VERSION 5.8 ;
BUSBITCHARS "[]" ;
DIVIDERCHAR "/" ;
UNITS
    DATABASE MICRONS 1000 ;
END UNITS

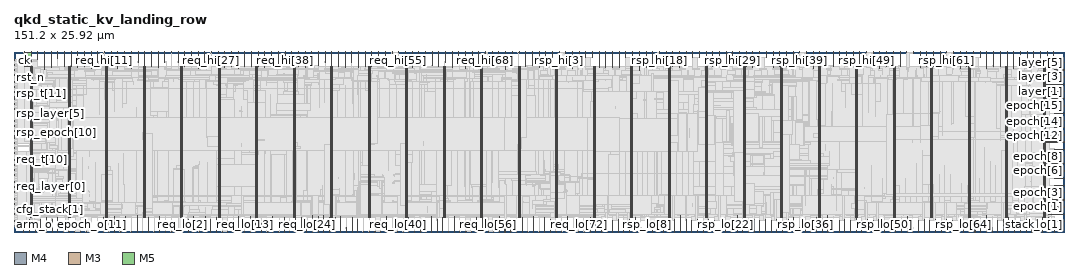
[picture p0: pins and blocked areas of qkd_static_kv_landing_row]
MACRO qkd_static_kv_landing_row
  FOREIGN qkd_static_kv_landing_row 0 0 ;
  CLASS BLOCK ;
  SIZE 151.2 BY 25.92 ;
  PIN arm
    DIRECTION INPUT ;
    USE SIGNAL ;
    PORT
      LAYER M4 ;
        RECT  151.116 1.488 151.2 1.512 ;
    END
    PORT
      LAYER M4 ;
        RECT  149.425 1.488 151.164 1.512 ;
    END
  END arm
  PIN arm_o
    DIRECTION OUTPUT ;
    USE SIGNAL ;
    PORT
      LAYER M3 ;
        RECT  1.404 0 1.422 0.038 ;
    END
    PORT
      LAYER M3 ;
        RECT  1.404 0.012 1.422 1.099 ;
    END
  END arm_o
  PIN cfg_group[0]
    DIRECTION INPUT ;
    USE SIGNAL ;
    PORT
      LAYER M4 ;
        RECT  0 1.104 0.084 1.128 ;
    END
  END cfg_group[0]
  PIN cfg_group[1]
    DIRECTION INPUT ;
    USE SIGNAL ;
    PORT
      LAYER M4 ;
        RECT  0 1.344 0.084 1.368 ;
    END
  END cfg_group[1]
  PIN cfg_group[2]
    DIRECTION INPUT ;
    USE SIGNAL ;
    PORT
      LAYER M4 ;
        RECT  0 1.584 0.084 1.608 ;
    END
  END cfg_group[2]
  PIN cfg_stack[0]
    DIRECTION INPUT ;
    USE SIGNAL ;
    PORT
      LAYER M4 ;
        RECT  0 1.824 0.084 1.848 ;
    END
  END cfg_stack[0]
  PIN cfg_stack[1]
    DIRECTION INPUT ;
    USE SIGNAL ;
    PORT
      LAYER M4 ;
        RECT  0 2.064 0.084 2.088 ;
    END
  END cfg_stack[1]
  PIN ck
    DIRECTION INPUT ;
    USE SIGNAL ;
    PORT
      LAYER M3 ;
        RECT  1.476 25.882 1.494 25.92 ;
    END
    PORT
      LAYER M3 ;
        RECT  1.476 25.819 1.494 25.901 ;
    END
  END ck
  PIN epoch[0]
    DIRECTION INPUT ;
    USE SIGNAL ;
    PORT
      LAYER M4 ;
        RECT  151.116 2.544 151.2 2.568 ;
    END
    PORT
      LAYER M4 ;
        RECT  148.979 2.544 151.164 2.568 ;
    END
  END epoch[0]
  PIN epoch[10]
    DIRECTION INPUT ;
    USE SIGNAL ;
    PORT
      LAYER M4 ;
        RECT  151.116 12.96 151.2 12.984 ;
    END
    PORT
      LAYER M4 ;
        RECT  148.504 12.96 151.164 12.984 ;
    END
  END epoch[10]
  PIN epoch[11]
    DIRECTION INPUT ;
    USE SIGNAL ;
    PORT
      LAYER M4 ;
        RECT  151.116 13.968 151.2 13.992 ;
    END
    PORT
      LAYER M4 ;
        RECT  149.857 13.968 151.164 13.992 ;
    END
  END epoch[11]
  PIN epoch[12]
    DIRECTION INPUT ;
    USE SIGNAL ;
    PORT
      LAYER M4 ;
        RECT  151.116 15.024 151.2 15.048 ;
    END
    PORT
      LAYER M4 ;
        RECT  149.857 15.024 151.164 15.048 ;
    END
  END epoch[12]
  PIN epoch[13]
    DIRECTION INPUT ;
    USE SIGNAL ;
    PORT
      LAYER M4 ;
        RECT  151.116 16.08 151.2 16.104 ;
    END
    PORT
      LAYER M4 ;
        RECT  148.504 16.08 151.164 16.104 ;
    END
  END epoch[13]
  PIN epoch[14]
    DIRECTION INPUT ;
    USE SIGNAL ;
    PORT
      LAYER M4 ;
        RECT  151.116 17.088 151.2 17.112 ;
    END
    PORT
      LAYER M4 ;
        RECT  149.857 17.088 151.164 17.112 ;
    END
  END epoch[14]
  PIN epoch[15]
    DIRECTION INPUT ;
    USE SIGNAL ;
    PORT
      LAYER M4 ;
        RECT  151.116 18.144 151.2 18.168 ;
    END
    PORT
      LAYER M4 ;
        RECT  151.081 18.144 151.164 18.168 ;
    END
  END epoch[15]
  PIN epoch[1]
    DIRECTION INPUT ;
    USE SIGNAL ;
    PORT
      LAYER M4 ;
        RECT  151.116 3.6 151.2 3.624 ;
    END
    PORT
      LAYER M4 ;
        RECT  149.857 3.6 151.164 3.624 ;
    END
  END epoch[1]
  PIN epoch[2]
    DIRECTION INPUT ;
    USE SIGNAL ;
    PORT
      LAYER M4 ;
        RECT  151.116 4.608 151.2 4.632 ;
    END
    PORT
      LAYER M4 ;
        RECT  149.497 4.608 151.164 4.632 ;
    END
  END epoch[2]
  PIN epoch[3]
    DIRECTION INPUT ;
    USE SIGNAL ;
    PORT
      LAYER M4 ;
        RECT  151.116 5.664 151.2 5.688 ;
    END
    PORT
      LAYER M4 ;
        RECT  149.857 5.664 151.164 5.688 ;
    END
  END epoch[3]
  PIN epoch[4]
    DIRECTION INPUT ;
    USE SIGNAL ;
    PORT
      LAYER M4 ;
        RECT  151.116 6.72 151.2 6.744 ;
    END
    PORT
      LAYER M4 ;
        RECT  149.857 6.72 151.164 6.744 ;
    END
  END epoch[4]
  PIN epoch[5]
    DIRECTION INPUT ;
    USE SIGNAL ;
    PORT
      LAYER M4 ;
        RECT  151.116 7.728 151.2 7.752 ;
    END
    PORT
      LAYER M4 ;
        RECT  149.857 7.728 151.164 7.752 ;
    END
  END epoch[5]
  PIN epoch[6]
    DIRECTION INPUT ;
    USE SIGNAL ;
    PORT
      LAYER M4 ;
        RECT  151.116 8.784 151.2 8.808 ;
    END
    PORT
      LAYER M4 ;
        RECT  149.857 8.784 151.164 8.808 ;
    END
  END epoch[6]
  PIN epoch[7]
    DIRECTION INPUT ;
    USE SIGNAL ;
    PORT
      LAYER M4 ;
        RECT  151.116 9.84 151.2 9.864 ;
    END
    PORT
      LAYER M4 ;
        RECT  148.504 9.84 151.164 9.864 ;
    END
  END epoch[7]
  PIN epoch[8]
    DIRECTION INPUT ;
    USE SIGNAL ;
    PORT
      LAYER M4 ;
        RECT  151.116 10.848 151.2 10.872 ;
    END
    PORT
      LAYER M4 ;
        RECT  151.081 10.848 151.164 10.872 ;
    END
  END epoch[8]
  PIN epoch[9]
    DIRECTION INPUT ;
    USE SIGNAL ;
    PORT
      LAYER M4 ;
        RECT  151.116 11.904 151.2 11.928 ;
    END
    PORT
      LAYER M4 ;
        RECT  149.857 11.904 151.164 11.928 ;
    END
  END epoch[9]
  PIN epoch_o[0]
    DIRECTION OUTPUT ;
    USE SIGNAL ;
    PORT
      LAYER M5 ;
        RECT  2.208 0 2.232 0.084 ;
    END
    PORT
      LAYER M5 ;
        RECT  2.208 0.016 2.232 1.763 ;
    END
  END epoch_o[0]
  PIN epoch_o[10]
    DIRECTION OUTPUT ;
    USE SIGNAL ;
    PORT
      LAYER M5 ;
        RECT  10.368 0 10.392 0.084 ;
    END
    PORT
      LAYER M5 ;
        RECT  10.368 0.016 10.392 0.131 ;
    END
  END epoch_o[10]
  PIN epoch_o[11]
    DIRECTION OUTPUT ;
    USE SIGNAL ;
    PORT
      LAYER M3 ;
        RECT  11.196 0 11.214 0.038 ;
    END
    PORT
      LAYER M3 ;
        RECT  11.196 0.012 11.214 0.091 ;
    END
  END epoch_o[11]
  PIN epoch_o[12]
    DIRECTION OUTPUT ;
    USE SIGNAL ;
    PORT
      LAYER M5 ;
        RECT  12 0 12.024 0.084 ;
    END
    PORT
      LAYER M5 ;
        RECT  12 0.016 12.024 0.131 ;
    END
  END epoch_o[12]
  PIN epoch_o[13]
    DIRECTION OUTPUT ;
    USE SIGNAL ;
    PORT
      LAYER M3 ;
        RECT  12.816 0 12.834 0.038 ;
    END
    PORT
      LAYER M3 ;
        RECT  12.816 0.012 12.834 2.143 ;
    END
  END epoch_o[13]
  PIN epoch_o[14]
    DIRECTION OUTPUT ;
    USE SIGNAL ;
    PORT
      LAYER M5 ;
        RECT  13.632 0 13.656 0.084 ;
    END
    PORT
      LAYER M5 ;
        RECT  13.632 0.016 13.656 0.131 ;
    END
  END epoch_o[14]
  PIN epoch_o[15]
    DIRECTION OUTPUT ;
    USE SIGNAL ;
    PORT
      LAYER M3 ;
        RECT  14.436 0 14.454 0.038 ;
    END
    PORT
      LAYER M3 ;
        RECT  14.436 0.012 14.454 2.191 ;
    END
  END epoch_o[15]
  PIN epoch_o[1]
    DIRECTION OUTPUT ;
    USE SIGNAL ;
    PORT
      LAYER M3 ;
        RECT  3.024 0 3.042 0.038 ;
    END
    PORT
      LAYER M3 ;
        RECT  3.024 0.012 3.042 1.339 ;
    END
  END epoch_o[1]
  PIN epoch_o[2]
    DIRECTION OUTPUT ;
    USE SIGNAL ;
    PORT
      LAYER M5 ;
        RECT  3.84 0 3.864 0.084 ;
    END
    PORT
      LAYER M5 ;
        RECT  3.84 0.016 3.864 1.763 ;
    END
  END epoch_o[2]
  PIN epoch_o[3]
    DIRECTION OUTPUT ;
    USE SIGNAL ;
    PORT
      LAYER M3 ;
        RECT  4.644 0 4.662 0.038 ;
    END
    PORT
      LAYER M3 ;
        RECT  4.644 0.012 4.662 2.029 ;
    END
  END epoch_o[3]
  PIN epoch_o[4]
    DIRECTION OUTPUT ;
    USE SIGNAL ;
    PORT
      LAYER M5 ;
        RECT  5.472 0 5.496 0.084 ;
    END
    PORT
      LAYER M5 ;
        RECT  5.472 0.016 5.496 1.763 ;
    END
  END epoch_o[4]
  PIN epoch_o[5]
    DIRECTION OUTPUT ;
    USE SIGNAL ;
    PORT
      LAYER M3 ;
        RECT  6.3 0 6.318 0.038 ;
    END
    PORT
      LAYER M3 ;
        RECT  6.3 0.012 6.318 2.101 ;
    END
  END epoch_o[5]
  PIN epoch_o[6]
    DIRECTION OUTPUT ;
    USE SIGNAL ;
    PORT
      LAYER M5 ;
        RECT  7.104 0 7.128 0.084 ;
    END
    PORT
      LAYER M5 ;
        RECT  7.104 0.016 7.128 0.611 ;
    END
  END epoch_o[6]
  PIN epoch_o[7]
    DIRECTION OUTPUT ;
    USE SIGNAL ;
    PORT
      LAYER M3 ;
        RECT  7.92 0 7.938 0.038 ;
    END
    PORT
      LAYER M3 ;
        RECT  7.92 0.012 7.938 0.031 ;
    END
    PORT
      LAYER M3 ;
        RECT  7.776 0.031 7.938 0.059 ;
    END
  END epoch_o[7]
  PIN epoch_o[8]
    DIRECTION OUTPUT ;
    USE SIGNAL ;
    PORT
      LAYER M5 ;
        RECT  8.736 0 8.76 0.084 ;
    END
    PORT
      LAYER M5 ;
        RECT  8.736 0.016 8.76 0.131 ;
    END
  END epoch_o[8]
  PIN epoch_o[9]
    DIRECTION OUTPUT ;
    USE SIGNAL ;
    PORT
      LAYER M3 ;
        RECT  9.54 0 9.558 0.038 ;
    END
    PORT
      LAYER M3 ;
        RECT  9.54 0.012 9.558 0.091 ;
    END
  END epoch_o[9]
  PIN fault
    DIRECTION OUTPUT ;
    USE SIGNAL ;
    PORT
      LAYER M4 ;
        RECT  0 2.352 0.084 2.376 ;
    END
  END fault
  PIN group_o[0]
    DIRECTION OUTPUT ;
    USE SIGNAL ;
    PORT
      LAYER M5 ;
        RECT  15.264 0 15.288 0.084 ;
    END
    PORT
      LAYER M5 ;
        RECT  15.264 0.016 15.288 0.131 ;
    END
  END group_o[0]
  PIN group_o[1]
    DIRECTION OUTPUT ;
    USE SIGNAL ;
    PORT
      LAYER M3 ;
        RECT  16.092 0 16.11 0.038 ;
    END
    PORT
      LAYER M3 ;
        RECT  16.092 0.012 16.11 2.191 ;
    END
  END group_o[1]
  PIN group_o[2]
    DIRECTION OUTPUT ;
    USE SIGNAL ;
    PORT
      LAYER M5 ;
        RECT  16.896 0 16.92 0.084 ;
    END
    PORT
      LAYER M5 ;
        RECT  16.896 0.016 16.92 0.131 ;
    END
  END group_o[2]
  PIN layer[0]
    DIRECTION INPUT ;
    USE SIGNAL ;
    PORT
      LAYER M4 ;
        RECT  151.116 19.2 151.2 19.224 ;
    END
    PORT
      LAYER M4 ;
        RECT  148.504 19.2 151.164 19.224 ;
    END
  END layer[0]
  PIN layer[1]
    DIRECTION INPUT ;
    USE SIGNAL ;
    PORT
      LAYER M4 ;
        RECT  151.116 20.208 151.2 20.232 ;
    END
    PORT
      LAYER M4 ;
        RECT  148.504 20.208 151.164 20.232 ;
    END
  END layer[1]
  PIN layer[2]
    DIRECTION INPUT ;
    USE SIGNAL ;
    PORT
      LAYER M4 ;
        RECT  151.116 21.264 151.2 21.288 ;
    END
    PORT
      LAYER M4 ;
        RECT  148.504 21.264 151.164 21.288 ;
    END
  END layer[2]
  PIN layer[3]
    DIRECTION INPUT ;
    USE SIGNAL ;
    PORT
      LAYER M4 ;
        RECT  151.116 22.32 151.2 22.344 ;
    END
    PORT
      LAYER M4 ;
        RECT  149.893 22.32 151.164 22.344 ;
    END
  END layer[3]
  PIN layer[4]
    DIRECTION INPUT ;
    USE SIGNAL ;
    PORT
      LAYER M4 ;
        RECT  151.116 23.328 151.2 23.352 ;
    END
    PORT
      LAYER M4 ;
        RECT  149.857 23.328 151.164 23.352 ;
    END
  END layer[4]
  PIN layer[5]
    DIRECTION INPUT ;
    USE SIGNAL ;
    PORT
      LAYER M4 ;
        RECT  151.116 24.384 151.2 24.408 ;
    END
    PORT
      LAYER M4 ;
        RECT  150.433 24.384 151.164 24.408 ;
    END
  END layer[5]
  PIN layer_o[0]
    DIRECTION OUTPUT ;
    USE SIGNAL ;
    PORT
      LAYER M3 ;
        RECT  17.712 0 17.73 0.038 ;
    END
    PORT
      LAYER M3 ;
        RECT  17.712 0.012 17.73 2.335 ;
    END
  END layer_o[0]
  PIN layer_o[1]
    DIRECTION OUTPUT ;
    USE SIGNAL ;
    PORT
      LAYER M5 ;
        RECT  18.528 0 18.552 0.084 ;
    END
    PORT
      LAYER M5 ;
        RECT  18.528 0.016 18.552 0.131 ;
    END
  END layer_o[1]
  PIN layer_o[2]
    DIRECTION OUTPUT ;
    USE SIGNAL ;
    PORT
      LAYER M3 ;
        RECT  19.332 0 19.35 0.038 ;
    END
    PORT
      LAYER M3 ;
        RECT  19.332 0.012 19.35 2.143 ;
    END
  END layer_o[2]
  PIN layer_o[3]
    DIRECTION OUTPUT ;
    USE SIGNAL ;
    PORT
      LAYER M5 ;
        RECT  20.16 0 20.184 0.084 ;
    END
    PORT
      LAYER M5 ;
        RECT  20.16 0.016 20.184 0.131 ;
    END
  END layer_o[3]
  PIN layer_o[4]
    DIRECTION OUTPUT ;
    USE SIGNAL ;
    PORT
      LAYER M3 ;
        RECT  20.952 0 20.97 0.038 ;
    END
    PORT
      LAYER M3 ;
        RECT  20.952 0.012 20.97 2.263 ;
    END
  END layer_o[4]
  PIN layer_o[5]
    DIRECTION OUTPUT ;
    USE SIGNAL ;
    PORT
      LAYER M5 ;
        RECT  21.792 0 21.816 0.084 ;
    END
    PORT
      LAYER M5 ;
        RECT  21.792 0.016 21.816 0.131 ;
    END
  END layer_o[5]
  PIN req_epoch[0]
    DIRECTION INPUT ;
    USE SIGNAL ;
    PORT
      LAYER M4 ;
        RECT  0 2.592 0.084 2.616 ;
    END
  END req_epoch[0]
  PIN req_epoch[10]
    DIRECTION INPUT ;
    USE SIGNAL ;
    PORT
      LAYER M4 ;
        RECT  0 4.992 0.084 5.016 ;
    END
  END req_epoch[10]
  PIN req_epoch[11]
    DIRECTION INPUT ;
    USE SIGNAL ;
    PORT
      LAYER M4 ;
        RECT  0 5.28 0.084 5.304 ;
    END
  END req_epoch[11]
  PIN req_epoch[12]
    DIRECTION INPUT ;
    USE SIGNAL ;
    PORT
      LAYER M4 ;
        RECT  0 5.52 0.084 5.544 ;
    END
  END req_epoch[12]
  PIN req_epoch[13]
    DIRECTION INPUT ;
    USE SIGNAL ;
    PORT
      LAYER M4 ;
        RECT  0 5.76 0.084 5.784 ;
    END
  END req_epoch[13]
  PIN req_epoch[14]
    DIRECTION INPUT ;
    USE SIGNAL ;
    PORT
      LAYER M4 ;
        RECT  0 6 0.084 6.024 ;
    END
  END req_epoch[14]
  PIN req_epoch[15]
    DIRECTION INPUT ;
    USE SIGNAL ;
    PORT
      LAYER M4 ;
        RECT  0 6.24 0.084 6.264 ;
    END
  END req_epoch[15]
  PIN req_epoch[1]
    DIRECTION INPUT ;
    USE SIGNAL ;
    PORT
      LAYER M4 ;
        RECT  0 2.832 0.084 2.856 ;
    END
  END req_epoch[1]
  PIN req_epoch[2]
    DIRECTION INPUT ;
    USE SIGNAL ;
    PORT
      LAYER M4 ;
        RECT  0 3.072 0.084 3.096 ;
    END
  END req_epoch[2]
  PIN req_epoch[3]
    DIRECTION INPUT ;
    USE SIGNAL ;
    PORT
      LAYER M4 ;
        RECT  0 3.312 0.084 3.336 ;
    END
  END req_epoch[3]
  PIN req_epoch[4]
    DIRECTION INPUT ;
    USE SIGNAL ;
    PORT
      LAYER M4 ;
        RECT  0 3.552 0.084 3.576 ;
    END
  END req_epoch[4]
  PIN req_epoch[5]
    DIRECTION INPUT ;
    USE SIGNAL ;
    PORT
      LAYER M4 ;
        RECT  0 3.792 0.084 3.816 ;
    END
  END req_epoch[5]
  PIN req_epoch[6]
    DIRECTION INPUT ;
    USE SIGNAL ;
    PORT
      LAYER M4 ;
        RECT  0 4.032 0.084 4.056 ;
    END
  END req_epoch[6]
  PIN req_epoch[7]
    DIRECTION INPUT ;
    USE SIGNAL ;
    PORT
      LAYER M4 ;
        RECT  0 4.272 0.084 4.296 ;
    END
  END req_epoch[7]
  PIN req_epoch[8]
    DIRECTION INPUT ;
    USE SIGNAL ;
    PORT
      LAYER M4 ;
        RECT  0 4.512 0.084 4.536 ;
    END
  END req_epoch[8]
  PIN req_epoch[9]
    DIRECTION INPUT ;
    USE SIGNAL ;
    PORT
      LAYER M4 ;
        RECT  0 4.752 0.084 4.776 ;
    END
  END req_epoch[9]
  PIN req_hi[0]
    DIRECTION OUTPUT ;
    USE SIGNAL ;
    PORT
      LAYER M5 ;
        RECT  2.448 25.836 2.472 25.92 ;
    END
    PORT
      LAYER M5 ;
        RECT  1.488 23.783 2.472 25.859 ;
    END
    PORT
      LAYER M5 ;
        RECT  2.448 25.859 2.472 25.872 ;
    END
  END req_hi[0]
  PIN req_hi[10]
    DIRECTION OUTPUT ;
    USE SIGNAL ;
    PORT
      LAYER M5 ;
        RECT  12.048 25.836 12.072 25.92 ;
    END
    PORT
      LAYER M5 ;
        RECT  12.048 24.469 12.072 25.872 ;
    END
  END req_hi[10]
  PIN req_hi[11]
    DIRECTION OUTPUT ;
    USE SIGNAL ;
    PORT
      LAYER M3 ;
        RECT  13.032 25.882 13.05 25.92 ;
    END
    PORT
      LAYER M3 ;
        RECT  12.96 25.861 13.05 25.889 ;
    END
    PORT
      LAYER M3 ;
        RECT  13.032 25.889 13.05 25.901 ;
    END
  END req_hi[11]
  PIN req_hi[12]
    DIRECTION OUTPUT ;
    USE SIGNAL ;
    PORT
      LAYER M5 ;
        RECT  13.968 25.836 13.992 25.92 ;
    END
    PORT
      LAYER M5 ;
        RECT  13.968 23.941 13.992 25.872 ;
    END
  END req_hi[12]
  PIN req_hi[13]
    DIRECTION OUTPUT ;
    USE SIGNAL ;
    PORT
      LAYER M3 ;
        RECT  14.94 25.882 14.958 25.92 ;
    END
    PORT
      LAYER M3 ;
        RECT  14.94 23.585 14.958 25.901 ;
    END
  END req_hi[13]
  PIN req_hi[14]
    DIRECTION OUTPUT ;
    USE SIGNAL ;
    PORT
      LAYER M5 ;
        RECT  15.888 25.836 15.912 25.92 ;
    END
    PORT
      LAYER M5 ;
        RECT  15.888 24.469 15.912 25.872 ;
    END
  END req_hi[14]
  PIN req_hi[15]
    DIRECTION OUTPUT ;
    USE SIGNAL ;
    PORT
      LAYER M3 ;
        RECT  16.884 25.882 16.902 25.92 ;
    END
    PORT
      LAYER M3 ;
        RECT  16.884 23.549 16.902 25.901 ;
    END
  END req_hi[15]
  PIN req_hi[16]
    DIRECTION OUTPUT ;
    USE SIGNAL ;
    PORT
      LAYER M5 ;
        RECT  17.856 25.836 17.88 25.92 ;
    END
    PORT
      LAYER M5 ;
        RECT  17.856 24.469 17.88 25.872 ;
    END
  END req_hi[16]
  PIN req_hi[17]
    DIRECTION OUTPUT ;
    USE SIGNAL ;
    PORT
      LAYER M3 ;
        RECT  18.792 25.882 18.81 25.92 ;
    END
    PORT
      LAYER M3 ;
        RECT  18.792 23.777 18.81 25.901 ;
    END
  END req_hi[17]
  PIN req_hi[18]
    DIRECTION OUTPUT ;
    USE SIGNAL ;
    PORT
      LAYER M5 ;
        RECT  19.776 25.836 19.8 25.92 ;
    END
    PORT
      LAYER M5 ;
        RECT  19.776 23.893 19.8 25.872 ;
    END
  END req_hi[18]
  PIN req_hi[19]
    DIRECTION OUTPUT ;
    USE SIGNAL ;
    PORT
      LAYER M3 ;
        RECT  20.736 25.882 20.754 25.92 ;
    END
    PORT
      LAYER M3 ;
        RECT  20.736 23.693 20.754 25.901 ;
    END
  END req_hi[19]
  PIN req_hi[1]
    DIRECTION OUTPUT ;
    USE SIGNAL ;
    PORT
      LAYER M3 ;
        RECT  3.384 25.882 3.402 25.92 ;
    END
    PORT
      LAYER M3 ;
        RECT  3.384 24.797 3.402 25.901 ;
    END
  END req_hi[1]
  PIN req_hi[20]
    DIRECTION OUTPUT ;
    USE SIGNAL ;
    PORT
      LAYER M5 ;
        RECT  21.696 25.836 21.72 25.92 ;
    END
    PORT
      LAYER M5 ;
        RECT  21.696 24.469 21.72 25.872 ;
    END
  END req_hi[20]
  PIN req_hi[21]
    DIRECTION OUTPUT ;
    USE SIGNAL ;
    PORT
      LAYER M3 ;
        RECT  22.644 25.882 22.662 25.92 ;
    END
    PORT
      LAYER M3 ;
        RECT  22.644 25.861 22.734 25.889 ;
    END
    PORT
      LAYER M3 ;
        RECT  22.644 25.889 22.662 25.901 ;
    END
  END req_hi[21]
  PIN req_hi[22]
    DIRECTION OUTPUT ;
    USE SIGNAL ;
    PORT
      LAYER M5 ;
        RECT  23.616 25.836 23.64 25.92 ;
    END
    PORT
      LAYER M5 ;
        RECT  23.616 24.469 23.64 25.872 ;
    END
  END req_hi[22]
  PIN req_hi[23]
    DIRECTION OUTPUT ;
    USE SIGNAL ;
    PORT
      LAYER M3 ;
        RECT  24.588 25.882 24.606 25.92 ;
    END
    PORT
      LAYER M3 ;
        RECT  24.588 23.777 24.606 25.901 ;
    END
  END req_hi[23]
  PIN req_hi[24]
    DIRECTION OUTPUT ;
    USE SIGNAL ;
    PORT
      LAYER M5 ;
        RECT  25.536 25.836 25.56 25.92 ;
    END
    PORT
      LAYER M5 ;
        RECT  25.536 23.941 25.56 25.872 ;
    END
  END req_hi[24]
  PIN req_hi[25]
    DIRECTION OUTPUT ;
    USE SIGNAL ;
    PORT
      LAYER M3 ;
        RECT  26.496 25.882 26.514 25.92 ;
    END
    PORT
      LAYER M3 ;
        RECT  26.496 23.549 26.514 25.901 ;
    END
  END req_hi[25]
  PIN req_hi[26]
    DIRECTION OUTPUT ;
    USE SIGNAL ;
    PORT
      LAYER M5 ;
        RECT  27.456 25.836 27.48 25.92 ;
    END
    PORT
      LAYER M5 ;
        RECT  27.456 24.469 27.48 25.872 ;
    END
  END req_hi[26]
  PIN req_hi[27]
    DIRECTION OUTPUT ;
    USE SIGNAL ;
    PORT
      LAYER M3 ;
        RECT  28.44 25.882 28.458 25.92 ;
    END
    PORT
      LAYER M3 ;
        RECT  28.368 25.861 28.458 25.889 ;
    END
    PORT
      LAYER M3 ;
        RECT  28.44 25.889 28.458 25.901 ;
    END
  END req_hi[27]
  PIN req_hi[28]
    DIRECTION OUTPUT ;
    USE SIGNAL ;
    PORT
      LAYER M5 ;
        RECT  29.376 25.836 29.4 25.92 ;
    END
    PORT
      LAYER M5 ;
        RECT  29.376 24.469 29.4 25.872 ;
    END
  END req_hi[28]
  PIN req_hi[29]
    DIRECTION OUTPUT ;
    USE SIGNAL ;
    PORT
      LAYER M3 ;
        RECT  30.348 25.882 30.366 25.92 ;
    END
    PORT
      LAYER M3 ;
        RECT  30.348 23.729 30.366 25.901 ;
    END
  END req_hi[29]
  PIN req_hi[2]
    DIRECTION OUTPUT ;
    USE SIGNAL ;
    PORT
      LAYER M5 ;
        RECT  4.368 25.836 4.392 25.92 ;
    END
    PORT
      LAYER M5 ;
        RECT  4.368 23.365 4.392 25.872 ;
    END
  END req_hi[2]
  PIN req_hi[30]
    DIRECTION OUTPUT ;
    USE SIGNAL ;
    PORT
      LAYER M5 ;
        RECT  31.296 25.836 31.32 25.92 ;
    END
    PORT
      LAYER M5 ;
        RECT  31.296 23.893 31.32 25.872 ;
    END
  END req_hi[30]
  PIN req_hi[31]
    DIRECTION OUTPUT ;
    USE SIGNAL ;
    PORT
      LAYER M3 ;
        RECT  32.292 25.882 32.31 25.92 ;
    END
    PORT
      LAYER M3 ;
        RECT  32.292 23.549 32.31 25.901 ;
    END
  END req_hi[31]
  PIN req_hi[32]
    DIRECTION OUTPUT ;
    USE SIGNAL ;
    PORT
      LAYER M5 ;
        RECT  33.216 25.836 33.24 25.92 ;
    END
    PORT
      LAYER M5 ;
        RECT  33.216 23.893 33.24 25.872 ;
    END
  END req_hi[32]
  PIN req_hi[33]
    DIRECTION OUTPUT ;
    USE SIGNAL ;
    PORT
      LAYER M3 ;
        RECT  34.2 25.882 34.218 25.92 ;
    END
    PORT
      LAYER M3 ;
        RECT  34.2 23.777 34.218 25.901 ;
    END
  END req_hi[33]
  PIN req_hi[34]
    DIRECTION OUTPUT ;
    USE SIGNAL ;
    PORT
      LAYER M5 ;
        RECT  35.184 25.836 35.208 25.92 ;
    END
    PORT
      LAYER M5 ;
        RECT  35.184 23.893 35.208 25.872 ;
    END
  END req_hi[34]
  PIN req_hi[35]
    DIRECTION OUTPUT ;
    USE SIGNAL ;
    PORT
      LAYER M3 ;
        RECT  36.108 25.882 36.126 25.92 ;
    END
    PORT
      LAYER M3 ;
        RECT  36.108 23.729 36.126 25.901 ;
    END
  END req_hi[35]
  PIN req_hi[36]
    DIRECTION OUTPUT ;
    USE SIGNAL ;
    PORT
      LAYER M5 ;
        RECT  37.104 25.836 37.128 25.92 ;
    END
    PORT
      LAYER M5 ;
        RECT  37.104 24.469 37.128 25.872 ;
    END
  END req_hi[36]
  PIN req_hi[37]
    DIRECTION OUTPUT ;
    USE SIGNAL ;
    PORT
      LAYER M3 ;
        RECT  38.052 25.882 38.07 25.92 ;
    END
    PORT
      LAYER M3 ;
        RECT  38.052 23.729 38.07 25.901 ;
    END
  END req_hi[37]
  PIN req_hi[38]
    DIRECTION OUTPUT ;
    USE SIGNAL ;
    PORT
      LAYER M5 ;
        RECT  39.024 25.836 39.048 25.92 ;
    END
    PORT
      LAYER M5 ;
        RECT  39.024 24.469 39.048 25.872 ;
    END
  END req_hi[38]
  PIN req_hi[39]
    DIRECTION OUTPUT ;
    USE SIGNAL ;
    PORT
      LAYER M3 ;
        RECT  39.96 25.882 39.978 25.92 ;
    END
    PORT
      LAYER M3 ;
        RECT  39.96 23.777 39.978 25.901 ;
    END
  END req_hi[39]
  PIN req_hi[3]
    DIRECTION OUTPUT ;
    USE SIGNAL ;
    PORT
      LAYER M3 ;
        RECT  5.328 25.882 5.346 25.92 ;
    END
    PORT
      LAYER M3 ;
        RECT  5.328 23.729 5.346 25.901 ;
    END
  END req_hi[3]
  PIN req_hi[40]
    DIRECTION OUTPUT ;
    USE SIGNAL ;
    PORT
      LAYER M5 ;
        RECT  40.944 25.836 40.968 25.92 ;
    END
    PORT
      LAYER M5 ;
        RECT  40.944 23.893 40.968 25.872 ;
    END
  END req_hi[40]
  PIN req_hi[41]
    DIRECTION OUTPUT ;
    USE SIGNAL ;
    PORT
      LAYER M3 ;
        RECT  41.904 25.882 41.922 25.92 ;
    END
    PORT
      LAYER M3 ;
        RECT  41.904 23.621 41.922 25.901 ;
    END
  END req_hi[41]
  PIN req_hi[42]
    DIRECTION OUTPUT ;
    USE SIGNAL ;
    PORT
      LAYER M5 ;
        RECT  42.864 25.836 42.888 25.92 ;
    END
    PORT
      LAYER M5 ;
        RECT  42.864 23.893 42.888 25.872 ;
    END
  END req_hi[42]
  PIN req_hi[43]
    DIRECTION OUTPUT ;
    USE SIGNAL ;
    PORT
      LAYER M3 ;
        RECT  43.812 25.882 43.83 25.92 ;
    END
    PORT
      LAYER M3 ;
        RECT  43.812 23.933 43.83 25.901 ;
    END
  END req_hi[43]
  PIN req_hi[44]
    DIRECTION OUTPUT ;
    USE SIGNAL ;
    PORT
      LAYER M5 ;
        RECT  44.784 25.836 44.808 25.92 ;
    END
    PORT
      LAYER M5 ;
        RECT  44.784 24.469 44.808 25.872 ;
    END
  END req_hi[44]
  PIN req_hi[45]
    DIRECTION OUTPUT ;
    USE SIGNAL ;
    PORT
      LAYER M3 ;
        RECT  45.756 25.882 45.774 25.92 ;
    END
    PORT
      LAYER M3 ;
        RECT  45.756 23.777 45.774 25.901 ;
    END
  END req_hi[45]
  PIN req_hi[46]
    DIRECTION OUTPUT ;
    USE SIGNAL ;
    PORT
      LAYER M5 ;
        RECT  46.704 25.836 46.728 25.92 ;
    END
    PORT
      LAYER M5 ;
        RECT  46.704 23.769 46.728 25.872 ;
    END
  END req_hi[46]
  PIN req_hi[47]
    DIRECTION OUTPUT ;
    USE SIGNAL ;
    PORT
      LAYER M3 ;
        RECT  47.664 25.882 47.682 25.92 ;
    END
    PORT
      LAYER M3 ;
        RECT  47.664 23.621 47.682 25.901 ;
    END
  END req_hi[47]
  PIN req_hi[48]
    DIRECTION OUTPUT ;
    USE SIGNAL ;
    PORT
      LAYER M5 ;
        RECT  48.624 25.836 48.648 25.92 ;
    END
    PORT
      LAYER M5 ;
        RECT  48.624 24.469 48.648 25.872 ;
    END
  END req_hi[48]
  PIN req_hi[49]
    DIRECTION OUTPUT ;
    USE SIGNAL ;
    PORT
      LAYER M3 ;
        RECT  49.608 25.882 49.626 25.92 ;
    END
    PORT
      LAYER M3 ;
        RECT  49.608 23.657 49.626 25.901 ;
    END
  END req_hi[49]
  PIN req_hi[4]
    DIRECTION OUTPUT ;
    USE SIGNAL ;
    PORT
      LAYER M5 ;
        RECT  6.288 25.836 6.312 25.92 ;
    END
    PORT
      LAYER M5 ;
        RECT  6.288 25.045 6.312 25.872 ;
    END
  END req_hi[4]
  PIN req_hi[50]
    DIRECTION OUTPUT ;
    USE SIGNAL ;
    PORT
      LAYER M5 ;
        RECT  50.544 25.836 50.568 25.92 ;
    END
    PORT
      LAYER M5 ;
        RECT  50.544 23.783 50.568 25.872 ;
    END
  END req_hi[50]
  PIN req_hi[51]
    DIRECTION OUTPUT ;
    USE SIGNAL ;
    PORT
      LAYER M3 ;
        RECT  51.516 25.882 51.534 25.92 ;
    END
    PORT
      LAYER M3 ;
        RECT  51.516 23.777 51.534 25.901 ;
    END
  END req_hi[51]
  PIN req_hi[52]
    DIRECTION OUTPUT ;
    USE SIGNAL ;
    PORT
      LAYER M5 ;
        RECT  52.464 25.836 52.488 25.92 ;
    END
    PORT
      LAYER M5 ;
        RECT  52.464 25.045 52.488 25.872 ;
    END
  END req_hi[52]
  PIN req_hi[53]
    DIRECTION OUTPUT ;
    USE SIGNAL ;
    PORT
      LAYER M3 ;
        RECT  53.46 25.882 53.478 25.92 ;
    END
    PORT
      LAYER M3 ;
        RECT  53.46 23.621 53.478 25.901 ;
    END
  END req_hi[53]
  PIN req_hi[54]
    DIRECTION OUTPUT ;
    USE SIGNAL ;
    PORT
      LAYER M5 ;
        RECT  54.432 25.836 54.456 25.92 ;
    END
    PORT
      LAYER M5 ;
        RECT  54.432 25.765 54.456 25.872 ;
    END
  END req_hi[54]
  PIN req_hi[55]
    DIRECTION OUTPUT ;
    USE SIGNAL ;
    PORT
      LAYER M3 ;
        RECT  55.368 25.882 55.386 25.92 ;
    END
    PORT
      LAYER M3 ;
        RECT  55.296 25.861 55.386 25.889 ;
    END
    PORT
      LAYER M3 ;
        RECT  55.368 25.889 55.386 25.901 ;
    END
  END req_hi[55]
  PIN req_hi[56]
    DIRECTION OUTPUT ;
    USE SIGNAL ;
    PORT
      LAYER M5 ;
        RECT  56.352 25.836 56.376 25.92 ;
    END
    PORT
      LAYER M5 ;
        RECT  56.352 23.893 56.376 25.872 ;
    END
  END req_hi[56]
  PIN req_hi[57]
    DIRECTION OUTPUT ;
    USE SIGNAL ;
    PORT
      LAYER M3 ;
        RECT  57.312 25.882 57.33 25.92 ;
    END
    PORT
      LAYER M3 ;
        RECT  57.312 23.621 57.33 25.901 ;
    END
  END req_hi[57]
  PIN req_hi[58]
    DIRECTION OUTPUT ;
    USE SIGNAL ;
    PORT
      LAYER M5 ;
        RECT  58.272 25.836 58.296 25.92 ;
    END
    PORT
      LAYER M5 ;
        RECT  58.272 24.469 58.296 25.872 ;
    END
  END req_hi[58]
  PIN req_hi[59]
    DIRECTION OUTPUT ;
    USE SIGNAL ;
    PORT
      LAYER M3 ;
        RECT  59.22 25.882 59.238 25.92 ;
    END
    PORT
      LAYER M3 ;
        RECT  59.22 24.509 59.238 25.901 ;
    END
  END req_hi[59]
  PIN req_hi[5]
    DIRECTION OUTPUT ;
    USE SIGNAL ;
    PORT
      LAYER M3 ;
        RECT  7.236 25.882 7.254 25.92 ;
    END
    PORT
      LAYER M3 ;
        RECT  7.236 23.777 7.254 25.901 ;
    END
  END req_hi[5]
  PIN req_hi[60]
    DIRECTION OUTPUT ;
    USE SIGNAL ;
    PORT
      LAYER M5 ;
        RECT  60.192 25.836 60.216 25.92 ;
    END
    PORT
      LAYER M5 ;
        RECT  60.192 23.941 60.216 25.872 ;
    END
  END req_hi[60]
  PIN req_hi[61]
    DIRECTION OUTPUT ;
    USE SIGNAL ;
    PORT
      LAYER M3 ;
        RECT  61.164 25.882 61.182 25.92 ;
    END
    PORT
      LAYER M3 ;
        RECT  61.164 23.777 61.182 25.901 ;
    END
  END req_hi[61]
  PIN req_hi[62]
    DIRECTION OUTPUT ;
    USE SIGNAL ;
    PORT
      LAYER M5 ;
        RECT  62.112 25.836 62.136 25.92 ;
    END
    PORT
      LAYER M5 ;
        RECT  62.112 24.469 62.136 25.872 ;
    END
  END req_hi[62]
  PIN req_hi[63]
    DIRECTION OUTPUT ;
    USE SIGNAL ;
    PORT
      LAYER M3 ;
        RECT  63.072 25.882 63.09 25.92 ;
    END
    PORT
      LAYER M3 ;
        RECT  63.072 23.621 63.09 25.901 ;
    END
  END req_hi[63]
  PIN req_hi[64]
    DIRECTION OUTPUT ;
    USE SIGNAL ;
    PORT
      LAYER M5 ;
        RECT  64.032 25.836 64.056 25.92 ;
    END
    PORT
      LAYER M5 ;
        RECT  64.032 25.045 64.056 25.872 ;
    END
  END req_hi[64]
  PIN req_hi[65]
    DIRECTION OUTPUT ;
    USE SIGNAL ;
    PORT
      LAYER M3 ;
        RECT  65.016 25.882 65.034 25.92 ;
    END
    PORT
      LAYER M3 ;
        RECT  65.016 23.585 65.034 25.901 ;
    END
  END req_hi[65]
  PIN req_hi[66]
    DIRECTION OUTPUT ;
    USE SIGNAL ;
    PORT
      LAYER M5 ;
        RECT  65.952 25.836 65.976 25.92 ;
    END
    PORT
      LAYER M5 ;
        RECT  65.952 23.893 65.976 25.872 ;
    END
  END req_hi[66]
  PIN req_hi[67]
    DIRECTION OUTPUT ;
    USE SIGNAL ;
    PORT
      LAYER M3 ;
        RECT  66.924 25.882 66.942 25.92 ;
    END
    PORT
      LAYER M3 ;
        RECT  66.924 23.777 66.942 25.901 ;
    END
  END req_hi[67]
  PIN req_hi[68]
    DIRECTION OUTPUT ;
    USE SIGNAL ;
    PORT
      LAYER M5 ;
        RECT  67.872 25.836 67.896 25.92 ;
    END
    PORT
      LAYER M5 ;
        RECT  67.872 25.765 67.896 25.872 ;
    END
  END req_hi[68]
  PIN req_hi[69]
    DIRECTION OUTPUT ;
    USE SIGNAL ;
    PORT
      LAYER M3 ;
        RECT  68.868 25.882 68.886 25.92 ;
    END
    PORT
      LAYER M3 ;
        RECT  68.868 23.729 68.886 25.901 ;
    END
  END req_hi[69]
  PIN req_hi[6]
    DIRECTION OUTPUT ;
    USE SIGNAL ;
    PORT
      LAYER M5 ;
        RECT  8.208 25.836 8.232 25.92 ;
    END
    PORT
      LAYER M5 ;
        RECT  8.208 23.893 8.232 25.872 ;
    END
  END req_hi[6]
  PIN req_hi[70]
    DIRECTION OUTPUT ;
    USE SIGNAL ;
    PORT
      LAYER M5 ;
        RECT  69.792 25.836 69.816 25.92 ;
    END
    PORT
      LAYER M5 ;
        RECT  69.792 23.941 69.816 25.872 ;
    END
  END req_hi[70]
  PIN req_hi[71]
    DIRECTION OUTPUT ;
    USE SIGNAL ;
    PORT
      LAYER M3 ;
        RECT  70.776 25.882 70.794 25.92 ;
    END
    PORT
      LAYER M3 ;
        RECT  70.776 23.351 70.794 25.901 ;
    END
  END req_hi[71]
  PIN req_hi[72]
    DIRECTION OUTPUT ;
    USE SIGNAL ;
    PORT
      LAYER M5 ;
        RECT  71.76 25.836 71.784 25.92 ;
    END
    PORT
      LAYER M5 ;
        RECT  71.76 23.893 71.784 25.872 ;
    END
  END req_hi[72]
  PIN req_hi[73]
    DIRECTION OUTPUT ;
    USE SIGNAL ;
    PORT
      LAYER M3 ;
        RECT  72.72 25.882 72.738 25.92 ;
    END
    PORT
      LAYER M3 ;
        RECT  72.576 25.861 72.738 25.889 ;
    END
    PORT
      LAYER M3 ;
        RECT  72.72 25.889 72.738 25.901 ;
    END
  END req_hi[73]
  PIN req_hi[74]
    DIRECTION OUTPUT ;
    USE SIGNAL ;
    PORT
      LAYER M5 ;
        RECT  73.68 25.836 73.704 25.92 ;
    END
    PORT
      LAYER M5 ;
        RECT  73.68 23.893 73.704 25.872 ;
    END
  END req_hi[74]
  PIN req_hi[75]
    DIRECTION OUTPUT ;
    USE SIGNAL ;
    PORT
      LAYER M3 ;
        RECT  74.628 25.882 74.646 25.92 ;
    END
    PORT
      LAYER M3 ;
        RECT  74.628 23.933 74.646 25.901 ;
    END
  END req_hi[75]
  PIN req_hi[7]
    DIRECTION OUTPUT ;
    USE SIGNAL ;
    PORT
      LAYER M3 ;
        RECT  9.18 25.882 9.198 25.92 ;
    END
    PORT
      LAYER M3 ;
        RECT  9.18 23.621 9.198 25.901 ;
    END
  END req_hi[7]
  PIN req_hi[8]
    DIRECTION OUTPUT ;
    USE SIGNAL ;
    PORT
      LAYER M5 ;
        RECT  10.128 25.836 10.152 25.92 ;
    END
    PORT
      LAYER M5 ;
        RECT  10.128 23.893 10.152 25.872 ;
    END
  END req_hi[8]
  PIN req_hi[9]
    DIRECTION OUTPUT ;
    USE SIGNAL ;
    PORT
      LAYER M3 ;
        RECT  11.088 25.882 11.106 25.92 ;
    END
    PORT
      LAYER M3 ;
        RECT  11.088 23.585 11.106 25.901 ;
    END
  END req_hi[9]
  PIN req_layer[0]
    DIRECTION INPUT ;
    USE SIGNAL ;
    PORT
      LAYER M4 ;
        RECT  0 6.48 0.084 6.504 ;
    END
  END req_layer[0]
  PIN req_layer[1]
    DIRECTION INPUT ;
    USE SIGNAL ;
    PORT
      LAYER M4 ;
        RECT  0 6.72 0.084 6.744 ;
    END
  END req_layer[1]
  PIN req_layer[2]
    DIRECTION INPUT ;
    USE SIGNAL ;
    PORT
      LAYER M4 ;
        RECT  0 6.96 0.084 6.984 ;
    END
  END req_layer[2]
  PIN req_layer[3]
    DIRECTION INPUT ;
    USE SIGNAL ;
    PORT
      LAYER M4 ;
        RECT  0 7.2 0.084 7.224 ;
    END
  END req_layer[3]
  PIN req_layer[4]
    DIRECTION INPUT ;
    USE SIGNAL ;
    PORT
      LAYER M4 ;
        RECT  0 7.44 0.084 7.464 ;
    END
  END req_layer[4]
  PIN req_layer[5]
    DIRECTION INPUT ;
    USE SIGNAL ;
    PORT
      LAYER M4 ;
        RECT  0 7.68 0.084 7.704 ;
    END
  END req_layer[5]
  PIN req_lo[0]
    DIRECTION OUTPUT ;
    USE SIGNAL ;
    PORT
      LAYER M3 ;
        RECT  22.608 0 22.626 0.038 ;
    END
    PORT
      LAYER M3 ;
        RECT  22.608 0.012 22.626 0.031 ;
    END
    PORT
      LAYER M3 ;
        RECT  22.608 0.031 22.734 0.059 ;
    END
  END req_lo[0]
  PIN req_lo[10]
    DIRECTION OUTPUT ;
    USE SIGNAL ;
    PORT
      LAYER M3 ;
        RECT  30.744 0 30.762 0.038 ;
    END
    PORT
      LAYER M3 ;
        RECT  30.744 0.012 30.762 0.091 ;
    END
  END req_lo[10]
  PIN req_lo[11]
    DIRECTION OUTPUT ;
    USE SIGNAL ;
    PORT
      LAYER M5 ;
        RECT  31.584 0 31.608 0.084 ;
    END
    PORT
      LAYER M5 ;
        RECT  31.584 0.016 31.608 0.131 ;
    END
  END req_lo[11]
  PIN req_lo[12]
    DIRECTION OUTPUT ;
    USE SIGNAL ;
    PORT
      LAYER M3 ;
        RECT  32.364 0 32.382 0.038 ;
    END
    PORT
      LAYER M3 ;
        RECT  32.364 0.012 32.382 2.191 ;
    END
  END req_lo[12]
  PIN req_lo[13]
    DIRECTION OUTPUT ;
    USE SIGNAL ;
    PORT
      LAYER M5 ;
        RECT  33.216 0 33.24 0.084 ;
    END
    PORT
      LAYER M5 ;
        RECT  33.216 0.016 33.24 0.131 ;
    END
  END req_lo[13]
  PIN req_lo[14]
    DIRECTION OUTPUT ;
    USE SIGNAL ;
    PORT
      LAYER M3 ;
        RECT  34.02 0 34.038 0.038 ;
    END
    PORT
      LAYER M3 ;
        RECT  34.02 0.012 34.038 2.191 ;
    END
  END req_lo[14]
  PIN req_lo[15]
    DIRECTION OUTPUT ;
    USE SIGNAL ;
    PORT
      LAYER M5 ;
        RECT  34.8 0 34.824 0.084 ;
    END
    PORT
      LAYER M5 ;
        RECT  34.8 0.016 34.824 2.137 ;
    END
  END req_lo[15]
  PIN req_lo[16]
    DIRECTION OUTPUT ;
    USE SIGNAL ;
    PORT
      LAYER M3 ;
        RECT  35.64 0 35.658 0.038 ;
    END
    PORT
      LAYER M3 ;
        RECT  35.64 0.012 35.658 1.723 ;
    END
  END req_lo[16]
  PIN req_lo[17]
    DIRECTION OUTPUT ;
    USE SIGNAL ;
    PORT
      LAYER M5 ;
        RECT  36.432 0 36.456 0.084 ;
    END
    PORT
      LAYER M5 ;
        RECT  36.432 0.016 36.456 0.131 ;
    END
  END req_lo[17]
  PIN req_lo[18]
    DIRECTION OUTPUT ;
    USE SIGNAL ;
    PORT
      LAYER M3 ;
        RECT  37.26 0 37.278 0.038 ;
    END
    PORT
      LAYER M3 ;
        RECT  37.26 0.012 37.278 2.191 ;
    END
  END req_lo[18]
  PIN req_lo[19]
    DIRECTION OUTPUT ;
    USE SIGNAL ;
    PORT
      LAYER M5 ;
        RECT  38.064 0 38.088 0.084 ;
    END
    PORT
      LAYER M5 ;
        RECT  38.064 0.016 38.088 0.131 ;
    END
  END req_lo[19]
  PIN req_lo[1]
    DIRECTION OUTPUT ;
    USE SIGNAL ;
    PORT
      LAYER M5 ;
        RECT  23.424 0 23.448 0.084 ;
    END
    PORT
      LAYER M5 ;
        RECT  23.424 0.016 23.448 0.131 ;
    END
  END req_lo[1]
  PIN req_lo[20]
    DIRECTION OUTPUT ;
    USE SIGNAL ;
    PORT
      LAYER M3 ;
        RECT  38.916 0 38.934 0.038 ;
    END
    PORT
      LAYER M3 ;
        RECT  38.916 0.012 38.934 2.101 ;
    END
  END req_lo[20]
  PIN req_lo[21]
    DIRECTION OUTPUT ;
    USE SIGNAL ;
    PORT
      LAYER M5 ;
        RECT  39.696 0 39.72 0.084 ;
    END
    PORT
      LAYER M5 ;
        RECT  39.696 0.016 39.72 0.131 ;
    END
  END req_lo[21]
  PIN req_lo[22]
    DIRECTION OUTPUT ;
    USE SIGNAL ;
    PORT
      LAYER M3 ;
        RECT  40.536 0 40.554 0.038 ;
    END
    PORT
      LAYER M3 ;
        RECT  40.536 0.012 40.554 2.143 ;
    END
  END req_lo[22]
  PIN req_lo[23]
    DIRECTION OUTPUT ;
    USE SIGNAL ;
    PORT
      LAYER M5 ;
        RECT  41.328 0 41.352 0.084 ;
    END
    PORT
      LAYER M5 ;
        RECT  41.328 0.016 41.352 2.151 ;
    END
  END req_lo[23]
  PIN req_lo[24]
    DIRECTION OUTPUT ;
    USE SIGNAL ;
    PORT
      LAYER M3 ;
        RECT  42.156 0 42.174 0.038 ;
    END
    PORT
      LAYER M3 ;
        RECT  42.156 0.012 42.174 1.723 ;
    END
  END req_lo[24]
  PIN req_lo[25]
    DIRECTION OUTPUT ;
    USE SIGNAL ;
    PORT
      LAYER M5 ;
        RECT  42.96 0 42.984 0.084 ;
    END
    PORT
      LAYER M5 ;
        RECT  42.96 0.016 42.984 2.339 ;
    END
  END req_lo[25]
  PIN req_lo[26]
    DIRECTION OUTPUT ;
    USE SIGNAL ;
    PORT
      LAYER M3 ;
        RECT  43.812 0 43.83 0.038 ;
    END
    PORT
      LAYER M3 ;
        RECT  43.812 0.012 43.83 2.191 ;
    END
  END req_lo[26]
  PIN req_lo[27]
    DIRECTION OUTPUT ;
    USE SIGNAL ;
    PORT
      LAYER M5 ;
        RECT  44.592 0 44.616 0.084 ;
    END
    PORT
      LAYER M5 ;
        RECT  44.592 0.016 44.616 2.339 ;
    END
  END req_lo[27]
  PIN req_lo[28]
    DIRECTION OUTPUT ;
    USE SIGNAL ;
    PORT
      LAYER M3 ;
        RECT  45.432 0 45.45 0.038 ;
    END
    PORT
      LAYER M3 ;
        RECT  45.432 0.012 45.45 2.143 ;
    END
  END req_lo[28]
  PIN req_lo[29]
    DIRECTION OUTPUT ;
    USE SIGNAL ;
    PORT
      LAYER M5 ;
        RECT  46.224 0 46.248 0.084 ;
    END
    PORT
      LAYER M5 ;
        RECT  46.224 0.016 46.248 2.137 ;
    END
  END req_lo[29]
  PIN req_lo[2]
    DIRECTION OUTPUT ;
    USE SIGNAL ;
    PORT
      LAYER M3 ;
        RECT  24.228 0 24.246 0.038 ;
    END
    PORT
      LAYER M3 ;
        RECT  24.228 0.012 24.246 0.091 ;
    END
  END req_lo[2]
  PIN req_lo[30]
    DIRECTION OUTPUT ;
    USE SIGNAL ;
    PORT
      LAYER M3 ;
        RECT  47.052 0 47.07 0.038 ;
    END
    PORT
      LAYER M3 ;
        RECT  47.052 0.012 47.07 2.191 ;
    END
  END req_lo[30]
  PIN req_lo[31]
    DIRECTION OUTPUT ;
    USE SIGNAL ;
    PORT
      LAYER M5 ;
        RECT  47.856 0 47.88 0.084 ;
    END
    PORT
      LAYER M5 ;
        RECT  47.856 0.016 47.88 0.611 ;
    END
  END req_lo[31]
  PIN req_lo[32]
    DIRECTION OUTPUT ;
    USE SIGNAL ;
    PORT
      LAYER M3 ;
        RECT  48.672 0 48.69 0.038 ;
    END
    PORT
      LAYER M3 ;
        RECT  48.672 0.012 48.69 2.065 ;
    END
  END req_lo[32]
  PIN req_lo[33]
    DIRECTION OUTPUT ;
    USE SIGNAL ;
    PORT
      LAYER M5 ;
        RECT  49.488 0 49.512 0.084 ;
    END
    PORT
      LAYER M5 ;
        RECT  49.488 0.016 49.512 1.763 ;
    END
  END req_lo[33]
  PIN req_lo[34]
    DIRECTION OUTPUT ;
    USE SIGNAL ;
    PORT
      LAYER M3 ;
        RECT  50.328 0 50.346 0.038 ;
    END
    PORT
      LAYER M3 ;
        RECT  50.328 0.012 50.346 0.031 ;
    END
    PORT
      LAYER M3 ;
        RECT  50.256 0.031 50.346 0.059 ;
    END
  END req_lo[34]
  PIN req_lo[35]
    DIRECTION OUTPUT ;
    USE SIGNAL ;
    PORT
      LAYER M5 ;
        RECT  51.12 0 51.144 0.084 ;
    END
    PORT
      LAYER M5 ;
        RECT  51.12 0.016 51.144 0.131 ;
    END
  END req_lo[35]
  PIN req_lo[36]
    DIRECTION OUTPUT ;
    USE SIGNAL ;
    PORT
      LAYER M3 ;
        RECT  51.948 0 51.966 0.038 ;
    END
    PORT
      LAYER M3 ;
        RECT  51.948 0.012 51.966 0.031 ;
    END
    PORT
      LAYER M3 ;
        RECT  51.948 0.031 52.038 0.059 ;
    END
  END req_lo[36]
  PIN req_lo[37]
    DIRECTION OUTPUT ;
    USE SIGNAL ;
    PORT
      LAYER M5 ;
        RECT  52.752 0 52.776 0.084 ;
    END
    PORT
      LAYER M5 ;
        RECT  52.752 0.016 52.776 0.131 ;
    END
  END req_lo[37]
  PIN req_lo[38]
    DIRECTION OUTPUT ;
    USE SIGNAL ;
    PORT
      LAYER M3 ;
        RECT  53.568 0 53.586 0.038 ;
    END
    PORT
      LAYER M3 ;
        RECT  53.568 0.012 53.586 2.191 ;
    END
  END req_lo[38]
  PIN req_lo[39]
    DIRECTION OUTPUT ;
    USE SIGNAL ;
    PORT
      LAYER M5 ;
        RECT  54.384 0 54.408 0.084 ;
    END
    PORT
      LAYER M5 ;
        RECT  54.384 0.016 54.408 0.131 ;
    END
  END req_lo[39]
  PIN req_lo[3]
    DIRECTION OUTPUT ;
    USE SIGNAL ;
    PORT
      LAYER M5 ;
        RECT  25.056 0 25.08 0.084 ;
    END
    PORT
      LAYER M5 ;
        RECT  25.056 0.016 25.08 1.763 ;
    END
  END req_lo[3]
  PIN req_lo[40]
    DIRECTION OUTPUT ;
    USE SIGNAL ;
    PORT
      LAYER M3 ;
        RECT  55.224 0 55.242 0.038 ;
    END
    PORT
      LAYER M3 ;
        RECT  55.224 0.012 55.242 0.091 ;
    END
  END req_lo[40]
  PIN req_lo[41]
    DIRECTION OUTPUT ;
    USE SIGNAL ;
    PORT
      LAYER M5 ;
        RECT  56.016 0 56.04 0.084 ;
    END
    PORT
      LAYER M5 ;
        RECT  56.016 0.016 56.04 0.131 ;
    END
  END req_lo[41]
  PIN req_lo[42]
    DIRECTION OUTPUT ;
    USE SIGNAL ;
    PORT
      LAYER M3 ;
        RECT  56.844 0 56.862 0.038 ;
    END
    PORT
      LAYER M3 ;
        RECT  56.844 0.012 56.862 2.101 ;
    END
  END req_lo[42]
  PIN req_lo[43]
    DIRECTION OUTPUT ;
    USE SIGNAL ;
    PORT
      LAYER M5 ;
        RECT  57.648 0 57.672 0.084 ;
    END
    PORT
      LAYER M5 ;
        RECT  57.648 0.016 57.672 0.131 ;
    END
  END req_lo[43]
  PIN req_lo[44]
    DIRECTION OUTPUT ;
    USE SIGNAL ;
    PORT
      LAYER M3 ;
        RECT  58.464 0 58.482 0.038 ;
    END
    PORT
      LAYER M3 ;
        RECT  58.464 0.012 58.482 1.723 ;
    END
  END req_lo[44]
  PIN req_lo[45]
    DIRECTION OUTPUT ;
    USE SIGNAL ;
    PORT
      LAYER M5 ;
        RECT  59.28 0 59.304 0.084 ;
    END
    PORT
      LAYER M5 ;
        RECT  59.28 0.016 59.304 0.131 ;
    END
  END req_lo[45]
  PIN req_lo[46]
    DIRECTION OUTPUT ;
    USE SIGNAL ;
    PORT
      LAYER M3 ;
        RECT  60.084 0 60.102 0.038 ;
    END
    PORT
      LAYER M3 ;
        RECT  60.084 0.012 60.102 2.191 ;
    END
  END req_lo[46]
  PIN req_lo[47]
    DIRECTION OUTPUT ;
    USE SIGNAL ;
    PORT
      LAYER M5 ;
        RECT  60.912 0 60.936 0.084 ;
    END
    PORT
      LAYER M5 ;
        RECT  60.912 0.016 60.936 1.763 ;
    END
  END req_lo[47]
  PIN req_lo[48]
    DIRECTION OUTPUT ;
    USE SIGNAL ;
    PORT
      LAYER M3 ;
        RECT  61.74 0 61.758 0.038 ;
    END
    PORT
      LAYER M3 ;
        RECT  61.74 0.012 61.758 2.143 ;
    END
  END req_lo[48]
  PIN req_lo[49]
    DIRECTION OUTPUT ;
    USE SIGNAL ;
    PORT
      LAYER M5 ;
        RECT  62.544 0 62.568 0.084 ;
    END
    PORT
      LAYER M5 ;
        RECT  62.544 0.016 62.568 0.131 ;
    END
  END req_lo[49]
  PIN req_lo[4]
    DIRECTION OUTPUT ;
    USE SIGNAL ;
    PORT
      LAYER M3 ;
        RECT  25.848 0 25.866 0.038 ;
    END
    PORT
      LAYER M3 ;
        RECT  25.848 0.012 25.866 2.263 ;
    END
  END req_lo[4]
  PIN req_lo[50]
    DIRECTION OUTPUT ;
    USE SIGNAL ;
    PORT
      LAYER M3 ;
        RECT  63.36 0 63.378 0.038 ;
    END
    PORT
      LAYER M3 ;
        RECT  63.36 0.012 63.378 2.227 ;
    END
  END req_lo[50]
  PIN req_lo[51]
    DIRECTION OUTPUT ;
    USE SIGNAL ;
    PORT
      LAYER M5 ;
        RECT  64.176 0 64.2 0.084 ;
    END
    PORT
      LAYER M5 ;
        RECT  64.176 0.016 64.2 0.131 ;
    END
  END req_lo[51]
  PIN req_lo[52]
    DIRECTION OUTPUT ;
    USE SIGNAL ;
    PORT
      LAYER M3 ;
        RECT  64.98 0 64.998 0.038 ;
    END
    PORT
      LAYER M3 ;
        RECT  64.98 0.012 64.998 0.031 ;
    END
    PORT
      LAYER M3 ;
        RECT  64.98 0.031 65.106 0.059 ;
    END
  END req_lo[52]
  PIN req_lo[53]
    DIRECTION OUTPUT ;
    USE SIGNAL ;
    PORT
      LAYER M5 ;
        RECT  65.808 0 65.832 0.084 ;
    END
    PORT
      LAYER M5 ;
        RECT  65.808 0.016 65.832 0.131 ;
    END
  END req_lo[53]
  PIN req_lo[54]
    DIRECTION OUTPUT ;
    USE SIGNAL ;
    PORT
      LAYER M3 ;
        RECT  66.636 0 66.654 0.038 ;
    END
    PORT
      LAYER M3 ;
        RECT  66.636 0.012 66.654 2.143 ;
    END
  END req_lo[54]
  PIN req_lo[55]
    DIRECTION OUTPUT ;
    USE SIGNAL ;
    PORT
      LAYER M5 ;
        RECT  67.44 0 67.464 0.084 ;
    END
    PORT
      LAYER M5 ;
        RECT  67.44 0.016 67.464 2.137 ;
    END
  END req_lo[55]
  PIN req_lo[56]
    DIRECTION OUTPUT ;
    USE SIGNAL ;
    PORT
      LAYER M3 ;
        RECT  68.256 0 68.274 0.038 ;
    END
    PORT
      LAYER M3 ;
        RECT  68.256 0.012 68.274 0.091 ;
    END
  END req_lo[56]
  PIN req_lo[57]
    DIRECTION OUTPUT ;
    USE SIGNAL ;
    PORT
      LAYER M5 ;
        RECT  69.072 0 69.096 0.084 ;
    END
    PORT
      LAYER M5 ;
        RECT  69.072 0.016 69.096 0.131 ;
    END
  END req_lo[57]
  PIN req_lo[58]
    DIRECTION OUTPUT ;
    USE SIGNAL ;
    PORT
      LAYER M3 ;
        RECT  69.876 0 69.894 0.038 ;
    END
    PORT
      LAYER M3 ;
        RECT  69.876 0.012 69.894 2.191 ;
    END
  END req_lo[58]
  PIN req_lo[59]
    DIRECTION OUTPUT ;
    USE SIGNAL ;
    PORT
      LAYER M5 ;
        RECT  70.704 0 70.728 0.084 ;
    END
    PORT
      LAYER M5 ;
        RECT  70.704 0.016 70.728 1.763 ;
    END
  END req_lo[59]
  PIN req_lo[5]
    DIRECTION OUTPUT ;
    USE SIGNAL ;
    PORT
      LAYER M5 ;
        RECT  26.688 0 26.712 0.084 ;
    END
    PORT
      LAYER M5 ;
        RECT  26.688 0.016 26.712 0.131 ;
    END
  END req_lo[5]
  PIN req_lo[60]
    DIRECTION OUTPUT ;
    USE SIGNAL ;
    PORT
      LAYER M3 ;
        RECT  71.532 0 71.55 0.038 ;
    END
    PORT
      LAYER M3 ;
        RECT  71.532 0.012 71.55 1.723 ;
    END
  END req_lo[60]
  PIN req_lo[61]
    DIRECTION OUTPUT ;
    USE SIGNAL ;
    PORT
      LAYER M5 ;
        RECT  72.336 0 72.36 0.084 ;
    END
    PORT
      LAYER M5 ;
        RECT  72.336 0.016 72.36 1.763 ;
    END
  END req_lo[61]
  PIN req_lo[62]
    DIRECTION OUTPUT ;
    USE SIGNAL ;
    PORT
      LAYER M3 ;
        RECT  73.152 0 73.17 0.038 ;
    END
    PORT
      LAYER M3 ;
        RECT  73.152 0.012 73.17 2.143 ;
    END
  END req_lo[62]
  PIN req_lo[63]
    DIRECTION OUTPUT ;
    USE SIGNAL ;
    PORT
      LAYER M5 ;
        RECT  73.968 0 73.992 0.084 ;
    END
    PORT
      LAYER M5 ;
        RECT  73.968 0.016 73.992 0.131 ;
    END
  END req_lo[63]
  PIN req_lo[64]
    DIRECTION OUTPUT ;
    USE SIGNAL ;
    PORT
      LAYER M3 ;
        RECT  74.772 0 74.79 0.038 ;
    END
    PORT
      LAYER M3 ;
        RECT  74.772 0.012 74.79 2.191 ;
    END
  END req_lo[64]
  PIN req_lo[65]
    DIRECTION OUTPUT ;
    USE SIGNAL ;
    PORT
      LAYER M5 ;
        RECT  75.6 0 75.624 0.084 ;
    END
    PORT
      LAYER M5 ;
        RECT  75.6 0.016 75.624 0.131 ;
    END
  END req_lo[65]
  PIN req_lo[66]
    DIRECTION OUTPUT ;
    USE SIGNAL ;
    PORT
      LAYER M3 ;
        RECT  76.392 0 76.41 0.038 ;
    END
    PORT
      LAYER M3 ;
        RECT  76.392 0.012 76.41 2.101 ;
    END
  END req_lo[66]
  PIN req_lo[67]
    DIRECTION OUTPUT ;
    USE SIGNAL ;
    PORT
      LAYER M5 ;
        RECT  77.232 0 77.256 0.084 ;
    END
    PORT
      LAYER M5 ;
        RECT  77.232 0.016 77.256 1.763 ;
    END
  END req_lo[67]
  PIN req_lo[68]
    DIRECTION OUTPUT ;
    USE SIGNAL ;
    PORT
      LAYER M3 ;
        RECT  78.048 0 78.066 0.038 ;
    END
    PORT
      LAYER M3 ;
        RECT  78.048 0.012 78.066 0.031 ;
    END
    PORT
      LAYER M3 ;
        RECT  77.976 0.031 78.066 0.059 ;
    END
  END req_lo[68]
  PIN req_lo[69]
    DIRECTION OUTPUT ;
    USE SIGNAL ;
    PORT
      LAYER M5 ;
        RECT  78.864 0 78.888 0.084 ;
    END
    PORT
      LAYER M5 ;
        RECT  78.864 0.016 78.888 0.131 ;
    END
  END req_lo[69]
  PIN req_lo[6]
    DIRECTION OUTPUT ;
    USE SIGNAL ;
    PORT
      LAYER M3 ;
        RECT  27.504 0 27.522 0.038 ;
    END
    PORT
      LAYER M3 ;
        RECT  27.504 0.012 27.522 2.263 ;
    END
  END req_lo[6]
  PIN req_lo[70]
    DIRECTION OUTPUT ;
    USE SIGNAL ;
    PORT
      LAYER M3 ;
        RECT  79.668 0 79.686 0.038 ;
    END
    PORT
      LAYER M3 ;
        RECT  79.668 0.012 79.686 2.191 ;
    END
  END req_lo[70]
  PIN req_lo[71]
    DIRECTION OUTPUT ;
    USE SIGNAL ;
    PORT
      LAYER M5 ;
        RECT  80.496 0 80.52 0.084 ;
    END
    PORT
      LAYER M5 ;
        RECT  80.496 0.016 80.52 0.131 ;
    END
  END req_lo[71]
  PIN req_lo[72]
    DIRECTION OUTPUT ;
    USE SIGNAL ;
    PORT
      LAYER M3 ;
        RECT  81.288 0 81.306 0.038 ;
    END
    PORT
      LAYER M3 ;
        RECT  81.288 0.012 81.306 0.091 ;
    END
  END req_lo[72]
  PIN req_lo[73]
    DIRECTION OUTPUT ;
    USE SIGNAL ;
    PORT
      LAYER M5 ;
        RECT  82.128 0 82.152 0.084 ;
    END
    PORT
      LAYER M5 ;
        RECT  82.128 0.016 82.152 0.131 ;
    END
  END req_lo[73]
  PIN req_lo[74]
    DIRECTION OUTPUT ;
    USE SIGNAL ;
    PORT
      LAYER M3 ;
        RECT  82.944 0 82.962 0.038 ;
    END
    PORT
      LAYER M3 ;
        RECT  82.944 0.012 82.962 2.143 ;
    END
  END req_lo[74]
  PIN req_lo[75]
    DIRECTION OUTPUT ;
    USE SIGNAL ;
    PORT
      LAYER M5 ;
        RECT  83.76 0 83.784 0.084 ;
    END
    PORT
      LAYER M5 ;
        RECT  83.76 0.016 83.784 1.763 ;
    END
  END req_lo[75]
  PIN req_lo[7]
    DIRECTION OUTPUT ;
    USE SIGNAL ;
    PORT
      LAYER M5 ;
        RECT  28.32 0 28.344 0.084 ;
    END
    PORT
      LAYER M5 ;
        RECT  28.32 0.016 28.344 1.763 ;
    END
  END req_lo[7]
  PIN req_lo[8]
    DIRECTION OUTPUT ;
    USE SIGNAL ;
    PORT
      LAYER M3 ;
        RECT  29.124 0 29.142 0.038 ;
    END
    PORT
      LAYER M3 ;
        RECT  29.124 0.012 29.142 2.143 ;
    END
  END req_lo[8]
  PIN req_lo[9]
    DIRECTION OUTPUT ;
    USE SIGNAL ;
    PORT
      LAYER M5 ;
        RECT  29.952 0 29.976 0.084 ;
    END
    PORT
      LAYER M5 ;
        RECT  29.952 0.016 29.976 0.131 ;
    END
  END req_lo[9]
  PIN req_t[0]
    DIRECTION INPUT ;
    USE SIGNAL ;
    PORT
      LAYER M4 ;
        RECT  0 7.968 0.084 7.992 ;
    END
  END req_t[0]
  PIN req_t[10]
    DIRECTION INPUT ;
    USE SIGNAL ;
    PORT
      LAYER M4 ;
        RECT  0 10.368 0.084 10.392 ;
    END
  END req_t[10]
  PIN req_t[11]
    DIRECTION INPUT ;
    USE SIGNAL ;
    PORT
      LAYER M4 ;
        RECT  0 10.608 0.084 10.632 ;
    END
  END req_t[11]
  PIN req_t[12]
    DIRECTION INPUT ;
    USE SIGNAL ;
    PORT
      LAYER M4 ;
        RECT  0 10.896 0.084 10.92 ;
    END
  END req_t[12]
  PIN req_t[13]
    DIRECTION INPUT ;
    USE SIGNAL ;
    PORT
      LAYER M4 ;
        RECT  0 11.136 0.084 11.16 ;
    END
  END req_t[13]
  PIN req_t[1]
    DIRECTION INPUT ;
    USE SIGNAL ;
    PORT
      LAYER M4 ;
        RECT  0 8.208 0.084 8.232 ;
    END
  END req_t[1]
  PIN req_t[2]
    DIRECTION INPUT ;
    USE SIGNAL ;
    PORT
      LAYER M4 ;
        RECT  0 8.448 0.084 8.472 ;
    END
  END req_t[2]
  PIN req_t[3]
    DIRECTION INPUT ;
    USE SIGNAL ;
    PORT
      LAYER M4 ;
        RECT  0 8.688 0.084 8.712 ;
    END
  END req_t[3]
  PIN req_t[4]
    DIRECTION INPUT ;
    USE SIGNAL ;
    PORT
      LAYER M4 ;
        RECT  0 8.928 0.084 8.952 ;
    END
  END req_t[4]
  PIN req_t[5]
    DIRECTION INPUT ;
    USE SIGNAL ;
    PORT
      LAYER M4 ;
        RECT  0 9.168 0.084 9.192 ;
    END
  END req_t[5]
  PIN req_t[6]
    DIRECTION INPUT ;
    USE SIGNAL ;
    PORT
      LAYER M4 ;
        RECT  0 9.408 0.084 9.432 ;
    END
  END req_t[6]
  PIN req_t[7]
    DIRECTION INPUT ;
    USE SIGNAL ;
    PORT
      LAYER M4 ;
        RECT  0 9.648 0.084 9.672 ;
    END
  END req_t[7]
  PIN req_t[8]
    DIRECTION INPUT ;
    USE SIGNAL ;
    PORT
      LAYER M4 ;
        RECT  0 9.888 0.084 9.912 ;
    END
  END req_t[8]
  PIN req_t[9]
    DIRECTION INPUT ;
    USE SIGNAL ;
    PORT
      LAYER M4 ;
        RECT  0 10.128 0.084 10.152 ;
    END
  END req_t[9]
  PIN req_v
    DIRECTION INPUT ;
    USE SIGNAL ;
    PORT
      LAYER M4 ;
        RECT  0 11.376 0.084 11.4 ;
    END
  END req_v
  PIN req_valid
    DIRECTION INPUT ;
    USE SIGNAL ;
    PORT
      LAYER M4 ;
        RECT  0 11.616 0.084 11.64 ;
    END
  END req_valid
  PIN rsp_epoch[0]
    DIRECTION OUTPUT ;
    USE SIGNAL ;
    PORT
      LAYER M4 ;
        RECT  0 11.856 0.084 11.88 ;
    END
  END rsp_epoch[0]
  PIN rsp_epoch[10]
    DIRECTION OUTPUT ;
    USE SIGNAL ;
    PORT
      LAYER M4 ;
        RECT  0 14.304 0.084 14.328 ;
    END
  END rsp_epoch[10]
  PIN rsp_epoch[11]
    DIRECTION OUTPUT ;
    USE SIGNAL ;
    PORT
      LAYER M4 ;
        RECT  0 14.544 0.084 14.568 ;
    END
  END rsp_epoch[11]
  PIN rsp_epoch[12]
    DIRECTION OUTPUT ;
    USE SIGNAL ;
    PORT
      LAYER M4 ;
        RECT  0 14.784 0.084 14.808 ;
    END
  END rsp_epoch[12]
  PIN rsp_epoch[13]
    DIRECTION OUTPUT ;
    USE SIGNAL ;
    PORT
      LAYER M4 ;
        RECT  0 15.024 0.084 15.048 ;
    END
  END rsp_epoch[13]
  PIN rsp_epoch[14]
    DIRECTION OUTPUT ;
    USE SIGNAL ;
    PORT
      LAYER M4 ;
        RECT  0 15.264 0.084 15.288 ;
    END
  END rsp_epoch[14]
  PIN rsp_epoch[15]
    DIRECTION OUTPUT ;
    USE SIGNAL ;
    PORT
      LAYER M4 ;
        RECT  0 15.504 0.084 15.528 ;
    END
  END rsp_epoch[15]
  PIN rsp_epoch[1]
    DIRECTION OUTPUT ;
    USE SIGNAL ;
    PORT
      LAYER M4 ;
        RECT  0 12.096 0.084 12.12 ;
    END
  END rsp_epoch[1]
  PIN rsp_epoch[2]
    DIRECTION OUTPUT ;
    USE SIGNAL ;
    PORT
      LAYER M4 ;
        RECT  0 12.336 0.084 12.36 ;
    END
  END rsp_epoch[2]
  PIN rsp_epoch[3]
    DIRECTION OUTPUT ;
    USE SIGNAL ;
    PORT
      LAYER M4 ;
        RECT  0 12.576 0.084 12.6 ;
    END
  END rsp_epoch[3]
  PIN rsp_epoch[4]
    DIRECTION OUTPUT ;
    USE SIGNAL ;
    PORT
      LAYER M4 ;
        RECT  0 12.816 0.084 12.84 ;
    END
  END rsp_epoch[4]
  PIN rsp_epoch[5]
    DIRECTION OUTPUT ;
    USE SIGNAL ;
    PORT
      LAYER M4 ;
        RECT  0 13.056 0.084 13.08 ;
    END
  END rsp_epoch[5]
  PIN rsp_epoch[6]
    DIRECTION OUTPUT ;
    USE SIGNAL ;
    PORT
      LAYER M4 ;
        RECT  0 13.296 0.084 13.32 ;
    END
  END rsp_epoch[6]
  PIN rsp_epoch[7]
    DIRECTION OUTPUT ;
    USE SIGNAL ;
    PORT
      LAYER M4 ;
        RECT  0 13.536 0.084 13.56 ;
    END
  END rsp_epoch[7]
  PIN rsp_epoch[8]
    DIRECTION OUTPUT ;
    USE SIGNAL ;
    PORT
      LAYER M4 ;
        RECT  0 13.824 0.084 13.848 ;
    END
  END rsp_epoch[8]
  PIN rsp_epoch[9]
    DIRECTION OUTPUT ;
    USE SIGNAL ;
    PORT
      LAYER M4 ;
        RECT  0 14.064 0.084 14.088 ;
    END
  END rsp_epoch[9]
  PIN rsp_hi[0]
    DIRECTION INPUT ;
    USE SIGNAL ;
    PORT
      LAYER M5 ;
        RECT  75.6 25.836 75.624 25.92 ;
    END
    PORT
      LAYER M5 ;
        RECT  75.6 23.701 75.624 25.872 ;
    END
  END rsp_hi[0]
  PIN rsp_hi[10]
    DIRECTION INPUT ;
    USE SIGNAL ;
    PORT
      LAYER M5 ;
        RECT  85.2 25.836 85.224 25.92 ;
    END
    PORT
      LAYER M5 ;
        RECT  85.2 23.701 85.224 25.872 ;
    END
  END rsp_hi[10]
  PIN rsp_hi[11]
    DIRECTION INPUT ;
    USE SIGNAL ;
    PORT
      LAYER M3 ;
        RECT  86.184 25.882 86.202 25.92 ;
    END
    PORT
      LAYER M3 ;
        RECT  86.184 23.741 86.202 25.901 ;
    END
  END rsp_hi[11]
  PIN rsp_hi[12]
    DIRECTION INPUT ;
    USE SIGNAL ;
    PORT
      LAYER M5 ;
        RECT  87.12 25.836 87.144 25.92 ;
    END
    PORT
      LAYER M5 ;
        RECT  87.12 23.701 87.144 25.872 ;
    END
  END rsp_hi[12]
  PIN rsp_hi[13]
    DIRECTION INPUT ;
    USE SIGNAL ;
    PORT
      LAYER M3 ;
        RECT  88.092 25.882 88.11 25.92 ;
    END
    PORT
      LAYER M3 ;
        RECT  88.092 25.133 88.11 25.901 ;
    END
  END rsp_hi[13]
  PIN rsp_hi[14]
    DIRECTION INPUT ;
    USE SIGNAL ;
    PORT
      LAYER M5 ;
        RECT  89.088 25.836 89.112 25.92 ;
    END
    PORT
      LAYER M5 ;
        RECT  89.088 25.093 89.112 25.872 ;
    END
  END rsp_hi[14]
  PIN rsp_hi[15]
    DIRECTION INPUT ;
    USE SIGNAL ;
    PORT
      LAYER M3 ;
        RECT  90.036 25.882 90.054 25.92 ;
    END
    PORT
      LAYER M3 ;
        RECT  90.036 23.279 90.054 25.901 ;
    END
  END rsp_hi[15]
  PIN rsp_hi[16]
    DIRECTION INPUT ;
    USE SIGNAL ;
    PORT
      LAYER M5 ;
        RECT  91.008 25.836 91.032 25.92 ;
    END
    PORT
      LAYER M5 ;
        RECT  91.008 23.701 91.032 25.872 ;
    END
  END rsp_hi[16]
  PIN rsp_hi[17]
    DIRECTION INPUT ;
    USE SIGNAL ;
    PORT
      LAYER M3 ;
        RECT  91.944 25.882 91.962 25.92 ;
    END
    PORT
      LAYER M3 ;
        RECT  91.944 23.585 91.962 25.901 ;
    END
  END rsp_hi[17]
  PIN rsp_hi[18]
    DIRECTION INPUT ;
    USE SIGNAL ;
    PORT
      LAYER M5 ;
        RECT  92.928 25.836 92.952 25.92 ;
    END
    PORT
      LAYER M5 ;
        RECT  92.928 25.765 92.952 25.872 ;
    END
  END rsp_hi[18]
  PIN rsp_hi[19]
    DIRECTION INPUT ;
    USE SIGNAL ;
    PORT
      LAYER M3 ;
        RECT  93.888 25.882 93.906 25.92 ;
    END
    PORT
      LAYER M3 ;
        RECT  93.888 23.777 93.906 25.901 ;
    END
  END rsp_hi[19]
  PIN rsp_hi[1]
    DIRECTION INPUT ;
    USE SIGNAL ;
    PORT
      LAYER M3 ;
        RECT  76.572 25.882 76.59 25.92 ;
    END
    PORT
      LAYER M3 ;
        RECT  76.572 25.133 76.59 25.901 ;
    END
  END rsp_hi[1]
  PIN rsp_hi[20]
    DIRECTION INPUT ;
    USE SIGNAL ;
    PORT
      LAYER M5 ;
        RECT  94.848 25.836 94.872 25.92 ;
    END
    PORT
      LAYER M5 ;
        RECT  94.848 23.893 94.872 25.872 ;
    END
  END rsp_hi[20]
  PIN rsp_hi[21]
    DIRECTION INPUT ;
    USE SIGNAL ;
    PORT
      LAYER M3 ;
        RECT  95.796 25.882 95.814 25.92 ;
    END
    PORT
      LAYER M3 ;
        RECT  95.796 23.741 95.814 25.901 ;
    END
  END rsp_hi[21]
  PIN rsp_hi[22]
    DIRECTION INPUT ;
    USE SIGNAL ;
    PORT
      LAYER M5 ;
        RECT  96.768 25.836 96.792 25.92 ;
    END
    PORT
      LAYER M5 ;
        RECT  96.768 23.701 96.792 25.872 ;
    END
  END rsp_hi[22]
  PIN rsp_hi[23]
    DIRECTION INPUT ;
    USE SIGNAL ;
    PORT
      LAYER M3 ;
        RECT  97.74 25.882 97.758 25.92 ;
    END
    PORT
      LAYER M3 ;
        RECT  97.74 25.133 97.758 25.901 ;
    END
  END rsp_hi[23]
  PIN rsp_hi[24]
    DIRECTION INPUT ;
    USE SIGNAL ;
    PORT
      LAYER M5 ;
        RECT  98.688 25.836 98.712 25.92 ;
    END
    PORT
      LAYER M5 ;
        RECT  98.688 25.093 98.712 25.872 ;
    END
  END rsp_hi[24]
  PIN rsp_hi[25]
    DIRECTION INPUT ;
    USE SIGNAL ;
    PORT
      LAYER M3 ;
        RECT  99.648 25.882 99.666 25.92 ;
    END
    PORT
      LAYER M3 ;
        RECT  99.648 23.933 99.666 25.901 ;
    END
  END rsp_hi[25]
  PIN rsp_hi[26]
    DIRECTION INPUT ;
    USE SIGNAL ;
    PORT
      LAYER M5 ;
        RECT  100.608 25.836 100.632 25.92 ;
    END
    PORT
      LAYER M5 ;
        RECT  100.608 23.893 100.632 25.872 ;
    END
  END rsp_hi[26]
  PIN rsp_hi[27]
    DIRECTION INPUT ;
    USE SIGNAL ;
    PORT
      LAYER M3 ;
        RECT  101.592 25.882 101.61 25.92 ;
    END
    PORT
      LAYER M3 ;
        RECT  101.592 23.933 101.61 25.901 ;
    END
  END rsp_hi[27]
  PIN rsp_hi[28]
    DIRECTION INPUT ;
    USE SIGNAL ;
    PORT
      LAYER M5 ;
        RECT  102.528 25.836 102.552 25.92 ;
    END
    PORT
      LAYER M5 ;
        RECT  102.528 23.893 102.552 25.872 ;
    END
  END rsp_hi[28]
  PIN rsp_hi[29]
    DIRECTION INPUT ;
    USE SIGNAL ;
    PORT
      LAYER M3 ;
        RECT  103.5 25.882 103.518 25.92 ;
    END
    PORT
      LAYER M3 ;
        RECT  103.5 25.133 103.518 25.901 ;
    END
  END rsp_hi[29]
  PIN rsp_hi[2]
    DIRECTION INPUT ;
    USE SIGNAL ;
    PORT
      LAYER M5 ;
        RECT  77.52 25.836 77.544 25.92 ;
    END
    PORT
      LAYER M5 ;
        RECT  77.52 25.093 77.544 25.872 ;
    END
  END rsp_hi[2]
  PIN rsp_hi[30]
    DIRECTION INPUT ;
    USE SIGNAL ;
    PORT
      LAYER M5 ;
        RECT  104.448 25.836 104.472 25.92 ;
    END
    PORT
      LAYER M5 ;
        RECT  104.448 25.093 104.472 25.872 ;
    END
  END rsp_hi[30]
  PIN rsp_hi[31]
    DIRECTION INPUT ;
    USE SIGNAL ;
    PORT
      LAYER M3 ;
        RECT  105.444 25.882 105.462 25.92 ;
    END
    PORT
      LAYER M3 ;
        RECT  105.444 23.777 105.462 25.901 ;
    END
  END rsp_hi[31]
  PIN rsp_hi[32]
    DIRECTION INPUT ;
    USE SIGNAL ;
    PORT
      LAYER M5 ;
        RECT  106.368 25.836 106.392 25.92 ;
    END
    PORT
      LAYER M5 ;
        RECT  106.368 23.701 106.392 25.872 ;
    END
  END rsp_hi[32]
  PIN rsp_hi[33]
    DIRECTION INPUT ;
    USE SIGNAL ;
    PORT
      LAYER M3 ;
        RECT  107.352 25.882 107.37 25.92 ;
    END
    PORT
      LAYER M3 ;
        RECT  107.352 25.133 107.37 25.901 ;
    END
  END rsp_hi[33]
  PIN rsp_hi[34]
    DIRECTION INPUT ;
    USE SIGNAL ;
    PORT
      LAYER M5 ;
        RECT  108.336 25.836 108.36 25.92 ;
    END
    PORT
      LAYER M5 ;
        RECT  108.336 25.093 108.36 25.872 ;
    END
  END rsp_hi[34]
  PIN rsp_hi[35]
    DIRECTION INPUT ;
    USE SIGNAL ;
    PORT
      LAYER M3 ;
        RECT  109.296 25.882 109.314 25.92 ;
    END
    PORT
      LAYER M3 ;
        RECT  109.296 23.741 109.314 25.901 ;
    END
  END rsp_hi[35]
  PIN rsp_hi[36]
    DIRECTION INPUT ;
    USE SIGNAL ;
    PORT
      LAYER M5 ;
        RECT  110.256 25.836 110.28 25.92 ;
    END
    PORT
      LAYER M5 ;
        RECT  110.256 23.783 110.28 25.872 ;
    END
  END rsp_hi[36]
  PIN rsp_hi[37]
    DIRECTION INPUT ;
    USE SIGNAL ;
    PORT
      LAYER M3 ;
        RECT  111.204 25.882 111.222 25.92 ;
    END
    PORT
      LAYER M3 ;
        RECT  111.204 23.777 111.222 25.901 ;
    END
  END rsp_hi[37]
  PIN rsp_hi[38]
    DIRECTION INPUT ;
    USE SIGNAL ;
    PORT
      LAYER M5 ;
        RECT  112.176 25.836 112.2 25.92 ;
    END
    PORT
      LAYER M5 ;
        RECT  112.176 23.701 112.2 25.872 ;
    END
  END rsp_hi[38]
  PIN rsp_hi[39]
    DIRECTION INPUT ;
    USE SIGNAL ;
    PORT
      LAYER M3 ;
        RECT  113.148 25.882 113.166 25.92 ;
    END
    PORT
      LAYER M3 ;
        RECT  113.148 25.805 113.166 25.901 ;
    END
  END rsp_hi[39]
  PIN rsp_hi[3]
    DIRECTION INPUT ;
    USE SIGNAL ;
    PORT
      LAYER M3 ;
        RECT  78.48 25.882 78.498 25.92 ;
    END
    PORT
      LAYER M3 ;
        RECT  78.48 25.805 78.498 25.901 ;
    END
  END rsp_hi[3]
  PIN rsp_hi[40]
    DIRECTION INPUT ;
    USE SIGNAL ;
    PORT
      LAYER M5 ;
        RECT  114.096 25.836 114.12 25.92 ;
    END
    PORT
      LAYER M5 ;
        RECT  114.096 25.765 114.12 25.872 ;
    END
  END rsp_hi[40]
  PIN rsp_hi[41]
    DIRECTION INPUT ;
    USE SIGNAL ;
    PORT
      LAYER M3 ;
        RECT  115.056 25.882 115.074 25.92 ;
    END
    PORT
      LAYER M3 ;
        RECT  115.056 23.549 115.074 25.901 ;
    END
  END rsp_hi[41]
  PIN rsp_hi[42]
    DIRECTION INPUT ;
    USE SIGNAL ;
    PORT
      LAYER M5 ;
        RECT  116.016 25.836 116.04 25.92 ;
    END
    PORT
      LAYER M5 ;
        RECT  116.016 23.783 116.04 25.872 ;
    END
  END rsp_hi[42]
  PIN rsp_hi[43]
    DIRECTION INPUT ;
    USE SIGNAL ;
    PORT
      LAYER M3 ;
        RECT  117 25.882 117.018 25.92 ;
    END
    PORT
      LAYER M3 ;
        RECT  117 23.933 117.018 25.901 ;
    END
  END rsp_hi[43]
  PIN rsp_hi[44]
    DIRECTION INPUT ;
    USE SIGNAL ;
    PORT
      LAYER M5 ;
        RECT  117.936 25.836 117.96 25.92 ;
    END
    PORT
      LAYER M5 ;
        RECT  117.936 23.893 117.96 25.872 ;
    END
  END rsp_hi[44]
  PIN rsp_hi[45]
    DIRECTION INPUT ;
    USE SIGNAL ;
    PORT
      LAYER M3 ;
        RECT  118.908 25.882 118.926 25.92 ;
    END
    PORT
      LAYER M3 ;
        RECT  118.908 25.133 118.926 25.901 ;
    END
  END rsp_hi[45]
  PIN rsp_hi[46]
    DIRECTION INPUT ;
    USE SIGNAL ;
    PORT
      LAYER M5 ;
        RECT  119.856 25.836 119.88 25.92 ;
    END
    PORT
      LAYER M5 ;
        RECT  119.856 25.093 119.88 25.872 ;
    END
  END rsp_hi[46]
  PIN rsp_hi[47]
    DIRECTION INPUT ;
    USE SIGNAL ;
    PORT
      LAYER M3 ;
        RECT  120.816 25.882 120.834 25.92 ;
    END
    PORT
      LAYER M3 ;
        RECT  120.816 23.933 120.834 25.901 ;
    END
  END rsp_hi[47]
  PIN rsp_hi[48]
    DIRECTION INPUT ;
    USE SIGNAL ;
    PORT
      LAYER M5 ;
        RECT  121.776 25.836 121.8 25.92 ;
    END
    PORT
      LAYER M5 ;
        RECT  121.776 23.893 121.8 25.872 ;
    END
  END rsp_hi[48]
  PIN rsp_hi[49]
    DIRECTION INPUT ;
    USE SIGNAL ;
    PORT
      LAYER M3 ;
        RECT  122.76 25.882 122.778 25.92 ;
    END
    PORT
      LAYER M3 ;
        RECT  122.76 25.805 122.778 25.901 ;
    END
  END rsp_hi[49]
  PIN rsp_hi[4]
    DIRECTION INPUT ;
    USE SIGNAL ;
    PORT
      LAYER M5 ;
        RECT  79.44 25.836 79.464 25.92 ;
    END
    PORT
      LAYER M5 ;
        RECT  79.44 25.765 79.464 25.872 ;
    END
  END rsp_hi[4]
  PIN rsp_hi[50]
    DIRECTION INPUT ;
    USE SIGNAL ;
    PORT
      LAYER M5 ;
        RECT  123.696 25.836 123.72 25.92 ;
    END
    PORT
      LAYER M5 ;
        RECT  123.696 25.765 123.72 25.872 ;
    END
  END rsp_hi[50]
  PIN rsp_hi[51]
    DIRECTION INPUT ;
    USE SIGNAL ;
    PORT
      LAYER M3 ;
        RECT  124.668 25.882 124.686 25.92 ;
    END
    PORT
      LAYER M3 ;
        RECT  124.668 23.549 124.686 25.901 ;
    END
  END rsp_hi[51]
  PIN rsp_hi[52]
    DIRECTION INPUT ;
    USE SIGNAL ;
    PORT
      LAYER M5 ;
        RECT  125.664 25.836 125.688 25.92 ;
    END
    PORT
      LAYER M5 ;
        RECT  125.664 23.893 125.688 25.872 ;
    END
  END rsp_hi[52]
  PIN rsp_hi[53]
    DIRECTION INPUT ;
    USE SIGNAL ;
    PORT
      LAYER M3 ;
        RECT  126.612 25.882 126.63 25.92 ;
    END
    PORT
      LAYER M3 ;
        RECT  126.612 23.927 126.63 25.901 ;
    END
  END rsp_hi[53]
  PIN rsp_hi[54]
    DIRECTION INPUT ;
    USE SIGNAL ;
    PORT
      LAYER M5 ;
        RECT  127.584 25.836 127.608 25.92 ;
    END
    PORT
      LAYER M5 ;
        RECT  127.584 23.893 127.608 25.872 ;
    END
  END rsp_hi[54]
  PIN rsp_hi[55]
    DIRECTION INPUT ;
    USE SIGNAL ;
    PORT
      LAYER M3 ;
        RECT  128.52 25.882 128.538 25.92 ;
    END
    PORT
      LAYER M3 ;
        RECT  128.52 25.805 128.538 25.901 ;
    END
  END rsp_hi[55]
  PIN rsp_hi[56]
    DIRECTION INPUT ;
    USE SIGNAL ;
    PORT
      LAYER M5 ;
        RECT  129.504 25.836 129.528 25.92 ;
    END
    PORT
      LAYER M5 ;
        RECT  129.504 25.765 129.528 25.872 ;
    END
  END rsp_hi[56]
  PIN rsp_hi[57]
    DIRECTION INPUT ;
    USE SIGNAL ;
    PORT
      LAYER M3 ;
        RECT  130.464 25.882 130.482 25.92 ;
    END
    PORT
      LAYER M3 ;
        RECT  130.464 23.741 130.482 25.901 ;
    END
  END rsp_hi[57]
  PIN rsp_hi[58]
    DIRECTION INPUT ;
    USE SIGNAL ;
    PORT
      LAYER M5 ;
        RECT  131.424 25.836 131.448 25.92 ;
    END
    PORT
      LAYER M5 ;
        RECT  131.424 23.783 131.448 25.872 ;
    END
  END rsp_hi[58]
  PIN rsp_hi[59]
    DIRECTION INPUT ;
    USE SIGNAL ;
    PORT
      LAYER M3 ;
        RECT  132.372 25.882 132.39 25.92 ;
    END
    PORT
      LAYER M3 ;
        RECT  132.372 23.777 132.39 25.901 ;
    END
  END rsp_hi[59]
  PIN rsp_hi[5]
    DIRECTION INPUT ;
    USE SIGNAL ;
    PORT
      LAYER M3 ;
        RECT  80.388 25.882 80.406 25.92 ;
    END
    PORT
      LAYER M3 ;
        RECT  80.388 23.549 80.406 25.901 ;
    END
  END rsp_hi[5]
  PIN rsp_hi[60]
    DIRECTION INPUT ;
    USE SIGNAL ;
    PORT
      LAYER M5 ;
        RECT  133.344 25.836 133.368 25.92 ;
    END
    PORT
      LAYER M5 ;
        RECT  133.344 23.701 133.368 25.872 ;
    END
  END rsp_hi[60]
  PIN rsp_hi[61]
    DIRECTION INPUT ;
    USE SIGNAL ;
    PORT
      LAYER M3 ;
        RECT  134.316 25.882 134.334 25.92 ;
    END
    PORT
      LAYER M3 ;
        RECT  134.316 25.805 134.334 25.901 ;
    END
  END rsp_hi[61]
  PIN rsp_hi[62]
    DIRECTION INPUT ;
    USE SIGNAL ;
    PORT
      LAYER M5 ;
        RECT  135.264 25.836 135.288 25.92 ;
    END
    PORT
      LAYER M5 ;
        RECT  135.264 25.765 135.288 25.872 ;
    END
  END rsp_hi[62]
  PIN rsp_hi[63]
    DIRECTION INPUT ;
    USE SIGNAL ;
    PORT
      LAYER M3 ;
        RECT  136.224 25.882 136.242 25.92 ;
    END
    PORT
      LAYER M3 ;
        RECT  136.224 23.549 136.242 25.901 ;
    END
  END rsp_hi[63]
  PIN rsp_hi[64]
    DIRECTION INPUT ;
    USE SIGNAL ;
    PORT
      LAYER M5 ;
        RECT  137.184 25.836 137.208 25.92 ;
    END
    PORT
      LAYER M5 ;
        RECT  137.184 23.893 137.208 25.872 ;
    END
  END rsp_hi[64]
  PIN rsp_hi[65]
    DIRECTION INPUT ;
    USE SIGNAL ;
    PORT
      LAYER M3 ;
        RECT  138.168 25.882 138.186 25.92 ;
    END
    PORT
      LAYER M3 ;
        RECT  138.168 25.133 138.186 25.901 ;
    END
  END rsp_hi[65]
  PIN rsp_hi[66]
    DIRECTION INPUT ;
    USE SIGNAL ;
    PORT
      LAYER M5 ;
        RECT  139.104 25.836 139.128 25.92 ;
    END
    PORT
      LAYER M5 ;
        RECT  139.104 25.093 139.128 25.872 ;
    END
  END rsp_hi[66]
  PIN rsp_hi[67]
    DIRECTION INPUT ;
    USE SIGNAL ;
    PORT
      LAYER M3 ;
        RECT  140.076 25.882 140.094 25.92 ;
    END
    PORT
      LAYER M3 ;
        RECT  140.076 23.549 140.094 25.901 ;
    END
  END rsp_hi[67]
  PIN rsp_hi[68]
    DIRECTION INPUT ;
    USE SIGNAL ;
    PORT
      LAYER M5 ;
        RECT  141.024 25.836 141.048 25.92 ;
    END
    PORT
      LAYER M5 ;
        RECT  141.024 23.893 141.048 25.872 ;
    END
  END rsp_hi[68]
  PIN rsp_hi[69]
    DIRECTION INPUT ;
    USE SIGNAL ;
    PORT
      LAYER M3 ;
        RECT  142.02 25.882 142.038 25.92 ;
    END
    PORT
      LAYER M3 ;
        RECT  142.02 23.885 142.038 25.901 ;
    END
  END rsp_hi[69]
  PIN rsp_hi[6]
    DIRECTION INPUT ;
    USE SIGNAL ;
    PORT
      LAYER M5 ;
        RECT  81.36 25.836 81.384 25.92 ;
    END
    PORT
      LAYER M5 ;
        RECT  81.36 23.893 81.384 25.872 ;
    END
  END rsp_hi[6]
  PIN rsp_hi[70]
    DIRECTION INPUT ;
    USE SIGNAL ;
    PORT
      LAYER M5 ;
        RECT  142.992 25.836 143.016 25.92 ;
    END
    PORT
      LAYER M5 ;
        RECT  142.992 23.783 143.016 25.872 ;
    END
  END rsp_hi[70]
  PIN rsp_hi[71]
    DIRECTION INPUT ;
    USE SIGNAL ;
    PORT
      LAYER M3 ;
        RECT  143.928 25.882 143.946 25.92 ;
    END
    PORT
      LAYER M3 ;
        RECT  143.928 23.549 143.946 25.901 ;
    END
  END rsp_hi[71]
  PIN rsp_hi[72]
    DIRECTION INPUT ;
    USE SIGNAL ;
    PORT
      LAYER M5 ;
        RECT  144.912 25.836 144.936 25.92 ;
    END
    PORT
      LAYER M5 ;
        RECT  144.912 25.093 144.936 25.872 ;
    END
  END rsp_hi[72]
  PIN rsp_hi[73]
    DIRECTION INPUT ;
    USE SIGNAL ;
    PORT
      LAYER M3 ;
        RECT  145.872 25.882 145.89 25.92 ;
    END
    PORT
      LAYER M3 ;
        RECT  145.872 23.933 145.89 25.901 ;
    END
  END rsp_hi[73]
  PIN rsp_hi[74]
    DIRECTION INPUT ;
    USE SIGNAL ;
    PORT
      LAYER M5 ;
        RECT  146.832 25.836 146.856 25.92 ;
    END
    PORT
      LAYER M5 ;
        RECT  146.832 23.893 146.856 25.872 ;
    END
  END rsp_hi[74]
  PIN rsp_hi[75]
    DIRECTION INPUT ;
    USE SIGNAL ;
    PORT
      LAYER M3 ;
        RECT  147.78 25.882 147.798 25.92 ;
    END
    PORT
      LAYER M3 ;
        RECT  147.78 23.777 147.798 25.901 ;
    END
  END rsp_hi[75]
  PIN rsp_hi[76]
    DIRECTION INPUT ;
    USE SIGNAL ;
    PORT
      LAYER M5 ;
        RECT  148.752 25.836 148.776 25.92 ;
    END
    PORT
      LAYER M5 ;
        RECT  148.752 23.783 148.776 25.872 ;
    END
  END rsp_hi[76]
  PIN rsp_hi[77]
    DIRECTION INPUT ;
    USE SIGNAL ;
    PORT
      LAYER M3 ;
        RECT  149.724 25.882 149.742 25.92 ;
    END
    PORT
      LAYER M3 ;
        RECT  149.724 24.413 149.742 25.901 ;
    END
  END rsp_hi[77]
  PIN rsp_hi[7]
    DIRECTION INPUT ;
    USE SIGNAL ;
    PORT
      LAYER M3 ;
        RECT  82.332 25.882 82.35 25.92 ;
    END
    PORT
      LAYER M3 ;
        RECT  82.332 25.133 82.35 25.901 ;
    END
  END rsp_hi[7]
  PIN rsp_hi[8]
    DIRECTION INPUT ;
    USE SIGNAL ;
    PORT
      LAYER M5 ;
        RECT  83.28 25.836 83.304 25.92 ;
    END
    PORT
      LAYER M5 ;
        RECT  83.28 25.093 83.304 25.872 ;
    END
  END rsp_hi[8]
  PIN rsp_hi[9]
    DIRECTION INPUT ;
    USE SIGNAL ;
    PORT
      LAYER M3 ;
        RECT  84.24 25.882 84.258 25.92 ;
    END
    PORT
      LAYER M3 ;
        RECT  84.24 23.741 84.258 25.901 ;
    END
  END rsp_hi[9]
  PIN rsp_layer[0]
    DIRECTION OUTPUT ;
    USE SIGNAL ;
    PORT
      LAYER M4 ;
        RECT  0 15.744 0.084 15.768 ;
    END
  END rsp_layer[0]
  PIN rsp_layer[1]
    DIRECTION OUTPUT ;
    USE SIGNAL ;
    PORT
      LAYER M4 ;
        RECT  0 15.984 0.084 16.008 ;
    END
  END rsp_layer[1]
  PIN rsp_layer[2]
    DIRECTION OUTPUT ;
    USE SIGNAL ;
    PORT
      LAYER M4 ;
        RECT  0 16.224 0.084 16.248 ;
    END
  END rsp_layer[2]
  PIN rsp_layer[3]
    DIRECTION OUTPUT ;
    USE SIGNAL ;
    PORT
      LAYER M4 ;
        RECT  0 16.464 0.084 16.488 ;
    END
  END rsp_layer[3]
  PIN rsp_layer[4]
    DIRECTION OUTPUT ;
    USE SIGNAL ;
    PORT
      LAYER M4 ;
        RECT  0 16.752 0.084 16.776 ;
    END
  END rsp_layer[4]
  PIN rsp_layer[5]
    DIRECTION OUTPUT ;
    USE SIGNAL ;
    PORT
      LAYER M4 ;
        RECT  0 16.992 0.084 17.016 ;
    END
  END rsp_layer[5]
  PIN rsp_lo[0]
    DIRECTION INPUT ;
    USE SIGNAL ;
    PORT
      LAYER M3 ;
        RECT  84.564 0 84.582 0.038 ;
    END
    PORT
      LAYER M3 ;
        RECT  84.564 0.012 84.582 1.723 ;
    END
  END rsp_lo[0]
  PIN rsp_lo[10]
    DIRECTION INPUT ;
    USE SIGNAL ;
    PORT
      LAYER M3 ;
        RECT  92.7 0 92.718 0.038 ;
    END
    PORT
      LAYER M3 ;
        RECT  92.7 0.012 92.718 1.723 ;
    END
  END rsp_lo[10]
  PIN rsp_lo[11]
    DIRECTION INPUT ;
    USE SIGNAL ;
    PORT
      LAYER M5 ;
        RECT  93.504 0 93.528 0.084 ;
    END
    PORT
      LAYER M5 ;
        RECT  93.504 0.016 93.528 0.611 ;
    END
  END rsp_lo[11]
  PIN rsp_lo[12]
    DIRECTION INPUT ;
    USE SIGNAL ;
    PORT
      LAYER M3 ;
        RECT  94.356 0 94.374 0.038 ;
    END
    PORT
      LAYER M3 ;
        RECT  94.356 0.012 94.374 1.723 ;
    END
  END rsp_lo[12]
  PIN rsp_lo[13]
    DIRECTION INPUT ;
    USE SIGNAL ;
    PORT
      LAYER M5 ;
        RECT  95.136 0 95.16 0.084 ;
    END
    PORT
      LAYER M5 ;
        RECT  95.136 0.016 95.16 1.763 ;
    END
  END rsp_lo[13]
  PIN rsp_lo[14]
    DIRECTION INPUT ;
    USE SIGNAL ;
    PORT
      LAYER M3 ;
        RECT  95.976 0 95.994 0.038 ;
    END
    PORT
      LAYER M3 ;
        RECT  95.976 0.012 95.994 2.371 ;
    END
  END rsp_lo[14]
  PIN rsp_lo[15]
    DIRECTION INPUT ;
    USE SIGNAL ;
    PORT
      LAYER M5 ;
        RECT  96.768 0 96.792 0.084 ;
    END
    PORT
      LAYER M5 ;
        RECT  96.768 0.016 96.792 1.763 ;
    END
  END rsp_lo[15]
  PIN rsp_lo[16]
    DIRECTION INPUT ;
    USE SIGNAL ;
    PORT
      LAYER M3 ;
        RECT  97.596 0 97.614 0.038 ;
    END
    PORT
      LAYER M3 ;
        RECT  97.596 0.012 97.614 1.723 ;
    END
  END rsp_lo[16]
  PIN rsp_lo[17]
    DIRECTION INPUT ;
    USE SIGNAL ;
    PORT
      LAYER M5 ;
        RECT  98.4 0 98.424 0.084 ;
    END
    PORT
      LAYER M5 ;
        RECT  98.4 0.016 98.424 1.763 ;
    END
  END rsp_lo[17]
  PIN rsp_lo[18]
    DIRECTION INPUT ;
    USE SIGNAL ;
    PORT
      LAYER M3 ;
        RECT  99.252 0 99.27 0.038 ;
    END
    PORT
      LAYER M3 ;
        RECT  99.252 0.012 99.27 1.723 ;
    END
  END rsp_lo[18]
  PIN rsp_lo[19]
    DIRECTION INPUT ;
    USE SIGNAL ;
    PORT
      LAYER M5 ;
        RECT  100.032 0 100.056 0.084 ;
    END
    PORT
      LAYER M5 ;
        RECT  100.032 0.016 100.056 1.763 ;
    END
  END rsp_lo[19]
  PIN rsp_lo[1]
    DIRECTION INPUT ;
    USE SIGNAL ;
    PORT
      LAYER M5 ;
        RECT  85.392 0 85.416 0.084 ;
    END
    PORT
      LAYER M5 ;
        RECT  85.392 0.016 85.416 1.763 ;
    END
  END rsp_lo[1]
  PIN rsp_lo[20]
    DIRECTION INPUT ;
    USE SIGNAL ;
    PORT
      LAYER M3 ;
        RECT  100.872 0 100.89 0.038 ;
    END
    PORT
      LAYER M3 ;
        RECT  100.872 0.012 100.89 1.723 ;
    END
  END rsp_lo[20]
  PIN rsp_lo[21]
    DIRECTION INPUT ;
    USE SIGNAL ;
    PORT
      LAYER M5 ;
        RECT  101.664 0 101.688 0.084 ;
    END
    PORT
      LAYER M5 ;
        RECT  101.664 0.016 101.688 1.763 ;
    END
  END rsp_lo[21]
  PIN rsp_lo[22]
    DIRECTION INPUT ;
    USE SIGNAL ;
    PORT
      LAYER M3 ;
        RECT  102.492 0 102.51 0.038 ;
    END
    PORT
      LAYER M3 ;
        RECT  102.492 0.012 102.51 0.571 ;
    END
  END rsp_lo[22]
  PIN rsp_lo[23]
    DIRECTION INPUT ;
    USE SIGNAL ;
    PORT
      LAYER M5 ;
        RECT  103.296 0 103.32 0.084 ;
    END
    PORT
      LAYER M5 ;
        RECT  103.296 0.016 103.32 0.611 ;
    END
  END rsp_lo[23]
  PIN rsp_lo[24]
    DIRECTION INPUT ;
    USE SIGNAL ;
    PORT
      LAYER M3 ;
        RECT  104.112 0 104.13 0.038 ;
    END
    PORT
      LAYER M3 ;
        RECT  104.112 0.012 104.13 2.371 ;
    END
  END rsp_lo[24]
  PIN rsp_lo[25]
    DIRECTION INPUT ;
    USE SIGNAL ;
    PORT
      LAYER M5 ;
        RECT  104.928 0 104.952 0.084 ;
    END
    PORT
      LAYER M5 ;
        RECT  104.928 0.016 104.952 0.611 ;
    END
  END rsp_lo[25]
  PIN rsp_lo[26]
    DIRECTION INPUT ;
    USE SIGNAL ;
    PORT
      LAYER M3 ;
        RECT  105.768 0 105.786 0.038 ;
    END
    PORT
      LAYER M3 ;
        RECT  105.768 0.012 105.786 1.723 ;
    END
  END rsp_lo[26]
  PIN rsp_lo[27]
    DIRECTION INPUT ;
    USE SIGNAL ;
    PORT
      LAYER M5 ;
        RECT  106.56 0 106.584 0.084 ;
    END
    PORT
      LAYER M5 ;
        RECT  106.56 0.016 106.584 1.763 ;
    END
  END rsp_lo[27]
  PIN rsp_lo[28]
    DIRECTION INPUT ;
    USE SIGNAL ;
    PORT
      LAYER M3 ;
        RECT  107.388 0 107.406 0.038 ;
    END
    PORT
      LAYER M3 ;
        RECT  107.388 0.012 107.406 1.723 ;
    END
  END rsp_lo[28]
  PIN rsp_lo[29]
    DIRECTION INPUT ;
    USE SIGNAL ;
    PORT
      LAYER M5 ;
        RECT  108.192 0 108.216 0.084 ;
    END
    PORT
      LAYER M5 ;
        RECT  108.192 0.016 108.216 1.763 ;
    END
  END rsp_lo[29]
  PIN rsp_lo[2]
    DIRECTION INPUT ;
    USE SIGNAL ;
    PORT
      LAYER M3 ;
        RECT  86.184 0 86.202 0.038 ;
    END
    PORT
      LAYER M3 ;
        RECT  86.184 0.012 86.202 1.723 ;
    END
  END rsp_lo[2]
  PIN rsp_lo[30]
    DIRECTION INPUT ;
    USE SIGNAL ;
    PORT
      LAYER M3 ;
        RECT  109.008 0 109.026 0.038 ;
    END
    PORT
      LAYER M3 ;
        RECT  109.008 0.012 109.026 1.723 ;
    END
  END rsp_lo[30]
  PIN rsp_lo[31]
    DIRECTION INPUT ;
    USE SIGNAL ;
    PORT
      LAYER M5 ;
        RECT  109.824 0 109.848 0.084 ;
    END
    PORT
      LAYER M5 ;
        RECT  109.824 0.016 109.848 1.763 ;
    END
  END rsp_lo[31]
  PIN rsp_lo[32]
    DIRECTION INPUT ;
    USE SIGNAL ;
    PORT
      LAYER M3 ;
        RECT  110.664 0 110.682 0.038 ;
    END
    PORT
      LAYER M3 ;
        RECT  110.664 0.012 110.682 1.723 ;
    END
  END rsp_lo[32]
  PIN rsp_lo[33]
    DIRECTION INPUT ;
    USE SIGNAL ;
    PORT
      LAYER M5 ;
        RECT  111.456 0 111.48 0.084 ;
    END
    PORT
      LAYER M5 ;
        RECT  111.456 0.016 111.48 1.763 ;
    END
  END rsp_lo[33]
  PIN rsp_lo[34]
    DIRECTION INPUT ;
    USE SIGNAL ;
    PORT
      LAYER M3 ;
        RECT  112.284 0 112.302 0.038 ;
    END
    PORT
      LAYER M3 ;
        RECT  112.284 0.012 112.302 2.101 ;
    END
  END rsp_lo[34]
  PIN rsp_lo[35]
    DIRECTION INPUT ;
    USE SIGNAL ;
    PORT
      LAYER M5 ;
        RECT  113.088 0 113.112 0.084 ;
    END
    PORT
      LAYER M5 ;
        RECT  113.088 0.016 113.112 0.611 ;
    END
  END rsp_lo[35]
  PIN rsp_lo[36]
    DIRECTION INPUT ;
    USE SIGNAL ;
    PORT
      LAYER M3 ;
        RECT  113.904 0 113.922 0.038 ;
    END
    PORT
      LAYER M3 ;
        RECT  113.904 0.012 113.922 0.571 ;
    END
  END rsp_lo[36]
  PIN rsp_lo[37]
    DIRECTION INPUT ;
    USE SIGNAL ;
    PORT
      LAYER M5 ;
        RECT  114.72 0 114.744 0.084 ;
    END
    PORT
      LAYER M5 ;
        RECT  114.72 0.016 114.744 0.611 ;
    END
  END rsp_lo[37]
  PIN rsp_lo[38]
    DIRECTION INPUT ;
    USE SIGNAL ;
    PORT
      LAYER M3 ;
        RECT  115.524 0 115.542 0.038 ;
    END
    PORT
      LAYER M3 ;
        RECT  115.524 0.012 115.542 2.143 ;
    END
  END rsp_lo[38]
  PIN rsp_lo[39]
    DIRECTION INPUT ;
    USE SIGNAL ;
    PORT
      LAYER M5 ;
        RECT  116.352 0 116.376 0.084 ;
    END
    PORT
      LAYER M5 ;
        RECT  116.352 0.016 116.376 0.611 ;
    END
  END rsp_lo[39]
  PIN rsp_lo[3]
    DIRECTION INPUT ;
    USE SIGNAL ;
    PORT
      LAYER M5 ;
        RECT  87.024 0 87.048 0.084 ;
    END
    PORT
      LAYER M5 ;
        RECT  87.024 0.016 87.048 1.763 ;
    END
  END rsp_lo[3]
  PIN rsp_lo[40]
    DIRECTION INPUT ;
    USE SIGNAL ;
    PORT
      LAYER M3 ;
        RECT  117.18 0 117.198 0.038 ;
    END
    PORT
      LAYER M3 ;
        RECT  117.18 0.012 117.198 2.371 ;
    END
  END rsp_lo[40]
  PIN rsp_lo[41]
    DIRECTION INPUT ;
    USE SIGNAL ;
    PORT
      LAYER M5 ;
        RECT  117.984 0 118.008 0.084 ;
    END
    PORT
      LAYER M5 ;
        RECT  117.984 0.016 118.008 0.611 ;
    END
  END rsp_lo[41]
  PIN rsp_lo[42]
    DIRECTION INPUT ;
    USE SIGNAL ;
    PORT
      LAYER M3 ;
        RECT  118.8 0 118.818 0.038 ;
    END
    PORT
      LAYER M3 ;
        RECT  118.8 0.012 118.818 1.723 ;
    END
  END rsp_lo[42]
  PIN rsp_lo[43]
    DIRECTION INPUT ;
    USE SIGNAL ;
    PORT
      LAYER M5 ;
        RECT  119.616 0 119.64 0.084 ;
    END
    PORT
      LAYER M5 ;
        RECT  119.616 0.016 119.64 1.763 ;
    END
  END rsp_lo[43]
  PIN rsp_lo[44]
    DIRECTION INPUT ;
    USE SIGNAL ;
    PORT
      LAYER M3 ;
        RECT  120.42 0 120.438 0.038 ;
    END
    PORT
      LAYER M3 ;
        RECT  120.42 0.012 120.438 1.723 ;
    END
  END rsp_lo[44]
  PIN rsp_lo[45]
    DIRECTION INPUT ;
    USE SIGNAL ;
    PORT
      LAYER M5 ;
        RECT  121.248 0 121.272 0.084 ;
    END
    PORT
      LAYER M5 ;
        RECT  121.248 0.016 121.272 2.137 ;
    END
  END rsp_lo[45]
  PIN rsp_lo[46]
    DIRECTION INPUT ;
    USE SIGNAL ;
    PORT
      LAYER M3 ;
        RECT  122.076 0 122.094 0.038 ;
    END
    PORT
      LAYER M3 ;
        RECT  122.076 0.012 122.094 1.723 ;
    END
  END rsp_lo[46]
  PIN rsp_lo[47]
    DIRECTION INPUT ;
    USE SIGNAL ;
    PORT
      LAYER M5 ;
        RECT  122.88 0 122.904 0.084 ;
    END
    PORT
      LAYER M5 ;
        RECT  122.88 0.016 122.904 1.763 ;
    END
  END rsp_lo[47]
  PIN rsp_lo[48]
    DIRECTION INPUT ;
    USE SIGNAL ;
    PORT
      LAYER M3 ;
        RECT  123.696 0 123.714 0.038 ;
    END
    PORT
      LAYER M3 ;
        RECT  123.696 0.012 123.714 1.723 ;
    END
  END rsp_lo[48]
  PIN rsp_lo[49]
    DIRECTION INPUT ;
    USE SIGNAL ;
    PORT
      LAYER M5 ;
        RECT  124.512 0 124.536 0.084 ;
    END
    PORT
      LAYER M5 ;
        RECT  124.512 0.016 124.536 1.763 ;
    END
  END rsp_lo[49]
  PIN rsp_lo[4]
    DIRECTION INPUT ;
    USE SIGNAL ;
    PORT
      LAYER M3 ;
        RECT  87.804 0 87.822 0.038 ;
    END
    PORT
      LAYER M3 ;
        RECT  87.804 0.012 87.822 1.723 ;
    END
  END rsp_lo[4]
  PIN rsp_lo[50]
    DIRECTION INPUT ;
    USE SIGNAL ;
    PORT
      LAYER M3 ;
        RECT  125.316 0 125.334 0.038 ;
    END
    PORT
      LAYER M3 ;
        RECT  125.316 0.012 125.334 0.571 ;
    END
  END rsp_lo[50]
  PIN rsp_lo[51]
    DIRECTION INPUT ;
    USE SIGNAL ;
    PORT
      LAYER M5 ;
        RECT  126.144 0 126.168 0.084 ;
    END
    PORT
      LAYER M5 ;
        RECT  126.144 0.016 126.168 0.611 ;
    END
  END rsp_lo[51]
  PIN rsp_lo[52]
    DIRECTION INPUT ;
    USE SIGNAL ;
    PORT
      LAYER M3 ;
        RECT  126.972 0 126.99 0.038 ;
    END
    PORT
      LAYER M3 ;
        RECT  126.972 0.012 126.99 2.143 ;
    END
  END rsp_lo[52]
  PIN rsp_lo[53]
    DIRECTION INPUT ;
    USE SIGNAL ;
    PORT
      LAYER M5 ;
        RECT  127.776 0 127.8 0.084 ;
    END
    PORT
      LAYER M5 ;
        RECT  127.776 0.016 127.8 0.611 ;
    END
  END rsp_lo[53]
  PIN rsp_lo[54]
    DIRECTION INPUT ;
    USE SIGNAL ;
    PORT
      LAYER M3 ;
        RECT  128.592 0 128.61 0.038 ;
    END
    PORT
      LAYER M3 ;
        RECT  128.592 0.012 128.61 2.291 ;
    END
  END rsp_lo[54]
  PIN rsp_lo[55]
    DIRECTION INPUT ;
    USE SIGNAL ;
    PORT
      LAYER M5 ;
        RECT  129.408 0 129.432 0.084 ;
    END
    PORT
      LAYER M5 ;
        RECT  129.408 0.016 129.432 0.611 ;
    END
  END rsp_lo[55]
  PIN rsp_lo[56]
    DIRECTION INPUT ;
    USE SIGNAL ;
    PORT
      LAYER M3 ;
        RECT  130.212 0 130.23 0.038 ;
    END
    PORT
      LAYER M3 ;
        RECT  130.212 0.012 130.23 1.723 ;
    END
  END rsp_lo[56]
  PIN rsp_lo[57]
    DIRECTION INPUT ;
    USE SIGNAL ;
    PORT
      LAYER M5 ;
        RECT  131.04 0 131.064 0.084 ;
    END
    PORT
      LAYER M5 ;
        RECT  131.04 0.016 131.064 1.763 ;
    END
  END rsp_lo[57]
  PIN rsp_lo[58]
    DIRECTION INPUT ;
    USE SIGNAL ;
    PORT
      LAYER M3 ;
        RECT  131.832 0 131.85 0.038 ;
    END
    PORT
      LAYER M3 ;
        RECT  131.832 0.012 131.85 1.723 ;
    END
  END rsp_lo[58]
  PIN rsp_lo[59]
    DIRECTION INPUT ;
    USE SIGNAL ;
    PORT
      LAYER M5 ;
        RECT  132.672 0 132.696 0.084 ;
    END
    PORT
      LAYER M5 ;
        RECT  132.672 0.016 132.696 1.763 ;
    END
  END rsp_lo[59]
  PIN rsp_lo[5]
    DIRECTION INPUT ;
    USE SIGNAL ;
    PORT
      LAYER M5 ;
        RECT  88.656 0 88.68 0.084 ;
    END
    PORT
      LAYER M5 ;
        RECT  88.656 0.016 88.68 1.763 ;
    END
  END rsp_lo[5]
  PIN rsp_lo[60]
    DIRECTION INPUT ;
    USE SIGNAL ;
    PORT
      LAYER M3 ;
        RECT  133.488 0 133.506 0.038 ;
    END
    PORT
      LAYER M3 ;
        RECT  133.488 0.012 133.506 1.723 ;
    END
  END rsp_lo[60]
  PIN rsp_lo[61]
    DIRECTION INPUT ;
    USE SIGNAL ;
    PORT
      LAYER M5 ;
        RECT  134.304 0 134.328 0.084 ;
    END
    PORT
      LAYER M5 ;
        RECT  134.304 0.016 134.328 1.763 ;
    END
  END rsp_lo[61]
  PIN rsp_lo[62]
    DIRECTION INPUT ;
    USE SIGNAL ;
    PORT
      LAYER M3 ;
        RECT  135.108 0 135.126 0.038 ;
    END
    PORT
      LAYER M3 ;
        RECT  135.108 0.012 135.126 1.723 ;
    END
  END rsp_lo[62]
  PIN rsp_lo[63]
    DIRECTION INPUT ;
    USE SIGNAL ;
    PORT
      LAYER M5 ;
        RECT  135.936 0 135.96 0.084 ;
    END
    PORT
      LAYER M5 ;
        RECT  135.936 0.016 135.96 1.763 ;
    END
  END rsp_lo[63]
  PIN rsp_lo[64]
    DIRECTION INPUT ;
    USE SIGNAL ;
    PORT
      LAYER M3 ;
        RECT  136.728 0 136.746 0.038 ;
    END
    PORT
      LAYER M3 ;
        RECT  136.728 0.012 136.746 0.571 ;
    END
  END rsp_lo[64]
  PIN rsp_lo[65]
    DIRECTION INPUT ;
    USE SIGNAL ;
    PORT
      LAYER M5 ;
        RECT  137.568 0 137.592 0.084 ;
    END
    PORT
      LAYER M5 ;
        RECT  137.568 0.016 137.592 0.611 ;
    END
  END rsp_lo[65]
  PIN rsp_lo[66]
    DIRECTION INPUT ;
    USE SIGNAL ;
    PORT
      LAYER M3 ;
        RECT  138.384 0 138.402 0.038 ;
    END
    PORT
      LAYER M3 ;
        RECT  138.384 0.012 138.402 0.571 ;
    END
  END rsp_lo[66]
  PIN rsp_lo[67]
    DIRECTION INPUT ;
    USE SIGNAL ;
    PORT
      LAYER M5 ;
        RECT  139.2 0 139.224 0.084 ;
    END
    PORT
      LAYER M5 ;
        RECT  139.2 0.016 139.224 0.611 ;
    END
  END rsp_lo[67]
  PIN rsp_lo[68]
    DIRECTION INPUT ;
    USE SIGNAL ;
    PORT
      LAYER M3 ;
        RECT  140.004 0 140.022 0.038 ;
    END
    PORT
      LAYER M3 ;
        RECT  140.004 0.012 140.022 2.371 ;
    END
  END rsp_lo[68]
  PIN rsp_lo[69]
    DIRECTION INPUT ;
    USE SIGNAL ;
    PORT
      LAYER M5 ;
        RECT  140.832 0 140.856 0.084 ;
    END
    PORT
      LAYER M5 ;
        RECT  140.832 0.016 140.856 0.611 ;
    END
  END rsp_lo[69]
  PIN rsp_lo[6]
    DIRECTION INPUT ;
    USE SIGNAL ;
    PORT
      LAYER M3 ;
        RECT  89.46 0 89.478 0.038 ;
    END
    PORT
      LAYER M3 ;
        RECT  89.46 0.012 89.478 2.143 ;
    END
  END rsp_lo[6]
  PIN rsp_lo[70]
    DIRECTION INPUT ;
    USE SIGNAL ;
    PORT
      LAYER M3 ;
        RECT  141.624 0 141.642 0.038 ;
    END
    PORT
      LAYER M3 ;
        RECT  141.624 0.012 141.642 1.723 ;
    END
  END rsp_lo[70]
  PIN rsp_lo[71]
    DIRECTION INPUT ;
    USE SIGNAL ;
    PORT
      LAYER M5 ;
        RECT  142.464 0 142.488 0.084 ;
    END
    PORT
      LAYER M5 ;
        RECT  142.464 0.016 142.488 1.763 ;
    END
  END rsp_lo[71]
  PIN rsp_lo[72]
    DIRECTION INPUT ;
    USE SIGNAL ;
    PORT
      LAYER M3 ;
        RECT  143.244 0 143.262 0.038 ;
    END
    PORT
      LAYER M3 ;
        RECT  143.244 0.012 143.262 2.143 ;
    END
  END rsp_lo[72]
  PIN rsp_lo[73]
    DIRECTION INPUT ;
    USE SIGNAL ;
    PORT
      LAYER M5 ;
        RECT  144.096 0 144.12 0.084 ;
    END
    PORT
      LAYER M5 ;
        RECT  144.096 0.016 144.12 1.763 ;
    END
  END rsp_lo[73]
  PIN rsp_lo[74]
    DIRECTION INPUT ;
    USE SIGNAL ;
    PORT
      LAYER M3 ;
        RECT  144.9 0 144.918 0.038 ;
    END
    PORT
      LAYER M3 ;
        RECT  144.9 0.012 144.918 1.723 ;
    END
  END rsp_lo[74]
  PIN rsp_lo[75]
    DIRECTION INPUT ;
    USE SIGNAL ;
    PORT
      LAYER M5 ;
        RECT  145.728 0 145.752 0.084 ;
    END
    PORT
      LAYER M5 ;
        RECT  145.728 0.016 145.752 1.763 ;
    END
  END rsp_lo[75]
  PIN rsp_lo[76]
    DIRECTION INPUT ;
    USE SIGNAL ;
    PORT
      LAYER M3 ;
        RECT  146.52 0 146.538 0.038 ;
    END
    PORT
      LAYER M3 ;
        RECT  146.52 0.012 146.538 1.723 ;
    END
  END rsp_lo[76]
  PIN rsp_lo[77]
    DIRECTION INPUT ;
    USE SIGNAL ;
    PORT
      LAYER M5 ;
        RECT  147.312 0 147.336 0.084 ;
    END
    PORT
      LAYER M5 ;
        RECT  147.312 0.016 147.336 1.763 ;
    END
  END rsp_lo[77]
  PIN rsp_lo[7]
    DIRECTION INPUT ;
    USE SIGNAL ;
    PORT
      LAYER M5 ;
        RECT  90.24 0 90.264 0.084 ;
    END
    PORT
      LAYER M5 ;
        RECT  90.24 0.016 90.264 0.611 ;
    END
  END rsp_lo[7]
  PIN rsp_lo[8]
    DIRECTION INPUT ;
    USE SIGNAL ;
    PORT
      LAYER M3 ;
        RECT  91.08 0 91.098 0.038 ;
    END
    PORT
      LAYER M3 ;
        RECT  91.08 0.012 91.098 0.571 ;
    END
  END rsp_lo[8]
  PIN rsp_lo[9]
    DIRECTION INPUT ;
    USE SIGNAL ;
    PORT
      LAYER M5 ;
        RECT  91.872 0 91.896 0.084 ;
    END
    PORT
      LAYER M5 ;
        RECT  91.872 0.016 91.896 0.611 ;
    END
  END rsp_lo[9]
  PIN rsp_t[0]
    DIRECTION OUTPUT ;
    USE SIGNAL ;
    PORT
      LAYER M4 ;
        RECT  0 17.232 0.084 17.256 ;
    END
  END rsp_t[0]
  PIN rsp_t[10]
    DIRECTION OUTPUT ;
    USE SIGNAL ;
    PORT
      LAYER M4 ;
        RECT  0 19.68 0.084 19.704 ;
    END
  END rsp_t[10]
  PIN rsp_t[11]
    DIRECTION OUTPUT ;
    USE SIGNAL ;
    PORT
      LAYER M4 ;
        RECT  0 19.92 0.084 19.944 ;
    END
  END rsp_t[11]
  PIN rsp_t[12]
    DIRECTION OUTPUT ;
    USE SIGNAL ;
    PORT
      LAYER M4 ;
        RECT  0 20.16 0.084 20.184 ;
    END
  END rsp_t[12]
  PIN rsp_t[13]
    DIRECTION OUTPUT ;
    USE SIGNAL ;
    PORT
      LAYER M4 ;
        RECT  0 20.4 0.084 20.424 ;
    END
  END rsp_t[13]
  PIN rsp_t[1]
    DIRECTION OUTPUT ;
    USE SIGNAL ;
    PORT
      LAYER M4 ;
        RECT  0 17.472 0.084 17.496 ;
    END
  END rsp_t[1]
  PIN rsp_t[2]
    DIRECTION OUTPUT ;
    USE SIGNAL ;
    PORT
      LAYER M4 ;
        RECT  0 17.712 0.084 17.736 ;
    END
  END rsp_t[2]
  PIN rsp_t[3]
    DIRECTION OUTPUT ;
    USE SIGNAL ;
    PORT
      LAYER M4 ;
        RECT  0 17.952 0.084 17.976 ;
    END
  END rsp_t[3]
  PIN rsp_t[4]
    DIRECTION OUTPUT ;
    USE SIGNAL ;
    PORT
      LAYER M4 ;
        RECT  0 18.192 0.084 18.216 ;
    END
  END rsp_t[4]
  PIN rsp_t[5]
    DIRECTION OUTPUT ;
    USE SIGNAL ;
    PORT
      LAYER M4 ;
        RECT  0 18.432 0.084 18.456 ;
    END
  END rsp_t[5]
  PIN rsp_t[6]
    DIRECTION OUTPUT ;
    USE SIGNAL ;
    PORT
      LAYER M4 ;
        RECT  0 18.672 0.084 18.696 ;
    END
  END rsp_t[6]
  PIN rsp_t[7]
    DIRECTION OUTPUT ;
    USE SIGNAL ;
    PORT
      LAYER M4 ;
        RECT  0 18.912 0.084 18.936 ;
    END
  END rsp_t[7]
  PIN rsp_t[8]
    DIRECTION OUTPUT ;
    USE SIGNAL ;
    PORT
      LAYER M4 ;
        RECT  0 19.152 0.084 19.176 ;
    END
  END rsp_t[8]
  PIN rsp_t[9]
    DIRECTION OUTPUT ;
    USE SIGNAL ;
    PORT
      LAYER M4 ;
        RECT  0 19.44 0.084 19.464 ;
    END
  END rsp_t[9]
  PIN rsp_v
    DIRECTION OUTPUT ;
    USE SIGNAL ;
    PORT
      LAYER M4 ;
        RECT  0 20.64 0.084 20.664 ;
    END
  END rsp_v
  PIN rsp_valid
    DIRECTION OUTPUT ;
    USE SIGNAL ;
    PORT
      LAYER M4 ;
        RECT  0 20.88 0.084 20.904 ;
    END
  END rsp_valid
  PIN rst_n
    DIRECTION INPUT ;
    USE SIGNAL ;
    PORT
      LAYER M4 ;
        RECT  0 21.12 0.084 21.144 ;
    END
  END rst_n
  PIN rst_o
    DIRECTION OUTPUT ;
    USE SIGNAL ;
    PORT
      LAYER M3 ;
        RECT  148.14 0 148.158 0.038 ;
    END
    PORT
      LAYER M3 ;
        RECT  148.14 0.012 148.158 2.143 ;
    END
  END rst_o
  PIN stack_o[0]
    DIRECTION OUTPUT ;
    USE SIGNAL ;
    PORT
      LAYER M5 ;
        RECT  148.944 0 148.968 0.084 ;
    END
    PORT
      LAYER M5 ;
        RECT  148.944 0.016 148.968 2.137 ;
    END
  END stack_o[0]
  PIN stack_o[1]
    DIRECTION OUTPUT ;
    USE SIGNAL ;
    PORT
      LAYER M3 ;
        RECT  149.796 0 149.814 0.038 ;
    END
    PORT
      LAYER M3 ;
        RECT  149.796 0.012 149.814 1.483 ;
    END
  END stack_o[1]
  PIN vreq_t[0]
    DIRECTION INPUT ;
    USE SIGNAL ;
    PORT
      LAYER M4 ;
        RECT  0 21.36 0.084 21.384 ;
    END
  END vreq_t[0]
  PIN vreq_t[10]
    DIRECTION INPUT ;
    USE SIGNAL ;
    PORT
      LAYER M4 ;
        RECT  0 23.808 0.084 23.832 ;
    END
  END vreq_t[10]
  PIN vreq_t[11]
    DIRECTION INPUT ;
    USE SIGNAL ;
    PORT
      LAYER M4 ;
        RECT  0 24.048 0.084 24.072 ;
    END
  END vreq_t[11]
  PIN vreq_t[12]
    DIRECTION INPUT ;
    USE SIGNAL ;
    PORT
      LAYER M4 ;
        RECT  0 24.288 0.084 24.312 ;
    END
  END vreq_t[12]
  PIN vreq_t[13]
    DIRECTION INPUT ;
    USE SIGNAL ;
    PORT
      LAYER M4 ;
        RECT  0 24.528 0.084 24.552 ;
    END
  END vreq_t[13]
  PIN vreq_t[1]
    DIRECTION INPUT ;
    USE SIGNAL ;
    PORT
      LAYER M4 ;
        RECT  0 21.6 0.084 21.624 ;
    END
  END vreq_t[1]
  PIN vreq_t[2]
    DIRECTION INPUT ;
    USE SIGNAL ;
    PORT
      LAYER M4 ;
        RECT  0 21.84 0.084 21.864 ;
    END
  END vreq_t[2]
  PIN vreq_t[3]
    DIRECTION INPUT ;
    USE SIGNAL ;
    PORT
      LAYER M4 ;
        RECT  0 22.08 0.084 22.104 ;
    END
  END vreq_t[3]
  PIN vreq_t[4]
    DIRECTION INPUT ;
    USE SIGNAL ;
    PORT
      LAYER M4 ;
        RECT  0 22.368 0.084 22.392 ;
    END
  END vreq_t[4]
  PIN vreq_t[5]
    DIRECTION INPUT ;
    USE SIGNAL ;
    PORT
      LAYER M4 ;
        RECT  0 22.608 0.084 22.632 ;
    END
  END vreq_t[5]
  PIN vreq_t[6]
    DIRECTION INPUT ;
    USE SIGNAL ;
    PORT
      LAYER M4 ;
        RECT  0 22.848 0.084 22.872 ;
    END
  END vreq_t[6]
  PIN vreq_t[7]
    DIRECTION INPUT ;
    USE SIGNAL ;
    PORT
      LAYER M4 ;
        RECT  0 23.088 0.084 23.112 ;
    END
  END vreq_t[7]
  PIN vreq_t[8]
    DIRECTION INPUT ;
    USE SIGNAL ;
    PORT
      LAYER M4 ;
        RECT  0 23.328 0.084 23.352 ;
    END
  END vreq_t[8]
  PIN vreq_t[9]
    DIRECTION INPUT ;
    USE SIGNAL ;
    PORT
      LAYER M4 ;
        RECT  0 23.568 0.084 23.592 ;
    END
  END vreq_t[9]
  PIN vreq_valid
    DIRECTION INPUT ;
    USE SIGNAL ;
    PORT
      LAYER M4 ;
        RECT  0 24.768 0.084 24.792 ;
    END
  END vreq_valid
  PIN VDD
    DIRECTION INOUT ;
    USE POWER ;
    PORT
      LAYER M5 ;
        RECT  148.392 2.151 148.512 23.769 ;
        RECT  142.992 2.151 143.112 23.769 ;
        RECT  137.592 2.151 137.712 23.769 ;
        RECT  132.192 2.151 132.312 23.769 ;
        RECT  126.792 2.151 126.912 23.769 ;
        RECT  121.392 2.151 121.512 23.769 ;
        RECT  115.992 2.151 116.112 23.769 ;
        RECT  110.592 2.151 110.712 23.769 ;
        RECT  105.192 2.151 105.312 23.769 ;
        RECT  99.792 2.151 99.912 23.769 ;
        RECT  94.392 2.151 94.512 23.769 ;
        RECT  88.992 2.151 89.112 23.769 ;
        RECT  83.592 2.151 83.712 23.769 ;
        RECT  78.192 2.151 78.312 23.769 ;
        RECT  72.792 2.151 72.912 23.769 ;
        RECT  67.392 2.151 67.512 23.769 ;
        RECT  61.992 2.151 62.112 23.769 ;
        RECT  56.592 2.151 56.712 23.769 ;
        RECT  51.192 2.151 51.312 23.769 ;
        RECT  45.792 2.151 45.912 23.769 ;
        RECT  40.392 2.151 40.512 23.769 ;
        RECT  34.992 2.151 35.112 23.769 ;
        RECT  29.592 2.151 29.712 23.769 ;
        RECT  24.192 2.151 24.312 23.769 ;
        RECT  18.792 2.151 18.912 23.769 ;
        RECT  13.392 2.151 13.512 23.769 ;
        RECT  7.992 2.151 8.112 23.769 ;
        RECT  2.592 2.151 2.712 23.769 ;
    END
  END VDD
  PIN VSS
    DIRECTION INOUT ;
    USE GROUND ;
    PORT
      LAYER M5 ;
        RECT  148.2 2.137 148.32 23.783 ;
        RECT  142.8 2.137 142.92 23.783 ;
        RECT  137.4 2.137 137.52 23.783 ;
        RECT  132 2.137 132.12 23.783 ;
        RECT  126.6 2.137 126.72 23.783 ;
        RECT  121.2 2.137 121.32 23.783 ;
        RECT  115.8 2.137 115.92 23.783 ;
        RECT  110.4 2.137 110.52 23.783 ;
        RECT  105 2.137 105.12 23.783 ;
        RECT  99.6 2.137 99.72 23.783 ;
        RECT  94.2 2.137 94.32 23.783 ;
        RECT  88.8 2.137 88.92 23.783 ;
        RECT  83.4 2.137 83.52 23.783 ;
        RECT  78 2.137 78.12 23.783 ;
        RECT  72.6 2.137 72.72 23.783 ;
        RECT  67.2 2.137 67.32 23.783 ;
        RECT  61.8 2.137 61.92 23.783 ;
        RECT  56.4 2.137 56.52 23.783 ;
        RECT  51 2.137 51.12 23.783 ;
        RECT  45.6 2.137 45.72 23.783 ;
        RECT  40.2 2.137 40.32 23.783 ;
        RECT  34.8 2.137 34.92 23.783 ;
        RECT  29.4 2.137 29.52 23.783 ;
        RECT  24 2.137 24.12 23.783 ;
        RECT  18.6 2.137 18.72 23.783 ;
        RECT  13.2 2.137 13.32 23.783 ;
        RECT  7.8 2.137 7.92 23.783 ;
        RECT  2.4 2.137 2.52 23.783 ;
    END
  END VSS
  # OT_OBS_CLOSED layer=M5 d_um=1.536 added=44
  OBS
    LAYER RVTN ;
     RECT  2.16 2.16 149.04 2.295 ;
     RECT  2.16 2.565 149.04 2.835 ;
     RECT  2.16 3.105 149.04 3.375 ;
     RECT  2.16 3.645 149.04 3.915 ;
     RECT  2.16 4.185 149.04 4.455 ;
     RECT  2.16 4.725 149.04 4.995 ;
     RECT  2.16 5.265 149.04 5.535 ;
     RECT  2.16 5.805 149.04 6.075 ;
     RECT  2.16 6.345 149.04 6.615 ;
     RECT  2.16 6.885 149.04 7.155 ;
     RECT  2.16 7.425 149.04 7.695 ;
     RECT  2.16 7.965 149.04 8.235 ;
     RECT  2.16 8.505 149.04 8.775 ;
     RECT  2.16 9.045 149.04 9.315 ;
     RECT  2.16 9.585 149.04 9.855 ;
     RECT  2.16 10.125 149.04 10.395 ;
     RECT  2.16 10.665 149.04 10.935 ;
     RECT  2.16 11.205 149.04 11.475 ;
     RECT  2.16 11.745 149.04 12.015 ;
     RECT  2.16 12.285 149.04 12.555 ;
     RECT  2.16 12.825 149.04 13.095 ;
     RECT  2.16 13.365 149.04 13.635 ;
     RECT  2.16 13.905 149.04 14.175 ;
     RECT  2.16 14.445 149.04 14.715 ;
     RECT  2.16 14.985 149.04 15.255 ;
     RECT  2.16 15.525 149.04 15.795 ;
     RECT  2.16 16.065 149.04 16.335 ;
     RECT  2.16 16.605 149.04 16.875 ;
     RECT  2.16 17.145 149.04 17.415 ;
     RECT  2.16 17.685 149.04 17.955 ;
     RECT  2.16 18.225 149.04 18.495 ;
     RECT  2.16 18.765 149.04 19.035 ;
     RECT  2.16 19.305 149.04 19.575 ;
     RECT  2.16 19.845 149.04 20.115 ;
     RECT  2.16 20.385 149.04 20.655 ;
     RECT  2.16 20.925 149.04 21.195 ;
     RECT  2.16 21.465 149.04 21.735 ;
     RECT  2.16 22.005 149.04 22.275 ;
     RECT  2.16 22.545 149.04 22.815 ;
     RECT  2.16 23.085 149.04 23.355 ;
     RECT  2.16 23.625 149.04 23.76 ;
    LAYER RVTP ;
     RECT  2.16 2.295 149.04 2.565 ;
     RECT  2.16 2.835 149.04 3.105 ;
     RECT  2.16 3.375 149.04 3.645 ;
     RECT  2.16 3.915 149.04 4.185 ;
     RECT  2.16 4.455 149.04 4.725 ;
     RECT  2.16 4.995 149.04 5.265 ;
     RECT  2.16 5.535 149.04 5.805 ;
     RECT  2.16 6.075 149.04 6.345 ;
     RECT  2.16 6.615 149.04 6.885 ;
     RECT  2.16 7.155 149.04 7.425 ;
     RECT  2.16 7.695 149.04 7.965 ;
     RECT  2.16 8.235 149.04 8.505 ;
     RECT  2.16 8.775 149.04 9.045 ;
     RECT  2.16 9.315 149.04 9.585 ;
     RECT  2.16 9.855 149.04 10.125 ;
     RECT  2.16 10.395 149.04 10.665 ;
     RECT  2.16 10.935 149.04 11.205 ;
     RECT  2.16 11.475 149.04 11.745 ;
     RECT  2.16 12.015 149.04 12.285 ;
     RECT  2.16 12.555 149.04 12.825 ;
     RECT  2.16 13.095 149.04 13.365 ;
     RECT  2.16 13.635 149.04 13.905 ;
     RECT  2.16 14.175 149.04 14.445 ;
     RECT  2.16 14.715 149.04 14.985 ;
     RECT  2.16 15.255 149.04 15.525 ;
     RECT  2.16 15.795 149.04 16.065 ;
     RECT  2.16 16.335 149.04 16.605 ;
     RECT  2.16 16.875 149.04 17.145 ;
     RECT  2.16 17.415 149.04 17.685 ;
     RECT  2.16 17.955 149.04 18.225 ;
     RECT  2.16 18.495 149.04 18.765 ;
     RECT  2.16 19.035 149.04 19.305 ;
     RECT  2.16 19.575 149.04 19.845 ;
     RECT  2.16 20.115 149.04 20.385 ;
     RECT  2.16 20.655 149.04 20.925 ;
     RECT  2.16 21.195 149.04 21.465 ;
     RECT  2.16 21.735 149.04 22.005 ;
     RECT  2.16 22.275 149.04 22.545 ;
     RECT  2.16 22.815 149.04 23.085 ;
     RECT  2.16 23.355 149.04 23.625 ;
    LAYER M1 ;
     RECT  2.16 2.151 149.04 23.769 ;
    LAYER M2 ;
     RECT  0.103 10.836 0.139 10.854 ;
     RECT  0.103 12.456 0.535 12.474 ;
     RECT  1.723 2.232 2.16 2.25 ;
     RECT  1.399 4.194 2.16 4.212 ;
     RECT  0.139 10.836 2.16 11.394 ;
     RECT  0.535 12.366 2.16 12.474 ;
     RECT  0.535 18.198 2.16 18.216 ;
     RECT  0.535 21.906 2.16 21.924 ;
     RECT  2.16 2.151 2.911 23.769 ;
     RECT  2.911 2.034 4.703 23.769 ;
     RECT  4.703 2.151 5.503 23.769 ;
     RECT  5.503 2.106 6.107 23.769 ;
     RECT  6.107 2.151 7.735 23.769 ;
     RECT  7.771 0.036 7.943 0.054 ;
     RECT  7.735 2.106 7.979 23.769 ;
     RECT  12.955 25.866 13.055 25.884 ;
     RECT  22.603 0.036 22.739 0.054 ;
     RECT  22.639 25.866 22.739 25.884 ;
     RECT  28.363 25.866 28.463 25.884 ;
     RECT  7.979 2.151 39.307 23.769 ;
     RECT  39.307 2.106 42.151 23.769 ;
     RECT  42.151 1.728 42.323 23.769 ;
     RECT  42.323 2.106 48.847 23.769 ;
     RECT  48.847 2.07 49.631 23.769 ;
     RECT  49.631 2.106 49.847 23.769 ;
     RECT  50.251 0.036 50.351 0.054 ;
     RECT  51.943 0.036 52.043 0.054 ;
     RECT  55.291 25.866 55.391 25.884 ;
     RECT  49.847 2.151 55.903 23.769 ;
     RECT  55.903 2.106 56.651 23.769 ;
     RECT  56.651 2.151 58.459 23.769 ;
     RECT  58.459 1.728 58.703 23.769 ;
     RECT  58.703 2.151 64.975 23.769 ;
     RECT  64.975 0.036 65.111 0.054 ;
     RECT  64.975 2.106 65.615 23.769 ;
     RECT  72.571 25.866 72.743 25.884 ;
     RECT  65.615 2.151 75.559 23.769 ;
     RECT  75.559 2.106 76.199 23.769 ;
     RECT  76.199 2.151 77.251 23.769 ;
     RECT  77.251 2.106 77.819 23.769 ;
     RECT  77.971 0.036 78.071 0.054 ;
     RECT  77.819 2.151 81.175 23.769 ;
     RECT  81.175 2.106 81.815 23.769 ;
     RECT  81.815 2.151 90.859 23.769 ;
     RECT  90.859 1.728 91.103 23.769 ;
     RECT  91.103 2.151 92.479 23.769 ;
     RECT  92.479 1.728 92.723 23.769 ;
     RECT  92.723 2.106 93.515 23.769 ;
     RECT  93.515 2.151 99.427 23.769 ;
     RECT  99.427 2.151 99.671 23.922 ;
     RECT  99.671 2.151 112.063 23.769 ;
     RECT  112.063 2.106 112.307 23.769 ;
     RECT  112.307 2.151 126.535 23.769 ;
     RECT  126.535 2.151 126.635 23.922 ;
     RECT  126.635 2.151 138.163 23.769 ;
     RECT  138.163 1.728 138.407 23.769 ;
     RECT  138.407 2.151 149.04 23.769 ;
     RECT  149.04 9.9 149.207 9.918 ;
     RECT  149.04 19.35 149.207 19.368 ;
     RECT  149.04 13.068 149.315 13.086 ;
     RECT  149.04 3.888 149.351 3.978 ;
     RECT  149.04 16.074 149.351 16.092 ;
     RECT  149.04 21.24 149.351 21.258 ;
     RECT  149.04 20.16 149.387 20.178 ;
     RECT  149.04 2.196 149.459 2.628 ;
     RECT  149.04 5.04 149.531 5.796 ;
     RECT  149.04 22.212 149.747 23.616 ;
     RECT  149.459 2.196 149.819 2.214 ;
     RECT  149.351 3.888 149.891 3.906 ;
     RECT  149.531 5.778 149.891 5.796 ;
     RECT  149.04 6.66 149.891 6.678 ;
     RECT  149.04 7.74 149.891 7.758 ;
     RECT  149.04 8.82 149.891 8.838 ;
     RECT  149.04 11.952 149.891 11.97 ;
     RECT  149.04 13.95 149.891 13.968 ;
     RECT  149.04 15.03 149.891 15.048 ;
     RECT  149.04 17.082 149.891 17.1 ;
     RECT  149.747 23.13 149.891 23.616 ;
     RECT  149.747 22.212 149.927 22.23 ;
     RECT  149.891 23.13 150.467 23.148 ;
     RECT  149.04 10.872 151.115 10.89 ;
     RECT  149.04 18.162 151.115 18.18 ;
    LAYER M3 ;
     RECT  52.02 0.059 52.038 0.091 ;
     RECT  65.088 0.059 65.106 0.091 ;
     RECT  7.776 0.059 7.794 0.571 ;
     RECT  1.404 1.099 1.746 1.339 ;
     RECT  1.404 1.339 3.042 1.579 ;
     RECT  1.404 1.579 3.438 1.723 ;
     RECT  59.256 0.091 59.274 1.723 ;
     RECT  77.976 0.059 77.994 1.723 ;
     RECT  90.216 0.571 90.234 1.723 ;
     RECT  91.08 0.571 91.818 1.723 ;
     RECT  138.384 0.571 139.122 1.723 ;
     RECT  49.5 1.723 49.518 2.065 ;
     RECT  50.256 0.059 50.274 2.065 ;
     RECT  1.404 1.723 3.87 2.101 ;
     RECT  4.644 2.029 4.698 2.101 ;
     RECT  5.508 1.723 5.526 2.101 ;
     RECT  7.38 0.571 7.794 2.101 ;
     RECT  39.708 0.091 39.726 2.101 ;
     RECT  54.54 0.091 55.242 2.101 ;
     RECT  56.016 0.091 56.034 2.101 ;
     RECT  65.088 0.091 65.79 2.101 ;
     RECT  75.6 0.091 75.618 2.101 ;
     RECT  80.568 0.091 81.306 2.101 ;
     RECT  82.044 0.091 82.062 2.101 ;
     RECT  90.216 1.723 92.718 2.101 ;
     RECT  93.492 0.571 93.51 2.101 ;
     RECT  13.608 0.091 13.626 2.143 ;
     RECT  18.468 0.091 18.486 2.143 ;
     RECT  30.06 0.091 30.762 2.143 ;
     RECT  35.028 1.723 35.658 2.143 ;
     RECT  38.916 2.101 39.726 2.143 ;
     RECT  51.156 0.091 51.174 2.143 ;
     RECT  62.532 0.091 62.55 2.143 ;
     RECT  67.464 1.723 67.482 2.143 ;
     RECT  72.36 1.723 72.378 2.143 ;
     RECT  77.256 1.723 77.994 2.143 ;
     RECT  83.772 1.723 83.79 2.143 ;
     RECT  87.804 1.723 88.434 2.143 ;
     RECT  90.216 2.101 93.51 2.143 ;
     RECT  94.356 1.723 94.914 2.143 ;
     RECT  104.904 0.571 104.922 2.143 ;
     RECT  105.768 1.723 106.362 2.143 ;
     RECT  110.664 1.723 111.222 2.143 ;
     RECT  116.352 0.571 116.37 2.143 ;
     RECT  120.42 1.723 121.05 2.143 ;
     RECT  125.316 0.571 126.054 2.143 ;
     RECT  136.728 0.571 137.394 2.143 ;
     RECT  138.168 1.723 139.122 2.143 ;
     RECT  141.624 1.723 142.218 2.143 ;
     RECT  1.404 2.101 4.698 2.191 ;
     RECT  5.508 2.101 6.318 2.191 ;
     RECT  7.38 2.101 7.974 2.191 ;
     RECT  8.892 0.091 9.558 2.191 ;
     RECT  10.476 0.091 11.214 2.191 ;
     RECT  16.848 0.091 16.866 2.191 ;
     RECT  22.716 0.059 22.734 2.191 ;
     RECT  23.688 0.091 24.246 2.191 ;
     RECT  26.64 0.091 26.658 2.191 ;
     RECT  33.156 0.091 33.174 2.191 ;
     RECT  34.815 2.143 35.658 2.191 ;
     RECT  36.396 0.091 36.414 2.191 ;
     RECT  38.16 0.091 38.178 2.191 ;
     RECT  38.916 2.143 40.554 2.191 ;
     RECT  42.156 1.723 42.318 2.191 ;
     RECT  45.432 2.143 45.705 2.191 ;
     RECT  47.808 0.571 47.826 2.191 ;
     RECT  48.672 2.065 50.274 2.191 ;
     RECT  51.015 2.143 51.174 2.191 ;
     RECT  54.54 2.101 56.862 2.191 ;
     RECT  57.636 0.091 57.654 2.191 ;
     RECT  58.464 1.723 59.274 2.191 ;
     RECT  60.876 1.723 60.894 2.191 ;
     RECT  61.74 2.143 62.55 2.191 ;
     RECT  68.256 0.091 68.958 2.191 ;
     RECT  70.884 1.723 71.55 2.191 ;
     RECT  72.36 2.143 73.17 2.191 ;
     RECT  73.944 0.091 73.962 2.191 ;
     RECT  75.564 2.101 76.41 2.191 ;
     RECT  77.256 2.143 78.105 2.191 ;
     RECT  78.84 0.091 78.858 2.191 ;
     RECT  80.568 2.101 82.062 2.191 ;
     RECT  82.944 2.143 83.79 2.191 ;
     RECT  109.008 1.723 109.602 2.191 ;
     RECT  110.415 2.143 111.222 2.191 ;
     RECT  112.068 2.101 112.302 2.191 ;
     RECT  133.488 1.723 134.082 2.191 ;
     RECT  135.108 1.723 135.738 2.191 ;
     RECT  144.9 1.723 145.53 2.191 ;
     RECT  146.52 1.723 147.078 2.191 ;
     RECT  148.14 2.143 148.305 2.191 ;
     RECT  149.436 1.483 149.814 2.219 ;
     RECT  7.272 2.191 11.214 2.227 ;
     RECT  11.952 0.091 11.97 2.227 ;
     RECT  47.052 2.191 51.174 2.227 ;
     RECT  52.02 0.091 52.722 2.227 ;
     RECT  53.568 2.191 57.654 2.227 ;
     RECT  64.152 0.091 64.17 2.227 ;
     RECT  70.884 2.191 73.17 2.227 ;
     RECT  73.944 2.191 74.79 2.227 ;
     RECT  144.9 2.191 148.305 2.227 ;
     RECT  149.436 2.219 149.454 2.227 ;
     RECT  1.404 2.191 6.318 2.255 ;
     RECT  84.564 1.723 85.194 2.255 ;
     RECT  90.216 2.143 94.914 2.255 ;
     RECT  102.492 0.571 103.194 2.255 ;
     RECT  109.008 2.191 112.302 2.255 ;
     RECT  113.904 0.571 114.642 2.255 ;
     RECT  118.008 0.571 118.026 2.255 ;
     RECT  118.8 1.723 119.394 2.255 ;
     RECT  122.076 1.723 122.67 2.255 ;
     RECT  130.212 1.723 130.842 2.255 ;
     RECT  133.488 2.191 135.738 2.255 ;
     RECT  136.728 2.143 139.122 2.255 ;
     RECT  144.144 1.723 144.162 2.255 ;
     RECT  14.436 2.191 14.49 2.263 ;
     RECT  15.228 0.091 15.246 2.263 ;
     RECT  20.16 0.091 20.178 2.263 ;
     RECT  25.056 1.723 25.074 2.263 ;
     RECT  26.64 2.191 26.694 2.263 ;
     RECT  28.332 1.723 28.35 2.263 ;
     RECT  32.364 2.191 33.174 2.263 ;
     RECT  41.832 2.191 42.894 2.263 ;
     RECT  43.632 2.191 43.83 2.263 ;
     RECT  45.216 2.191 46.278 2.263 ;
     RECT  47.052 2.227 57.654 2.263 ;
     RECT  144.9 2.227 149.454 2.263 ;
     RECT  84.564 2.255 84.978 2.291 ;
     RECT  97.596 1.723 98.154 2.291 ;
     RECT  100.872 1.723 101.502 2.291 ;
     RECT  122.076 2.255 122.418 2.291 ;
     RECT  123.696 1.723 124.29 2.291 ;
     RECT  127.764 0.571 127.782 2.291 ;
     RECT  130.212 2.255 130.554 2.291 ;
     RECT  140.832 0.571 140.85 2.291 ;
     RECT  12.816 2.143 13.626 2.299 ;
     RECT  41.832 2.263 43.83 2.299 ;
     RECT  45.072 2.263 57.654 2.299 ;
     RECT  64.98 2.101 65.79 2.299 ;
     RECT  66.636 2.143 67.482 2.299 ;
     RECT  68.256 2.191 69.894 2.299 ;
     RECT  12.816 2.299 13.698 2.335 ;
     RECT  14.436 2.263 15.246 2.335 ;
     RECT  18.468 2.143 19.35 2.335 ;
     RECT  20.16 2.263 20.97 2.335 ;
     RECT  21.78 0.091 21.798 2.335 ;
     RECT  22.716 2.191 24.246 2.335 ;
     RECT  25.056 2.263 25.866 2.335 ;
     RECT  26.64 2.263 28.35 2.335 ;
     RECT  29.124 2.143 30.762 2.335 ;
     RECT  31.536 0.091 31.554 2.335 ;
     RECT  32.292 2.263 33.174 2.335 ;
     RECT  34.02 2.191 36.414 2.335 ;
     RECT  37.26 2.191 40.554 2.335 ;
     RECT  41.328 2.299 43.83 2.335 ;
     RECT  44.604 2.299 57.654 2.335 ;
     RECT  97.992 2.291 98.154 2.335 ;
     RECT  99.252 1.723 99.846 2.335 ;
     RECT  2.304 2.255 6.318 2.371 ;
     RECT  7.272 2.227 11.97 2.371 ;
     RECT  12.816 2.335 15.246 2.371 ;
     RECT  16.092 2.191 16.866 2.371 ;
     RECT  17.712 2.335 57.654 2.371 ;
     RECT  58.464 2.191 62.55 2.371 ;
     RECT  63.36 2.227 64.17 2.371 ;
     RECT  64.98 2.299 69.894 2.371 ;
     RECT  70.776 2.227 74.79 2.371 ;
     RECT  75.564 2.191 78.858 2.371 ;
     RECT  79.668 2.191 83.79 2.371 ;
     RECT  86.184 1.723 86.814 2.371 ;
     RECT  87.804 2.143 89.478 2.371 ;
     RECT  90.216 2.255 90.486 2.371 ;
     RECT  96.804 1.723 96.822 2.371 ;
     RECT  97.992 2.335 99.846 2.371 ;
     RECT  101.232 2.291 101.502 2.371 ;
     RECT  102.492 2.255 102.798 2.371 ;
     RECT  104.904 2.143 106.362 2.371 ;
     RECT  107.388 1.723 107.982 2.371 ;
     RECT  109.008 2.255 109.314 2.371 ;
     RECT  111.744 2.255 112.302 2.371 ;
     RECT  113.076 0.571 113.094 2.371 ;
     RECT  115.524 2.143 116.37 2.371 ;
     RECT  118.8 2.255 119.07 2.371 ;
     RECT  120.42 2.143 121.305 2.371 ;
     RECT  124.02 2.291 124.29 2.371 ;
     RECT  125.316 2.143 126.99 2.371 ;
     RECT  129.384 0.571 129.402 2.371 ;
     RECT  131.832 1.723 132.462 2.371 ;
     RECT  133.488 2.255 133.758 2.371 ;
     RECT  136.728 2.255 138.726 2.371 ;
     RECT  141.624 2.143 143.262 2.371 ;
     RECT  2.304 2.371 84.15 2.489 ;
     RECT  85.716 2.371 90.486 2.489 ;
     RECT  93.024 2.255 94.698 2.489 ;
     RECT  95.508 2.371 95.994 2.489 ;
     RECT  96.804 2.371 97.074 2.489 ;
     RECT  104.904 2.371 108.198 2.489 ;
     RECT  111.744 2.371 113.598 2.489 ;
     RECT  117.108 2.371 117.198 2.489 ;
     RECT  124.02 2.371 124.47 2.489 ;
     RECT  128.916 2.371 129.402 2.489 ;
     RECT  131.364 2.371 133.758 2.489 ;
     RECT  141.12 2.371 143.262 2.489 ;
     RECT  2.304 2.489 16.11 2.525 ;
     RECT  17.1 2.489 70.362 2.525 ;
     RECT  71.316 2.489 84.15 2.525 ;
     RECT  71.568 2.525 84.15 2.561 ;
     RECT  17.1 2.525 17.766 2.597 ;
     RECT  71.568 2.561 84.078 2.633 ;
     RECT  144.36 2.263 149.454 2.633 ;
     RECT  97.992 2.371 99.99 2.641 ;
     RECT  101.232 2.371 101.574 2.641 ;
     RECT  102.42 2.371 102.798 2.641 ;
     RECT  103.644 2.371 104.13 2.641 ;
     RECT  104.904 2.489 106.902 2.641 ;
     RECT  107.64 2.489 108.198 2.641 ;
     RECT  108.936 2.371 109.314 2.641 ;
     RECT  114.696 2.371 116.37 2.641 ;
     RECT  125.244 2.371 126.99 2.641 ;
     RECT  139.5 2.371 140.022 2.641 ;
     RECT  142.704 2.489 143.262 2.641 ;
     RECT  25.164 2.525 27.594 2.759 ;
     RECT  11.664 2.525 16.11 2.795 ;
     RECT  18.54 2.525 23.022 2.831 ;
     RECT  33.48 2.525 35.73 2.831 ;
     RECT  18.615 2.831 23.022 2.939 ;
     RECT  93.78 2.489 94.698 2.939 ;
     RECT  107.64 2.641 109.314 2.957 ;
     RECT  118.296 2.371 119.07 3.001 ;
     RECT  122.4 2.291 122.418 3.001 ;
     RECT  123.192 2.371 123.21 3.001 ;
     RECT  134.496 2.255 135.378 3.001 ;
     RECT  136.26 2.371 138.726 3.001 ;
     RECT  139.5 2.641 140.202 3.001 ;
     RECT  118.296 3.001 119.178 3.037 ;
     RECT  119.916 2.371 121.59 3.037 ;
     RECT  122.4 3.001 123.21 3.037 ;
     RECT  108.504 2.957 109.314 3.065 ;
     RECT  109.116 3.065 109.314 3.073 ;
     RECT  110.124 2.255 110.754 3.073 ;
     RECT  113.22 2.489 113.598 3.073 ;
     RECT  114.696 2.641 116.622 3.073 ;
     RECT  128.052 2.371 128.07 3.145 ;
     RECT  128.916 2.489 128.934 3.145 ;
     RECT  25.272 2.759 26.766 3.173 ;
     RECT  84.96 2.291 84.978 3.181 ;
     RECT  85.716 2.489 88.074 3.181 ;
     RECT  88.815 2.489 90.486 3.181 ;
     RECT  92.196 2.255 92.214 3.181 ;
     RECT  93.024 2.489 93.042 3.181 ;
     RECT  95.508 2.489 95.526 3.181 ;
     RECT  113.22 3.073 113.814 3.181 ;
     RECT  114.624 3.073 116.622 3.181 ;
     RECT  117.432 2.641 117.45 3.181 ;
     RECT  118.296 3.037 123.21 3.181 ;
     RECT  84.96 3.181 88.074 3.245 ;
     RECT  11.772 2.795 16.11 3.271 ;
     RECT  36.54 2.525 70.362 3.271 ;
     RECT  71.568 2.633 84.006 3.271 ;
     RECT  124.02 2.489 124.038 3.271 ;
     RECT  124.776 2.641 127.206 3.271 ;
     RECT  131.364 2.489 133.002 3.271 ;
     RECT  133.74 2.489 133.758 3.271 ;
     RECT  134.496 3.001 135.486 3.271 ;
     RECT  136.26 3.001 140.202 3.271 ;
     RECT  141.12 2.489 141.966 3.271 ;
     RECT  142.704 2.641 143.478 3.271 ;
     RECT  25.272 3.173 26.694 3.299 ;
     RECT  28.44 2.525 30.834 3.299 ;
     RECT  101.232 2.641 102.798 3.299 ;
     RECT  109.116 3.073 110.754 3.299 ;
     RECT  141.12 3.271 143.478 3.299 ;
     RECT  144.36 2.633 149.346 3.299 ;
     RECT  2.304 2.525 8.55 3.307 ;
     RECT  9.468 2.525 10.926 3.307 ;
     RECT  31.752 2.525 32.31 3.307 ;
     RECT  33.516 2.831 35.73 3.343 ;
     RECT  36.54 3.271 84.006 3.343 ;
     RECT  111.744 2.489 112.122 3.343 ;
     RECT  113.22 3.181 116.622 3.343 ;
     RECT  2.304 3.307 10.926 3.371 ;
     RECT  11.772 3.271 16.218 3.371 ;
     RECT  97.056 2.489 97.074 3.379 ;
     RECT  97.992 2.641 100.314 3.379 ;
     RECT  109.908 3.299 110.754 3.379 ;
     RECT  124.02 3.271 127.206 3.379 ;
     RECT  128.052 3.145 128.934 3.379 ;
     RECT  129.672 2.641 129.69 3.379 ;
     RECT  134.496 3.271 140.202 3.379 ;
     RECT  17.748 2.597 17.766 3.403 ;
     RECT  86.004 3.245 88.074 3.403 ;
     RECT  88.815 3.181 90.666 3.403 ;
     RECT  33.516 3.343 84.006 3.407 ;
     RECT  35.928 3.407 84.006 3.415 ;
     RECT  84.96 3.245 85.086 3.415 ;
     RECT  111.744 3.343 116.622 3.415 ;
     RECT  117.432 3.181 123.21 3.415 ;
     RECT  124.02 3.379 129.69 3.415 ;
     RECT  130.536 2.291 130.554 3.415 ;
     RECT  131.364 3.271 133.758 3.415 ;
     RECT  134.496 3.379 140.922 3.415 ;
     RECT  11.772 3.371 15.894 3.437 ;
     RECT  101.232 3.299 101.718 3.437 ;
     RECT  109.116 3.299 109.134 3.437 ;
     RECT  35.928 3.415 85.086 3.443 ;
     RECT  141.66 3.299 143.478 3.443 ;
     RECT  96.264 2.641 96.282 3.451 ;
     RECT  97.056 3.379 100.314 3.451 ;
     RECT  102.6 3.299 102.798 3.451 ;
     RECT  103.644 2.641 106.902 3.451 ;
     RECT  109.908 3.379 110.79 3.451 ;
     RECT  111.744 3.415 123.21 3.451 ;
     RECT  124.02 3.415 140.922 3.451 ;
     RECT  141.732 3.443 143.478 3.451 ;
     RECT  144.216 3.415 144.234 3.451 ;
     RECT  11.772 3.437 11.79 3.541 ;
     RECT  27.576 2.759 27.594 3.569 ;
     RECT  33.516 3.407 35.154 3.569 ;
     RECT  35.928 3.443 68.922 3.569 ;
     RECT  92.196 3.181 93.042 3.569 ;
     RECT  144.972 3.299 149.346 3.569 ;
     RECT  91.404 2.255 91.422 3.595 ;
     RECT  149.328 3.569 149.346 3.595 ;
     RECT  36.072 3.569 46.818 3.605 ;
     RECT  69.84 3.443 85.086 3.605 ;
     RECT  109.908 3.451 140.922 3.605 ;
     RECT  86.004 3.403 90.666 3.629 ;
     RECT  2.304 3.371 10.638 3.641 ;
     RECT  17.424 3.403 17.766 3.649 ;
     RECT  18.615 2.939 21.006 3.649 ;
     RECT  95.436 3.181 95.526 3.649 ;
     RECT  96.264 3.451 100.458 3.649 ;
     RECT  17.424 3.649 21.006 3.676 ;
     RECT  21.78 2.939 23.022 3.685 ;
     RECT  23.76 2.525 24.39 3.685 ;
     RECT  93.78 2.939 94.662 3.685 ;
     RECT  95.436 3.649 100.458 3.685 ;
     RECT  107.64 2.957 107.658 3.685 ;
     RECT  31.752 3.307 32.742 3.691 ;
     RECT  33.516 3.569 35.097 3.691 ;
     RECT  92.808 3.569 93.042 3.691 ;
     RECT  93.78 3.685 100.458 3.691 ;
     RECT  61.74 3.569 68.922 3.713 ;
     RECT  81.072 3.605 85.086 3.713 ;
     RECT  109.908 3.605 114.966 3.713 ;
     RECT  21.78 3.685 24.39 3.721 ;
     RECT  28.584 3.299 30.834 3.721 ;
     RECT  31.752 3.691 35.097 3.721 ;
     RECT  90.504 3.629 90.666 3.721 ;
     RECT  91.404 3.595 91.782 3.721 ;
     RECT  92.808 3.691 100.458 3.749 ;
     RECT  115.815 3.605 140.922 3.749 ;
     RECT  102.6 3.451 106.902 3.811 ;
     RECT  107.64 3.685 107.874 3.811 ;
     RECT  28.584 3.721 35.097 3.839 ;
     RECT  69.84 3.605 80.298 3.839 ;
     RECT  93.744 3.749 100.458 3.839 ;
     RECT  102.6 3.811 107.874 3.839 ;
     RECT  110.052 3.713 114.966 3.839 ;
     RECT  38.232 3.605 46.818 3.869 ;
     RECT  135.936 3.749 140.922 3.869 ;
     RECT  25.272 3.299 26.622 3.875 ;
     RECT  27.612 3.835 27.63 3.875 ;
     RECT  47.7 3.569 60.894 3.875 ;
     RECT  63.864 3.713 68.922 3.875 ;
     RECT  70.596 3.839 73.422 3.875 ;
     RECT  111.708 3.839 114.966 3.875 ;
     RECT  115.815 3.749 128.394 3.875 ;
     RECT  36.072 3.605 37.386 3.911 ;
     RECT  38.304 3.869 46.818 3.911 ;
     RECT  93.744 3.839 100.242 3.911 ;
     RECT  110.052 3.839 110.79 3.911 ;
     RECT  111.708 3.875 114.894 3.911 ;
     RECT  149.328 3.595 149.886 3.911 ;
     RECT  0.108 3.787 0.126 3.917 ;
     RECT  17.424 3.676 21.042 3.917 ;
     RECT  129.132 3.749 135.198 3.917 ;
     RECT  136.044 3.869 140.922 3.917 ;
     RECT  54.432 3.875 60.894 3.947 ;
     RECT  21.78 3.721 24.498 3.955 ;
     RECT  115.815 3.875 125.082 3.983 ;
     RECT  129.132 3.917 134.874 3.983 ;
     RECT  136.476 3.917 140.922 3.983 ;
     RECT  141.732 3.451 144.234 3.983 ;
     RECT  144.972 3.569 148.497 3.983 ;
     RECT  149.328 3.911 149.526 3.983 ;
     RECT  17.568 3.917 21.042 3.991 ;
     RECT  21.78 3.955 24.894 3.991 ;
     RECT  101.232 3.437 101.25 3.991 ;
     RECT  92.808 3.749 93.006 4.013 ;
     RECT  102.6 3.839 103.41 4.013 ;
     RECT  63.9 3.875 68.922 4.019 ;
     RECT  90.504 3.721 91.782 4.019 ;
     RECT  111.708 3.911 114.786 4.019 ;
     RECT  104.22 3.839 107.874 4.072 ;
     RECT  104.22 4.072 108.018 4.081 ;
     RECT  108.936 3.991 109.026 4.081 ;
     RECT  142.2 3.983 144.234 4.081 ;
     RECT  12.6 3.437 15.894 4.109 ;
     RECT  17.568 3.991 24.894 4.109 ;
     RECT  28.944 3.839 35.097 4.109 ;
     RECT  36.828 3.911 37.386 4.109 ;
     RECT  39.996 3.911 46.818 4.109 ;
     RECT  84.672 3.713 85.086 4.109 ;
     RECT  86.004 3.629 89.73 4.109 ;
     RECT  111.852 4.019 114.786 4.109 ;
     RECT  115.815 3.983 119.142 4.109 ;
     RECT  125.964 3.875 128.394 4.109 ;
     RECT  129.132 3.983 132.426 4.109 ;
     RECT  136.476 3.983 138.978 4.115 ;
     RECT  85.068 4.109 85.086 4.117 ;
     RECT  86.004 4.109 87.246 4.117 ;
     RECT  12.6 4.109 14.994 4.145 ;
     RECT  25.668 3.875 26.622 4.145 ;
     RECT  81.072 3.713 83.898 4.145 ;
     RECT  125.964 4.109 127.53 4.145 ;
     RECT  139.752 3.983 140.922 4.145 ;
     RECT  102.6 4.013 103.338 4.153 ;
     RECT  10.548 3.641 10.638 4.157 ;
     RECT  111.852 4.109 111.87 4.157 ;
     RECT  36.936 4.109 37.386 4.181 ;
     RECT  82.116 4.145 83.898 4.181 ;
     RECT  1.404 2.255 1.422 4.217 ;
     RECT  18.36 4.109 24.894 4.217 ;
     RECT  66.708 4.019 68.922 4.217 ;
     RECT  117 4.109 119.142 4.217 ;
     RECT  18.36 4.217 24.678 4.253 ;
     RECT  10.62 4.157 10.638 4.261 ;
     RECT  11.412 3.541 11.79 4.261 ;
     RECT  26.604 4.145 26.622 4.261 ;
     RECT  66.78 4.217 68.922 4.261 ;
     RECT  69.84 3.839 69.858 4.261 ;
     RECT  102.24 4.153 103.338 4.261 ;
     RECT  104.22 4.081 109.026 4.261 ;
     RECT  140.58 4.145 140.922 4.261 ;
     RECT  2.304 3.641 9.81 4.267 ;
     RECT  10.62 4.261 11.79 4.289 ;
     RECT  15.804 4.109 15.894 4.289 ;
     RECT  85.068 4.117 87.246 4.289 ;
     RECT  129.996 4.109 132.426 4.289 ;
     RECT  133.236 3.983 134.874 4.289 ;
     RECT  142.2 4.081 144.63 4.289 ;
     RECT  10.8 4.289 11.79 4.379 ;
     RECT  18.615 4.253 24.678 4.379 ;
     RECT  66.78 4.261 69.858 4.379 ;
     RECT  82.188 4.181 83.898 4.379 ;
     RECT  90.504 4.019 91.422 4.379 ;
     RECT  101.052 3.991 101.25 4.379 ;
     RECT  104.22 4.261 109.242 4.379 ;
     RECT  123.444 3.983 125.082 4.379 ;
     RECT  12.6 4.145 14.202 4.387 ;
     RECT  45.432 4.109 46.818 4.387 ;
     RECT  82.188 4.379 83.697 4.397 ;
     RECT  10.8 4.379 11.718 4.415 ;
     RECT  18.615 4.379 22.194 4.415 ;
     RECT  39.996 4.109 44.586 4.415 ;
     RECT  47.7 3.875 53.334 4.415 ;
     RECT  70.704 3.875 73.422 4.415 ;
     RECT  85.464 4.289 87.246 4.415 ;
     RECT  104.328 4.379 109.242 4.415 ;
     RECT  124.596 4.379 125.082 4.415 ;
     RECT  130.788 4.289 132.426 4.415 ;
     RECT  140.58 4.261 141.39 4.415 ;
     RECT  54.432 3.947 60.138 4.451 ;
     RECT  93.744 3.911 96.246 4.451 ;
     RECT  45.432 4.387 46.854 4.459 ;
     RECT  60.876 3.947 60.894 4.459 ;
     RECT  61.74 3.713 62.802 4.459 ;
     RECT  2.268 4.267 9.81 4.487 ;
     RECT  21.636 4.415 22.194 4.487 ;
     RECT  26.604 4.261 26.802 4.487 ;
     RECT  29.088 4.109 35.097 4.487 ;
     RECT  60.876 4.459 62.802 4.487 ;
     RECT  120.168 3.983 122.706 4.487 ;
     RECT  134.028 4.289 134.874 4.487 ;
     RECT  143.82 4.289 144.63 4.487 ;
     RECT  52.416 4.415 53.334 4.493 ;
     RECT  40.032 4.415 44.586 4.523 ;
     RECT  54.432 4.451 54.63 4.523 ;
     RECT  60.876 4.487 62.766 4.523 ;
     RECT  63.9 4.019 65.97 4.523 ;
     RECT  117.72 4.217 119.142 4.523 ;
     RECT  120.168 4.487 122.634 4.523 ;
     RECT  137.34 4.115 138.978 4.523 ;
     RECT  102.168 4.261 103.338 4.531 ;
     RECT  10.8 4.415 10.818 4.559 ;
     RECT  12.564 4.387 14.202 4.559 ;
     RECT  42.948 4.523 44.37 4.559 ;
     RECT  45.432 4.459 46.926 4.559 ;
     RECT  55.584 4.451 57.222 4.559 ;
     RECT  61.776 4.523 62.766 4.559 ;
     RECT  66.78 4.379 69.066 4.559 ;
     RECT  93.744 4.451 94.662 4.559 ;
     RECT  120.168 4.523 122.418 4.559 ;
     RECT  74.304 3.839 79.902 4.589 ;
     RECT  74.484 4.589 79.902 4.621 ;
     RECT  81.072 4.145 81.342 4.621 ;
     RECT  65.016 4.523 65.97 4.649 ;
     RECT  67.068 4.559 69.066 4.649 ;
     RECT  74.484 4.621 81.342 4.649 ;
     RECT  126.216 4.145 127.53 4.649 ;
     RECT  58.356 4.451 60.138 4.685 ;
     RECT  70.704 4.415 73.278 4.685 ;
     RECT  74.484 4.649 81.198 4.685 ;
     RECT  122.292 4.559 122.418 4.685 ;
     RECT  2.304 4.487 9.81 4.757 ;
     RECT  106.02 4.415 109.242 4.792 ;
     RECT  61.776 4.559 62.55 4.793 ;
     RECT  97.056 3.911 100.242 4.793 ;
     RECT  106.02 4.792 109.278 4.793 ;
     RECT  137.34 4.523 138.114 4.793 ;
     RECT  125.064 4.415 125.082 4.801 ;
     RECT  74.556 4.685 81.198 4.919 ;
     RECT  82.188 4.397 82.674 4.925 ;
     RECT  18.615 4.415 20.682 4.955 ;
     RECT  74.556 4.919 77.238 4.955 ;
     RECT  112.608 4.109 114.786 4.955 ;
     RECT  70.704 4.685 73.242 4.973 ;
     RECT  70.704 4.973 73.206 4.991 ;
     RECT  74.7 4.955 77.238 4.991 ;
     RECT  82.188 4.925 82.602 5.021 ;
     RECT  38.304 3.911 39.222 5.027 ;
     RECT  68.796 4.649 69.066 5.027 ;
     RECT  78.015 4.919 81.198 5.027 ;
     RECT  70.812 4.991 70.902 5.063 ;
     RECT  74.916 4.991 77.238 5.063 ;
     RECT  82.26 5.021 82.602 5.063 ;
     RECT  149.508 3.983 149.526 5.063 ;
     RECT  2.304 4.757 9.054 5.099 ;
     RECT  71.784 4.991 73.17 5.099 ;
     RECT  78.015 5.027 79.542 5.099 ;
     RECT  74.916 5.063 75.078 5.117 ;
     RECT  47.7 4.415 51.39 5.161 ;
     RECT  52.416 4.493 52.434 5.161 ;
     RECT  115.815 4.109 116.097 5.161 ;
     RECT  71.784 5.099 73.134 5.189 ;
     RECT  77.04 5.063 77.238 5.189 ;
     RECT  19.944 4.955 20.682 5.213 ;
     RECT  6.372 5.099 9.054 5.225 ;
     RECT  71.784 5.189 73.062 5.225 ;
     RECT  77.04 5.189 77.202 5.225 ;
     RECT  82.296 5.063 82.602 5.225 ;
     RECT  126.54 4.649 127.53 5.225 ;
     RECT  80.28 5.027 81.198 5.261 ;
     RECT  82.476 5.225 82.602 5.261 ;
     RECT  43.776 4.559 44.37 5.297 ;
     RECT  47.7 5.161 52.434 5.297 ;
     RECT  92.988 4.013 93.006 5.305 ;
     RECT  93.744 4.559 94.497 5.305 ;
     RECT  92.988 5.305 94.497 5.333 ;
     RECT  117.72 4.523 119.106 5.333 ;
     RECT  45.504 4.559 46.782 5.341 ;
     RECT  97.848 4.793 100.242 5.341 ;
     RECT  101.052 4.379 101.07 5.341 ;
     RECT  58.356 4.685 58.482 5.431 ;
     RECT  59.4 4.685 60.138 5.431 ;
     RECT  106.272 4.793 109.278 5.431 ;
     RECT  110.052 3.911 110.697 5.431 ;
     RECT  144.612 4.487 144.63 5.431 ;
     RECT  145.476 3.983 148.497 5.431 ;
     RECT  10.836 5.161 10.854 5.459 ;
     RECT  48.744 5.297 52.434 5.459 ;
     RECT  6.408 5.225 9.054 5.495 ;
     RECT  125.064 4.801 125.442 5.501 ;
     RECT  48.888 5.459 52.434 5.503 ;
     RECT  115.704 5.161 116.097 5.503 ;
     RECT  129.132 4.109 129.15 5.531 ;
     RECT  48.888 5.503 52.578 5.539 ;
     RECT  53.316 4.493 53.334 5.539 ;
     RECT  80.892 5.261 81.198 5.539 ;
     RECT  54.648 5.503 54.666 5.603 ;
     RECT  144.612 5.431 148.497 5.741 ;
     RECT  10.8 5.701 10.818 5.773 ;
     RECT  149.868 5.659 149.886 5.801 ;
     RECT  10.764 5.773 10.818 5.837 ;
     RECT  58.356 5.431 60.138 5.845 ;
     RECT  60.876 4.523 60.894 5.845 ;
     RECT  79.128 5.099 79.542 5.873 ;
     RECT  79.236 5.873 79.542 5.881 ;
     RECT  41.652 4.523 42.21 5.909 ;
     RECT  119.088 5.333 119.106 5.971 ;
     RECT  120.168 4.559 121.497 5.971 ;
     RECT  10.764 5.837 10.782 5.999 ;
     RECT  79.236 5.881 79.686 5.999 ;
     RECT  144.612 5.741 144.63 5.999 ;
     RECT  78.015 5.099 78.297 6.007 ;
     RECT  45.504 5.341 46.854 6.071 ;
     RECT  106.272 5.431 110.697 6.079 ;
     RECT  79.236 5.999 79.506 6.107 ;
     RECT  115.704 5.503 116.55 6.107 ;
     RECT  104.328 4.415 105.297 6.115 ;
     RECT  106.2 6.079 110.697 6.115 ;
     RECT  117.72 5.333 118.026 6.115 ;
     RECT  119.088 5.971 121.497 6.115 ;
     RECT  44.136 5.297 44.37 6.143 ;
     RECT  2.304 5.099 5.562 6.151 ;
     RECT  46.836 6.071 46.854 6.151 ;
     RECT  75.924 5.063 75.942 6.151 ;
     RECT  77.184 5.225 77.202 6.151 ;
     RECT  6.66 5.495 9.054 6.179 ;
     RECT  46.836 6.151 46.926 6.179 ;
     RECT  75.852 6.151 77.202 6.235 ;
     RECT  75.708 6.235 77.202 6.241 ;
     RECT  77.94 6.007 78.297 6.241 ;
     RECT  46.908 6.179 46.926 6.269 ;
     RECT  117.72 6.115 121.497 6.269 ;
     RECT  75.708 6.241 78.297 6.275 ;
     RECT  2.304 6.151 5.778 6.305 ;
     RECT  65.952 4.649 65.97 6.349 ;
     RECT  69.84 4.379 69.858 6.385 ;
     RECT  122.508 6.277 122.526 6.413 ;
     RECT  3.564 6.305 5.778 6.475 ;
     RECT  65.808 6.349 65.97 6.511 ;
     RECT  67.068 4.649 68.022 6.511 ;
     RECT  3.564 6.475 5.994 6.539 ;
     RECT  6.912 6.179 9.054 6.539 ;
     RECT  29.088 4.487 31.77 6.547 ;
     RECT  32.724 4.487 35.097 6.547 ;
     RECT  74.916 5.117 74.934 6.547 ;
     RECT  7.815 6.539 9.054 6.575 ;
     RECT  117.72 6.269 118.026 6.575 ;
     RECT  102.096 4.531 103.338 6.583 ;
     RECT  104.328 6.115 110.697 6.583 ;
     RECT  97.848 5.341 101.07 6.611 ;
     RECT  145.476 5.741 148.497 6.611 ;
     RECT  65.016 4.649 65.034 6.619 ;
     RECT  45.504 6.071 45.897 6.647 ;
     RECT  137.34 4.793 137.697 6.647 ;
     RECT  61.776 4.793 62.406 6.655 ;
     RECT  112.608 4.955 113.814 6.655 ;
     RECT  126.615 5.225 127.53 6.683 ;
     RECT  74.628 6.547 74.934 6.691 ;
     RECT  44.352 6.143 44.37 6.719 ;
     RECT  48.888 5.539 53.334 6.719 ;
     RECT  149.868 6.655 149.886 6.749 ;
     RECT  111.564 6.655 113.814 6.781 ;
     RECT  3.564 6.539 5.526 6.809 ;
     RECT  15.876 4.289 15.894 6.817 ;
     RECT  65.808 6.511 68.022 6.817 ;
     RECT  70.884 5.063 70.902 6.817 ;
     RECT  73.836 6.691 73.854 6.817 ;
     RECT  130.788 4.415 130.806 6.817 ;
     RECT  131.616 4.415 132.426 6.817 ;
     RECT  15.804 6.817 15.894 6.845 ;
     RECT  58.356 5.845 60.894 6.845 ;
     RECT  70.812 6.817 70.902 6.845 ;
     RECT  117.72 6.575 117.738 6.845 ;
     RECT  130.788 6.817 132.426 6.845 ;
     RECT  75.924 6.275 78.297 6.889 ;
     RECT  79.236 6.107 79.434 6.889 ;
     RECT  73.692 6.817 73.854 6.893 ;
     RECT  75.924 6.889 79.434 6.925 ;
     RECT  6.912 6.539 7.002 6.953 ;
     RECT  54.612 6.925 54.702 6.961 ;
     RECT  48.888 6.719 48.906 6.989 ;
     RECT  136.476 4.115 136.494 6.989 ;
     RECT  54.612 6.961 54.846 7.051 ;
     RECT  70.812 6.845 70.83 7.051 ;
     RECT  49.644 6.719 53.334 7.079 ;
     RECT  73.728 6.893 73.854 7.087 ;
     RECT  74.628 6.691 75.078 7.087 ;
     RECT  82.584 5.261 82.602 7.087 ;
     RECT  80.892 5.539 81.414 7.123 ;
     RECT  68.796 5.027 68.814 7.159 ;
     RECT  54.54 7.051 54.846 7.187 ;
     RECT  75.924 6.925 79.47 7.189 ;
     RECT  80.496 7.123 81.414 7.189 ;
     RECT  73.728 7.087 75.078 7.195 ;
     RECT  75.924 7.189 81.414 7.195 ;
     RECT  54.612 7.187 54.846 7.223 ;
     RECT  73.728 7.195 81.414 7.259 ;
     RECT  49.788 7.079 53.334 7.277 ;
     RECT  54.828 7.223 54.846 7.321 ;
     RECT  55.584 4.559 55.602 7.321 ;
     RECT  2.304 6.305 2.697 7.385 ;
     RECT  73.728 7.259 78.498 7.385 ;
     RECT  69.804 6.385 69.858 7.393 ;
     RECT  70.704 7.051 70.83 7.393 ;
     RECT  49.824 7.277 53.334 7.421 ;
     RECT  54.828 7.321 55.602 7.421 ;
     RECT  73.728 7.385 78.426 7.427 ;
     RECT  71.784 5.225 72.954 7.429 ;
     RECT  2.34 7.385 2.697 7.435 ;
     RECT  115.815 6.107 116.55 7.591 ;
     RECT  5.688 7.501 5.706 7.619 ;
     RECT  6.912 6.953 6.93 7.627 ;
     RECT  7.815 6.575 8.097 7.627 ;
     RECT  82.584 7.087 82.638 7.627 ;
     RECT  83.415 4.397 83.697 7.627 ;
     RECT  2.34 7.435 2.754 7.655 ;
     RECT  125.064 5.501 125.082 7.655 ;
     RECT  71.568 7.429 72.954 7.663 ;
     RECT  73.728 7.427 78.297 7.663 ;
     RECT  138.96 4.523 138.978 7.691 ;
     RECT  69.804 7.393 70.83 7.699 ;
     RECT  71.568 7.663 78.297 7.699 ;
     RECT  128.376 4.109 128.394 7.727 ;
     RECT  114.552 4.955 114.786 7.735 ;
     RECT  115.815 7.591 117.126 7.735 ;
     RECT  117.936 7.663 117.954 7.735 ;
     RECT  117.936 7.735 118.026 7.763 ;
     RECT  149.868 7.723 149.886 7.763 ;
     RECT  3.564 6.809 4.842 7.771 ;
     RECT  5.976 7.627 6.93 7.771 ;
     RECT  81.072 7.259 81.414 7.771 ;
     RECT  82.584 7.627 83.697 7.771 ;
     RECT  7.812 7.627 8.097 7.889 ;
     RECT  46.764 7.771 46.782 7.889 ;
     RECT  49.86 7.421 53.334 7.889 ;
     RECT  79.272 7.259 80.118 7.889 ;
     RECT  81.072 7.771 83.697 7.889 ;
     RECT  118.008 7.763 118.026 7.889 ;
     RECT  49.86 7.889 53.226 7.925 ;
     RECT  81.072 7.889 81.738 7.949 ;
     RECT  5.976 7.771 7.074 7.961 ;
     RECT  52.668 7.925 53.226 7.961 ;
     RECT  111.492 6.781 113.814 7.963 ;
     RECT  114.552 7.735 117.126 7.963 ;
     RECT  54.792 8.005 54.81 8.131 ;
     RECT  80.1 7.889 80.118 8.159 ;
     RECT  52.992 7.961 53.226 8.195 ;
     RECT  111.492 7.963 117.126 8.195 ;
     RECT  49.86 7.925 51.894 8.231 ;
     RECT  69.804 7.699 78.297 8.237 ;
     RECT  52.992 8.195 53.01 8.267 ;
     RECT  134.856 4.487 134.874 8.267 ;
     RECT  76.392 8.237 78.297 8.275 ;
     RECT  49.86 8.231 51.786 8.303 ;
     RECT  133.236 4.289 133.254 8.303 ;
     RECT  54.684 8.131 54.81 8.311 ;
     RECT  55.584 7.421 55.602 8.311 ;
     RECT  76.392 8.275 78.354 8.311 ;
     RECT  143.82 4.487 143.838 8.311 ;
     RECT  12.6 4.559 14.202 8.339 ;
     RECT  54.684 8.311 55.602 8.339 ;
     RECT  7.815 7.889 8.097 8.401 ;
     RECT  8.82 6.575 9.054 8.401 ;
     RECT  49.032 7.501 49.05 8.429 ;
     RECT  54.864 8.339 55.602 8.429 ;
     RECT  76.392 8.311 78.462 8.437 ;
     RECT  79.272 7.889 79.29 8.437 ;
     RECT  5.976 7.961 6.462 8.491 ;
     RECT  2.34 7.655 2.697 8.509 ;
     RECT  3.528 7.771 4.914 8.509 ;
     RECT  119.088 6.269 121.497 8.539 ;
     RECT  2.34 8.509 4.914 8.683 ;
     RECT  69.804 8.237 75.258 8.699 ;
     RECT  76.392 8.437 79.29 8.699 ;
     RECT  7.815 8.401 9.054 8.707 ;
     RECT  13.215 8.339 14.202 8.843 ;
     RECT  149.868 8.779 149.886 8.843 ;
     RECT  2.304 8.683 4.914 8.851 ;
     RECT  5.796 8.491 6.462 8.851 ;
     RECT  7.776 8.707 9.054 8.851 ;
     RECT  2.304 8.851 5.058 8.941 ;
     RECT  5.796 8.851 9.054 8.941 ;
     RECT  22.968 4.379 24.498 8.969 ;
     RECT  76.392 8.699 76.554 8.969 ;
     RECT  77.688 8.699 79.29 8.969 ;
     RECT  118.44 8.539 121.497 9.005 ;
     RECT  2.304 8.941 9.054 9.101 ;
     RECT  22.968 8.969 24.297 9.149 ;
     RECT  25.668 4.145 25.794 9.211 ;
     RECT  26.604 4.487 26.622 9.211 ;
     RECT  111.492 8.195 113.814 9.211 ;
     RECT  114.552 8.195 117.126 9.211 ;
     RECT  25.668 9.211 26.622 9.239 ;
     RECT  111.492 9.211 117.126 9.311 ;
     RECT  25.776 9.239 26.622 9.383 ;
     RECT  10.764 9.121 10.782 9.419 ;
     RECT  13.215 8.843 13.95 9.419 ;
     RECT  77.688 8.969 78.426 9.419 ;
     RECT  102.096 6.583 110.697 9.437 ;
     RECT  26.172 9.383 26.622 9.509 ;
     RECT  55.584 8.429 55.602 9.517 ;
     RECT  23.328 9.149 24.297 9.545 ;
     RECT  49.86 8.303 51.297 9.545 ;
     RECT  134.028 4.487 134.046 9.545 ;
     RECT  111.672 9.311 117.126 9.553 ;
     RECT  26.208 9.509 26.622 9.581 ;
     RECT  141.372 4.415 141.39 9.581 ;
     RECT  123.444 4.379 123.462 9.617 ;
     RECT  77.688 9.419 78.354 9.653 ;
     RECT  29.088 6.547 35.097 9.689 ;
     RECT  26.604 9.581 26.622 9.751 ;
     RECT  26.604 9.751 26.766 9.779 ;
     RECT  129.996 4.289 130.014 9.815 ;
     RECT  145.62 6.611 148.497 9.835 ;
     RECT  14.976 4.145 14.994 9.851 ;
     RECT  2.304 9.101 6.966 9.859 ;
     RECT  111.672 9.553 117.45 9.887 ;
     RECT  27.792 3.991 27.81 9.895 ;
     RECT  27.792 9.895 27.918 9.923 ;
     RECT  145.62 9.835 149.202 9.923 ;
     RECT  11.7 4.415 11.718 9.959 ;
     RECT  56.34 4.559 57.222 10.021 ;
     RECT  27.9 9.923 27.918 10.049 ;
     RECT  49.86 9.545 50.238 10.049 ;
     RECT  145.62 9.923 148.497 10.049 ;
     RECT  26.748 9.779 26.766 10.085 ;
     RECT  140.58 4.415 140.598 10.085 ;
     RECT  97.848 6.611 97.866 10.093 ;
     RECT  98.712 6.611 101.07 10.093 ;
     RECT  76.392 8.969 76.41 10.319 ;
     RECT  111.672 9.887 114.678 10.319 ;
     RECT  111.672 10.319 114.57 10.355 ;
     RECT  2.304 9.859 7.038 10.399 ;
     RECT  7.776 9.101 9.054 10.399 ;
     RECT  36.072 3.911 36.09 10.561 ;
     RECT  29.088 9.689 31.77 10.589 ;
     RECT  9.792 4.757 9.81 10.697 ;
     RECT  115.815 9.887 117.45 10.895 ;
     RECT  151.092 10.843 151.11 10.895 ;
     RECT  143.82 8.311 144.486 10.931 ;
     RECT  102.096 9.437 105.57 10.975 ;
     RECT  106.344 9.437 110.697 10.975 ;
     RECT  111.672 10.355 114.354 10.975 ;
     RECT  130.788 6.845 132.297 11.003 ;
     RECT  10.8 10.939 10.818 11.011 ;
     RECT  38.88 5.027 39.222 11.101 ;
     RECT  10.8 11.011 10.89 11.129 ;
     RECT  85.608 4.415 87.246 11.129 ;
     RECT  36.936 4.181 37.134 11.137 ;
     RECT  38.268 11.101 39.222 11.137 ;
     RECT  54.972 9.517 55.602 11.137 ;
     RECT  56.34 10.021 57.438 11.137 ;
     RECT  50.148 10.049 50.238 11.165 ;
     RECT  32.688 9.689 35.097 11.173 ;
     RECT  15.804 6.845 15.822 11.237 ;
     RECT  36 10.561 36.09 11.245 ;
     RECT  0.108 10.831 0.126 11.281 ;
     RECT  102.096 10.975 114.354 11.309 ;
     RECT  115.815 10.895 116.55 11.309 ;
     RECT  2.304 10.399 9.054 11.371 ;
     RECT  32.688 11.173 35.154 11.435 ;
     RECT  2.268 11.371 9.054 11.471 ;
     RECT  10.8 11.129 10.854 11.507 ;
     RECT  117.432 10.895 117.45 11.579 ;
     RECT  81.072 7.949 81.09 11.669 ;
     RECT  130.788 11.003 130.806 11.669 ;
     RECT  84.492 11.641 84.942 11.693 ;
     RECT  2.268 11.471 8.982 11.705 ;
     RECT  40.032 4.523 40.734 11.713 ;
     RECT  84.924 11.693 84.942 11.741 ;
     RECT  36.936 11.137 39.222 11.749 ;
     RECT  40.032 11.713 41.238 11.749 ;
     RECT  142.2 4.289 143.097 11.777 ;
     RECT  13.215 9.419 13.497 11.803 ;
     RECT  24.015 9.545 24.297 11.803 ;
     RECT  45.615 6.647 45.897 11.803 ;
     RECT  13.104 11.803 13.497 11.849 ;
     RECT  23.904 11.803 24.297 11.849 ;
     RECT  34.704 11.435 35.154 11.849 ;
     RECT  45.504 11.803 45.897 11.849 ;
     RECT  50.148 11.165 50.166 11.911 ;
     RECT  2.304 11.705 8.982 11.939 ;
     RECT  32.688 11.435 33.966 11.939 ;
     RECT  10.836 11.507 10.854 11.975 ;
     RECT  149.868 11.899 149.886 11.975 ;
     RECT  34.815 11.849 35.154 12.055 ;
     RECT  36 11.245 36.162 12.055 ;
     RECT  102.096 11.309 110.754 12.055 ;
     RECT  111.672 11.309 114.354 12.055 ;
     RECT  82.584 7.889 83.697 12.187 ;
     RECT  95.436 4.451 96.246 12.187 ;
     RECT  97.056 4.793 97.074 12.187 ;
     RECT  81.252 11.995 81.522 12.209 ;
     RECT  139.752 4.145 139.77 12.209 ;
     RECT  54.972 11.137 57.438 12.289 ;
     RECT  82.584 12.187 83.79 12.317 ;
     RECT  32.688 11.939 32.814 12.325 ;
     RECT  65.772 6.817 68.022 12.325 ;
     RECT  68.796 7.159 68.886 12.325 ;
     RECT  69.804 8.699 75.15 12.361 ;
     RECT  32.652 12.325 32.814 12.365 ;
     RECT  69.66 12.361 75.15 12.389 ;
     RECT  81.252 12.209 81.27 12.389 ;
     RECT  95.436 12.187 97.074 12.389 ;
     RECT  65.772 12.325 68.886 12.479 ;
     RECT  95.436 12.389 96.462 12.479 ;
     RECT  58.356 6.845 58.41 12.487 ;
     RECT  59.148 6.845 60.894 12.487 ;
     RECT  65.772 12.479 67.842 12.515 ;
     RECT  69.66 12.389 70.83 12.515 ;
     RECT  64.836 6.619 65.034 12.523 ;
     RECT  85.932 11.129 87.246 12.523 ;
     RECT  10.8 12.361 10.818 12.551 ;
     RECT  97.848 10.093 101.07 12.551 ;
     RECT  116.82 11.677 116.838 12.551 ;
     RECT  50.04 11.911 50.166 12.559 ;
     RECT  51.015 9.545 51.297 12.559 ;
     RECT  58.356 12.487 60.894 12.559 ;
     RECT  61.776 6.655 62.982 12.559 ;
     RECT  64.692 12.523 65.034 12.559 ;
     RECT  65.772 12.515 67.77 12.559 ;
     RECT  42.192 5.909 42.21 12.571 ;
     RECT  45.615 11.849 45.897 12.571 ;
     RECT  46.656 11.677 46.674 12.571 ;
     RECT  0.108 11.281 0.558 12.605 ;
     RECT  50.04 12.559 52.002 12.605 ;
     RECT  33.588 11.939 33.966 12.631 ;
     RECT  34.815 12.055 36.162 12.631 ;
     RECT  102.096 12.055 114.354 12.631 ;
     RECT  63.9 4.523 63.918 12.698 ;
     RECT  64.692 12.559 67.77 12.698 ;
     RECT  2.415 11.939 3.906 12.721 ;
     RECT  4.716 11.939 8.982 12.721 ;
     RECT  63.9 12.698 67.77 12.749 ;
     RECT  100.836 12.551 101.07 12.749 ;
     RECT  64.836 12.749 67.77 12.785 ;
     RECT  54.72 12.289 57.438 12.793 ;
     RECT  58.356 12.559 62.982 12.793 ;
     RECT  2.415 12.721 8.982 12.811 ;
     RECT  100.944 12.749 101.07 12.821 ;
     RECT  26.784 12.631 26.802 12.829 ;
     RECT  63.9 12.749 64.098 12.829 ;
     RECT  102.096 12.631 114.714 12.829 ;
     RECT  85.5 12.523 87.246 12.859 ;
     RECT  102.096 12.829 114.75 12.859 ;
     RECT  24.015 11.849 24.297 12.865 ;
     RECT  33.588 12.631 36.162 12.901 ;
     RECT  36.936 11.749 41.238 12.901 ;
     RECT  53.856 8.851 53.874 12.901 ;
     RECT  54.684 12.793 57.438 12.901 ;
     RECT  58.248 12.793 62.982 12.901 ;
     RECT  63.756 12.829 64.098 12.901 ;
     RECT  53.856 12.901 57.438 12.929 ;
     RECT  58.212 12.901 64.098 12.955 ;
     RECT  71.604 12.389 75.15 12.991 ;
     RECT  102.024 12.859 114.75 12.991 ;
     RECT  115.815 11.309 116.097 12.991 ;
     RECT  58.176 12.955 64.098 13.019 ;
     RECT  64.836 12.785 67.497 13.019 ;
     RECT  68.616 12.479 68.886 13.019 ;
     RECT  85.032 12.859 87.246 13.019 ;
     RECT  58.176 13.019 63.774 13.055 ;
     RECT  68.688 13.019 68.886 13.055 ;
     RECT  69.696 12.515 70.83 13.055 ;
     RECT  71.604 12.991 75.222 13.055 ;
     RECT  23.904 12.865 24.297 13.063 ;
     RECT  95.436 12.479 96.246 13.063 ;
     RECT  0.54 12.605 0.558 13.085 ;
     RECT  71.676 13.055 75.222 13.085 ;
     RECT  76.752 12.811 76.77 13.085 ;
     RECT  58.176 13.055 63.27 13.091 ;
     RECT  149.292 12.955 149.31 13.091 ;
     RECT  32.688 12.365 32.814 13.135 ;
     RECT  32.508 13.135 32.814 13.147 ;
     RECT  33.588 12.901 41.238 13.147 ;
     RECT  61.56 13.091 63.27 13.181 ;
     RECT  77.688 9.653 78.297 13.289 ;
     RECT  29.124 10.589 31.77 13.297 ;
     RECT  77.904 13.289 78.297 13.297 ;
     RECT  79.272 8.969 79.29 13.297 ;
     RECT  32.508 13.147 41.238 13.325 ;
     RECT  58.176 13.091 60.678 13.325 ;
     RECT  82.584 12.317 83.697 13.325 ;
     RECT  26.748 12.829 26.802 13.369 ;
     RECT  129.384 12.865 129.402 13.369 ;
     RECT  28.98 13.297 31.77 13.373 ;
     RECT  86.04 13.019 87.246 13.387 ;
     RECT  88.092 4.109 89.73 13.387 ;
     RECT  65.772 13.019 67.497 13.397 ;
     RECT  42.192 12.571 42.786 13.405 ;
     RECT  47.7 5.297 47.718 13.405 ;
     RECT  132.015 11.003 132.297 13.405 ;
     RECT  13.215 11.849 13.497 13.432 ;
     RECT  77.904 13.297 79.29 13.433 ;
     RECT  2.304 12.811 8.982 13.441 ;
     RECT  20.268 5.213 20.682 13.441 ;
     RECT  42.192 13.405 42.822 13.441 ;
     RECT  13.104 13.432 13.497 13.469 ;
     RECT  67.104 13.397 67.497 13.469 ;
     RECT  77.904 13.433 78.297 13.469 ;
     RECT  45.615 12.571 46.674 13.531 ;
     RECT  47.7 13.405 47.79 13.531 ;
     RECT  97.848 12.551 99.897 13.531 ;
     RECT  101.952 12.991 114.75 13.531 ;
     RECT  115.815 12.991 116.55 13.531 ;
     RECT  33.66 13.325 41.238 13.559 ;
     RECT  45.615 13.531 47.79 13.559 ;
     RECT  86.04 13.387 89.73 13.559 ;
     RECT  143.892 10.931 144.486 13.559 ;
     RECT  22.176 4.487 22.194 13.567 ;
     RECT  118.836 9.005 121.497 13.567 ;
     RECT  137.415 6.647 137.697 13.567 ;
     RECT  42.012 13.441 42.822 13.595 ;
     RECT  47.376 13.559 47.79 13.595 ;
     RECT  97.416 13.531 99.897 13.603 ;
     RECT  146.484 10.049 148.497 13.603 ;
     RECT  45.615 13.559 46.602 13.613 ;
     RECT  54.036 12.929 57.438 13.613 ;
     RECT  86.04 13.559 87.318 13.613 ;
     RECT  101.952 13.531 116.55 13.613 ;
     RECT  26.748 13.369 26.91 13.631 ;
     RECT  47.376 13.595 47.718 13.631 ;
     RECT  26.748 13.631 26.802 13.667 ;
     RECT  32.508 13.325 32.814 13.667 ;
     RECT  42.192 13.595 42.246 13.667 ;
     RECT  50.04 12.605 51.297 13.667 ;
     RECT  61.776 13.181 63.27 13.667 ;
     RECT  118.62 13.567 121.497 13.667 ;
     RECT  92.196 4.387 92.214 13.675 ;
     RECT  93.168 5.333 94.497 13.675 ;
     RECT  95.328 13.063 96.246 13.675 ;
     RECT  142.02 13.135 142.038 13.675 ;
     RECT  142.815 11.777 143.097 13.675 ;
     RECT  95.328 13.675 96.354 13.711 ;
     RECT  97.272 13.603 99.897 13.711 ;
     RECT  118.62 13.667 119.682 13.801 ;
     RECT  95.328 13.711 99.897 13.829 ;
     RECT  115.38 13.613 116.55 13.829 ;
     RECT  120.564 13.667 121.497 13.829 ;
     RECT  142.02 13.675 143.097 13.829 ;
     RECT  47.556 13.631 47.718 13.865 ;
     RECT  55.008 13.613 57.438 13.865 ;
     RECT  86.04 13.613 87.246 13.865 ;
     RECT  92.196 13.675 94.497 13.873 ;
     RECT  95.328 13.829 96.354 13.873 ;
     RECT  121.215 13.829 121.497 13.909 ;
     RECT  92.196 13.873 96.354 13.973 ;
     RECT  101.952 13.613 114.606 13.973 ;
     RECT  118.116 13.801 119.682 13.981 ;
     RECT  149.868 13.945 149.886 13.997 ;
     RECT  92.196 13.973 96.318 14.009 ;
     RECT  102.024 13.973 114.606 14.009 ;
     RECT  115.704 13.829 116.55 14.101 ;
     RECT  81.036 14.071 81.054 14.107 ;
     RECT  50.04 13.667 50.058 14.135 ;
     RECT  80.856 14.107 81.054 14.144 ;
     RECT  115.704 14.101 116.694 14.207 ;
     RECT  117.756 13.981 119.682 14.215 ;
     RECT  81.036 14.144 81.054 14.237 ;
     RECT  13.215 13.469 13.497 14.245 ;
     RECT  97.128 13.829 99.897 14.251 ;
     RECT  100.944 12.821 100.962 14.251 ;
     RECT  117.684 14.215 119.682 14.251 ;
     RECT  13.215 14.245 13.59 14.285 ;
     RECT  83.016 13.325 83.697 14.347 ;
     RECT  16.776 14.071 16.794 14.369 ;
     RECT  79.272 13.433 79.29 14.369 ;
     RECT  92.196 14.009 96.102 14.369 ;
     RECT  97.128 14.251 100.962 14.369 ;
     RECT  102.204 14.009 114.606 14.369 ;
     RECT  145.62 10.049 145.638 14.377 ;
     RECT  117.612 14.251 119.682 14.441 ;
     RECT  117.612 14.441 118.098 14.477 ;
     RECT  115.74 14.207 116.694 14.485 ;
     RECT  100.944 14.369 100.962 14.521 ;
     RECT  82.656 14.347 83.697 14.525 ;
     RECT  79.2 14.443 79.218 14.549 ;
     RECT  102.42 14.369 114.606 14.549 ;
     RECT  119.124 14.441 119.682 14.639 ;
     RECT  86.328 13.865 87.246 14.647 ;
     RECT  100.944 14.521 101.142 14.647 ;
     RECT  117.684 14.477 118.098 14.711 ;
     RECT  86.148 14.647 87.246 14.717 ;
     RECT  100.944 14.647 101.214 14.783 ;
     RECT  119.664 14.639 119.682 14.783 ;
     RECT  88.092 13.559 89.73 14.819 ;
     RECT  117.684 14.711 117.99 14.819 ;
     RECT  97.128 14.369 99.99 14.881 ;
     RECT  142.02 13.829 142.038 14.917 ;
     RECT  115.74 14.485 116.874 14.953 ;
     RECT  96.912 14.881 99.99 14.957 ;
     RECT  88.704 14.819 89.73 14.989 ;
     RECT  90.504 4.379 91.242 14.989 ;
     RECT  88.704 14.989 91.242 15.017 ;
     RECT  149.868 15.016 149.886 15.053 ;
     RECT  45.615 13.613 45.897 15.061 ;
     RECT  91.224 15.017 91.242 15.061 ;
     RECT  92.196 14.369 96.066 15.061 ;
     RECT  121.215 13.909 122.13 15.151 ;
     RECT  130.572 12.829 130.59 15.163 ;
     RECT  121.104 15.151 122.13 15.197 ;
     RECT  102.42 14.549 114.354 15.223 ;
     RECT  29.124 13.373 31.77 15.251 ;
     RECT  133.704 13.945 133.722 15.259 ;
     RECT  130.536 15.163 130.59 15.293 ;
     RECT  102.348 15.223 114.354 15.295 ;
     RECT  115.704 14.953 116.874 15.323 ;
     RECT  2.304 13.441 9.054 15.359 ;
     RECT  91.224 15.061 96.066 15.359 ;
     RECT  91.836 15.359 92.538 15.449 ;
     RECT  96.912 14.957 99.897 15.449 ;
     RECT  86.616 14.717 87.246 15.451 ;
     RECT  102.348 15.295 114.57 15.529 ;
     RECT  142.815 13.829 143.097 15.565 ;
     RECT  143.892 13.559 143.91 15.565 ;
     RECT  13.215 14.285 13.497 15.592 ;
     RECT  23.904 13.063 24.894 15.592 ;
     RECT  45.615 15.061 46.602 15.592 ;
     RECT  67.176 13.469 67.497 15.592 ;
     RECT  78.015 13.469 78.297 15.592 ;
     RECT  83.016 14.525 83.697 15.595 ;
     RECT  86.616 15.451 87.822 15.601 ;
     RECT  88.704 15.017 90.234 15.601 ;
     RECT  134.964 15.529 134.982 15.601 ;
     RECT  13.104 15.592 13.497 15.629 ;
     RECT  23.868 15.592 24.894 15.629 ;
     RECT  45.504 15.592 46.602 15.629 ;
     RECT  67.104 15.592 67.497 15.629 ;
     RECT  77.904 15.592 78.297 15.629 ;
     RECT  142.815 15.565 143.91 15.629 ;
     RECT  82.656 15.595 83.697 15.691 ;
     RECT  100.944 14.783 101.142 15.691 ;
     RECT  102.096 15.529 114.57 15.691 ;
     RECT  137.415 13.567 138.33 15.691 ;
     RECT  86.616 15.601 90.234 15.719 ;
     RECT  88.668 15.719 90.234 15.728 ;
     RECT  82.656 15.691 84.078 15.773 ;
     RECT  86.616 15.719 87.318 15.773 ;
     RECT  100.944 15.691 114.57 15.787 ;
     RECT  96.912 15.449 98.046 15.821 ;
     RECT  100.62 15.787 114.57 15.827 ;
     RECT  101.16 15.827 114.57 15.863 ;
     RECT  146.412 13.603 148.497 15.869 ;
     RECT  86.616 15.773 87.246 15.871 ;
     RECT  88.704 15.728 90.234 15.899 ;
     RECT  101.16 15.863 113.598 16.025 ;
     RECT  86.292 15.871 87.246 16.061 ;
     RECT  149.328 16.069 149.346 16.109 ;
     RECT  82.728 15.773 83.697 16.133 ;
     RECT  2.412 15.359 9.054 16.141 ;
     RECT  92.52 15.449 92.538 16.141 ;
     RECT  93.384 15.359 96.066 16.141 ;
     RECT  115.704 15.323 116.097 16.141 ;
     RECT  112.68 16.025 113.598 16.259 ;
     RECT  2.376 16.141 9.054 16.267 ;
     RECT  10.8 16.105 10.818 16.267 ;
     RECT  86.76 16.061 87.246 16.301 ;
     RECT  0.108 16.219 0.126 16.349 ;
     RECT  112.68 16.259 112.734 16.367 ;
     RECT  10.764 16.267 10.818 16.403 ;
     RECT  97.128 15.821 98.046 16.411 ;
     RECT  98.784 15.449 99.897 16.411 ;
     RECT  10.8 16.403 10.818 16.439 ;
     RECT  113.508 16.259 113.598 16.529 ;
     RECT  87.228 16.301 87.246 16.541 ;
     RECT  101.16 16.025 111.942 16.573 ;
     RECT  137.376 15.691 138.33 16.645 ;
     RECT  146.556 15.869 148.497 16.681 ;
     RECT  97.128 16.411 99.897 16.709 ;
     RECT  113.544 16.529 113.598 16.771 ;
     RECT  114.336 15.863 114.57 16.771 ;
     RECT  20.016 13.441 20.682 16.807 ;
     RECT  36.936 13.559 41.238 16.843 ;
     RECT  42.192 13.667 42.21 16.843 ;
     RECT  113.544 16.771 114.57 16.871 ;
     RECT  126.615 6.683 126.897 16.891 ;
     RECT  36.936 16.843 42.21 16.907 ;
     RECT  145.044 14.377 145.638 16.915 ;
     RECT  146.412 16.681 148.497 16.915 ;
     RECT  92.52 16.141 96.066 17.035 ;
     RECT  97.128 16.709 98.874 17.069 ;
     RECT  126.615 16.891 126.99 17.069 ;
     RECT  92.52 17.035 96.354 17.083 ;
     RECT  97.128 17.069 97.146 17.083 ;
     RECT  88.704 15.899 89.802 17.105 ;
     RECT  149.868 17.077 149.886 17.117 ;
     RECT  2.304 16.267 9.054 17.261 ;
     RECT  32.688 13.667 32.814 17.311 ;
     RECT  97.884 17.069 98.874 17.375 ;
     RECT  117.684 14.819 117.81 17.375 ;
     RECT  19.656 16.807 20.682 17.383 ;
     RECT  21.96 13.567 22.194 17.383 ;
     RECT  32.688 17.311 32.85 17.383 ;
     RECT  32.508 17.383 32.85 17.411 ;
     RECT  58.356 13.325 58.41 17.411 ;
     RECT  88.704 17.105 89.097 17.447 ;
     RECT  32.508 17.411 32.814 17.483 ;
     RECT  37.836 16.907 42.21 17.491 ;
     RECT  32.688 17.483 32.814 17.519 ;
     RECT  92.52 17.083 97.146 17.609 ;
     RECT  100.692 16.573 111.942 17.609 ;
     RECT  92.52 17.609 96.354 17.645 ;
     RECT  100.692 17.609 109.458 17.645 ;
     RECT  17.568 4.109 17.586 17.951 ;
     RECT  100.692 17.645 106.866 17.987 ;
     RECT  32.796 17.519 32.814 18.023 ;
     RECT  2.412 17.261 9.054 18.031 ;
     RECT  86.652 17.851 86.67 18.059 ;
     RECT  88.776 17.447 89.097 18.059 ;
     RECT  2.34 18.031 9.054 18.149 ;
     RECT  151.092 18.139 151.11 18.185 ;
     RECT  97.884 17.375 98.802 18.419 ;
     RECT  15.66 17.959 15.678 18.499 ;
     RECT  37.836 17.491 42.75 18.527 ;
     RECT  97.128 17.609 97.146 18.535 ;
     RECT  37.836 18.527 41.886 18.563 ;
     RECT  145.044 16.915 148.497 18.599 ;
     RECT  33.66 13.559 36.162 18.689 ;
     RECT  92.52 17.645 93.474 18.697 ;
     RECT  94.215 17.645 96.354 18.697 ;
     RECT  97.128 18.535 97.182 18.697 ;
     RECT  100.692 17.987 106.47 18.769 ;
     RECT  123.984 16.681 124.002 18.805 ;
     RECT  83.016 16.133 83.697 18.833 ;
     RECT  2.415 18.149 9.054 18.907 ;
     RECT  91.044 15.763 91.062 18.967 ;
     RECT  90.648 18.967 91.062 19.067 ;
     RECT  13.215 15.629 13.497 19.075 ;
     RECT  33.66 18.689 33.678 19.111 ;
     RECT  92.484 18.697 93.474 19.111 ;
     RECT  29.415 15.251 31.77 19.139 ;
     RECT  0.54 18.193 0.558 19.181 ;
     RECT  146.124 18.599 148.497 19.195 ;
     RECT  92.232 19.111 93.474 19.229 ;
     RECT  98.028 18.419 98.802 19.229 ;
     RECT  100.692 18.769 106.542 19.229 ;
     RECT  88.815 18.059 89.097 19.273 ;
     RECT  104.364 19.229 106.542 19.336 ;
     RECT  104.364 19.336 106.974 19.373 ;
     RECT  146.124 19.195 149.202 19.373 ;
     RECT  29.415 19.139 31.59 19.409 ;
     RECT  112.68 16.367 112.698 19.499 ;
     RECT  110.415 17.609 111.942 19.507 ;
     RECT  71.676 13.085 75.15 19.643 ;
     RECT  2.304 18.907 9.054 19.651 ;
     RECT  9.936 17.455 9.954 19.651 ;
     RECT  106.524 19.373 106.974 19.651 ;
     RECT  107.712 17.645 109.458 19.651 ;
     RECT  37.908 18.563 41.886 19.769 ;
     RECT  106.524 19.651 109.458 19.769 ;
     RECT  2.304 19.651 9.954 19.777 ;
     RECT  51.015 13.667 51.297 19.777 ;
     RECT  94.215 18.697 97.182 19.777 ;
     RECT  98.028 19.229 98.694 19.777 ;
     RECT  36.936 16.907 36.954 19.805 ;
     RECT  38.808 19.769 41.886 19.805 ;
     RECT  121.215 15.197 122.13 19.813 ;
     RECT  2.304 19.777 10.422 19.841 ;
     RECT  29.415 19.409 30.618 19.841 ;
     RECT  106.524 19.769 109.278 19.949 ;
     RECT  92.484 19.229 93.474 20.039 ;
     RECT  100.692 19.229 103.338 20.039 ;
     RECT  106.524 19.949 108.27 20.039 ;
     RECT  99.615 16.709 99.897 20.047 ;
     RECT  100.692 20.039 101.07 20.047 ;
     RECT  101.808 20.039 103.338 20.155 ;
     RECT  104.364 19.373 105.714 20.155 ;
     RECT  31.572 19.409 31.59 20.191 ;
     RECT  94.215 19.777 98.694 20.191 ;
     RECT  99.615 20.047 101.07 20.191 ;
     RECT  101.808 20.155 105.714 20.191 ;
     RECT  119.736 17.959 119.754 20.191 ;
     RECT  38.808 19.805 40.95 20.219 ;
     RECT  59.148 13.325 60.678 20.219 ;
     RECT  106.56 20.039 108.27 20.219 ;
     RECT  149.364 20.155 149.382 20.237 ;
     RECT  38.88 20.219 39.438 20.309 ;
     RECT  101.808 20.191 105.786 20.309 ;
     RECT  51.015 19.777 51.39 20.317 ;
     RECT  33.084 19.111 33.678 20.345 ;
     RECT  40.215 20.219 40.878 20.345 ;
     RECT  14.508 17.419 14.526 20.353 ;
     RECT  45.615 15.629 46.602 20.389 ;
     RECT  34.452 18.689 36.162 20.417 ;
     RECT  102.024 20.309 105.786 20.429 ;
     RECT  2.304 19.841 9.054 20.489 ;
     RECT  82.008 20.281 82.026 20.621 ;
     RECT  86.076 20.425 86.094 20.635 ;
     RECT  19.656 17.383 22.194 20.759 ;
     RECT  85.788 20.635 86.094 20.821 ;
     RECT  102.024 20.429 105.462 20.849 ;
     RECT  85.608 20.821 86.094 20.861 ;
     RECT  106.56 20.219 107.694 20.965 ;
     RECT  110.415 19.507 112.59 20.965 ;
     RECT  29.415 19.841 29.697 21.091 ;
     RECT  31.572 20.191 31.95 21.091 ;
     RECT  42.732 18.527 42.75 21.091 ;
     RECT  109.08 19.949 109.278 21.091 ;
     RECT  27.72 13.027 27.738 21.115 ;
     RECT  141.48 14.917 142.038 21.115 ;
     RECT  142.815 15.629 143.658 21.115 ;
     RECT  47.7 13.865 47.718 21.119 ;
     RECT  2.34 20.489 9.054 21.127 ;
     RECT  9.936 19.841 10.422 21.127 ;
     RECT  94.215 20.191 101.07 21.127 ;
     RECT  110.415 20.965 112.626 21.127 ;
     RECT  34.452 20.417 35.478 21.155 ;
     RECT  71.676 19.643 74.934 21.155 ;
     RECT  30.6 19.841 30.618 21.163 ;
     RECT  41.868 19.805 41.886 21.163 ;
     RECT  42.732 21.091 42.786 21.163 ;
     RECT  41.868 21.163 42.786 21.199 ;
     RECT  45.615 20.389 46.818 21.199 ;
     RECT  54.036 13.613 54.054 21.199 ;
     RECT  55.008 13.865 56.697 21.199 ;
     RECT  58.356 17.411 58.374 21.199 ;
     RECT  59.148 20.219 59.562 21.199 ;
     RECT  90.72 19.067 91.062 21.199 ;
     RECT  29.124 21.091 29.697 21.235 ;
     RECT  88.815 19.273 89.622 21.235 ;
     RECT  90.648 21.199 91.062 21.235 ;
     RECT  92.484 20.039 93.33 21.235 ;
     RECT  108.864 21.091 109.278 21.235 ;
     RECT  31.572 21.091 32.202 21.271 ;
     RECT  33.084 20.345 33.102 21.271 ;
     RECT  43.992 17.995 44.01 21.271 ;
     RECT  92.052 21.235 93.33 21.271 ;
     RECT  141.48 21.115 143.658 21.271 ;
     RECT  149.328 21.235 149.346 21.293 ;
     RECT  45.615 21.199 47.502 21.299 ;
     RECT  54.036 21.199 56.697 21.299 ;
     RECT  2.34 21.127 10.422 21.355 ;
     RECT  119.088 20.191 119.754 21.361 ;
     RECT  120.564 19.813 122.13 21.361 ;
     RECT  123.984 18.805 124.722 21.361 ;
     RECT  117.792 17.375 117.81 21.389 ;
     RECT  119.088 21.361 122.13 21.389 ;
     RECT  123.912 21.361 124.722 21.389 ;
     RECT  30.492 21.163 30.618 21.397 ;
     RECT  31.572 21.271 33.102 21.397 ;
     RECT  88.815 21.235 91.062 21.397 ;
     RECT  91.98 21.271 93.33 21.397 ;
     RECT  116.856 15.323 116.874 21.397 ;
     RECT  123.912 21.389 124.002 21.397 ;
     RECT  123.732 21.397 124.002 21.437 ;
     RECT  41.868 21.199 42.858 21.469 ;
     RECT  116.856 21.397 117.018 21.469 ;
     RECT  86.076 20.861 86.094 21.505 ;
     RECT  88.815 21.397 93.33 21.505 ;
     RECT  94.068 21.127 101.07 21.505 ;
     RECT  106.308 20.965 107.694 21.505 ;
     RECT  141.48 21.271 143.73 21.505 ;
     RECT  13.068 19.075 13.497 21.541 ;
     RECT  14.22 20.353 14.526 21.541 ;
     RECT  36.36 21.127 36.378 21.541 ;
     RECT  37.908 19.769 37.926 21.541 ;
     RECT  38.952 20.309 39.438 21.541 ;
     RECT  40.215 20.345 40.806 21.541 ;
     RECT  41.76 21.469 42.858 21.541 ;
     RECT  43.848 21.271 44.01 21.541 ;
     RECT  58.356 21.199 59.562 21.541 ;
     RECT  83.088 18.833 83.697 21.541 ;
     RECT  108.72 21.235 109.278 21.541 ;
     RECT  110.34 21.127 112.626 21.541 ;
     RECT  25.776 13.369 25.794 21.631 ;
     RECT  50.58 20.317 51.39 21.631 ;
     RECT  57.42 13.865 57.438 21.631 ;
     RECT  58.356 21.541 59.886 21.631 ;
     RECT  60.66 20.219 60.678 21.631 ;
     RECT  61.815 13.667 63.27 21.631 ;
     RECT  68.868 13.055 68.886 21.631 ;
     RECT  69.804 13.055 70.83 21.631 ;
     RECT  78.015 15.629 78.297 21.631 ;
     RECT  83.088 21.541 83.718 21.631 ;
     RECT  103.176 20.849 105.462 21.631 ;
     RECT  106.308 21.505 107.766 21.631 ;
     RECT  113.544 16.871 113.562 21.631 ;
     RECT  115.596 16.141 116.097 21.631 ;
     RECT  116.856 21.469 117.162 21.631 ;
     RECT  130.572 15.293 130.59 21.631 ;
     RECT  131.616 13.405 132.297 21.631 ;
     RECT  137.016 16.645 138.33 21.631 ;
     RECT  139.86 21.541 139.878 21.631 ;
     RECT  48.672 18.535 48.69 21.643 ;
     RECT  49.5 19.741 49.518 21.643 ;
     RECT  52.56 13.603 52.578 21.643 ;
     RECT  54.864 21.299 56.697 21.643 ;
     RECT  57.42 21.631 59.886 21.643 ;
     RECT  136.08 21.631 138.33 21.643 ;
     RECT  139.068 21.631 139.086 21.643 ;
     RECT  17.136 21.199 17.154 21.659 ;
     RECT  21.348 20.759 22.194 21.659 ;
     RECT  54.864 21.643 59.886 21.659 ;
     RECT  65.772 13.397 66.186 21.659 ;
     RECT  71.676 21.155 73.206 21.659 ;
     RECT  103.176 21.631 107.766 21.659 ;
     RECT  115.596 21.631 117.162 21.659 ;
     RECT  130.572 21.631 132.39 21.659 ;
     RECT  134.964 15.601 135.342 21.659 ;
     RECT  136.08 21.643 139.086 21.659 ;
     RECT  139.86 21.631 140.166 21.659 ;
     RECT  15.66 18.499 16.146 21.667 ;
     RECT  18.615 4.955 18.897 21.667 ;
     RECT  19.656 20.759 20.034 21.667 ;
     RECT  66.024 21.659 66.186 21.667 ;
     RECT  67.176 15.629 67.497 21.667 ;
     RECT  78.015 21.631 78.786 21.667 ;
     RECT  113.472 21.631 113.562 21.667 ;
     RECT  114.336 16.871 114.57 21.667 ;
     RECT  133.164 15.259 133.722 21.667 ;
     RECT  55.692 21.659 58.014 21.677 ;
     RECT  68.868 21.631 70.83 21.677 ;
     RECT  136.08 21.659 136.458 21.677 ;
     RECT  58.896 21.659 59.886 21.691 ;
     RECT  60.624 21.631 60.678 21.691 ;
     RECT  82.584 21.631 83.718 21.691 ;
     RECT  131.904 21.659 132.39 21.695 ;
     RECT  140.004 21.659 140.166 21.695 ;
     RECT  64.836 13.019 64.854 21.703 ;
     RECT  87.552 21.505 87.57 21.703 ;
     RECT  25.668 21.631 25.794 21.733 ;
     RECT  26.748 13.667 26.766 21.733 ;
     RECT  88.815 21.505 101.07 21.733 ;
     RECT  102.024 20.849 102.042 21.733 ;
     RECT  12.276 16.879 12.294 21.739 ;
     RECT  13.068 21.541 14.526 21.739 ;
     RECT  15.588 21.667 16.146 21.739 ;
     RECT  18.615 21.667 20.034 21.739 ;
     RECT  23.904 15.629 24.894 21.739 ;
     RECT  25.668 21.733 26.766 21.739 ;
     RECT  27.612 21.115 27.738 21.739 ;
     RECT  28.692 21.235 29.697 21.739 ;
     RECT  30.492 21.397 33.102 21.739 ;
     RECT  77.976 21.667 78.786 21.739 ;
     RECT  79.884 21.505 79.902 21.739 ;
     RECT  82.332 21.691 83.718 21.739 ;
     RECT  86.076 21.505 86.562 21.739 ;
     RECT  87.552 21.703 87.606 21.739 ;
     RECT  88.815 21.733 102.042 21.739 ;
     RECT  108.72 21.541 112.626 21.739 ;
     RECT  113.472 21.667 114.57 21.739 ;
     RECT  27.612 21.739 33.354 21.775 ;
     RECT  36.36 21.541 37.926 21.775 ;
     RECT  38.736 21.541 40.806 21.775 ;
     RECT  66.024 21.667 67.497 21.775 ;
     RECT  88.815 21.739 102.294 21.775 ;
     RECT  146.124 19.373 148.497 21.775 ;
     RECT  108.72 21.739 114.57 21.787 ;
     RECT  115.596 21.659 116.154 21.787 ;
     RECT  2.304 21.355 10.422 21.811 ;
     RECT  17.82 21.775 17.838 21.811 ;
     RECT  18.615 21.739 20.862 21.811 ;
     RECT  34.488 21.155 35.478 21.811 ;
     RECT  36.216 21.775 40.806 21.811 ;
     RECT  48.672 21.643 49.518 21.811 ;
     RECT  50.436 21.631 51.39 21.811 ;
     RECT  54.036 21.299 54.054 21.811 ;
     RECT  77.976 21.739 79.902 21.811 ;
     RECT  119.088 21.389 120.258 21.811 ;
     RECT  130.572 21.659 131.058 21.811 ;
     RECT  132.015 21.695 132.39 21.811 ;
     RECT  133.164 21.667 134.01 21.811 ;
     RECT  140.148 21.695 140.166 21.811 ;
     RECT  140.94 21.505 143.73 21.811 ;
     RECT  27.612 21.775 33.75 21.821 ;
     RECT  71.676 21.659 73.062 21.821 ;
     RECT  48.528 21.811 51.498 21.839 ;
     RECT  0.108 21.499 0.126 21.901 ;
     RECT  61.452 21.631 63.27 21.901 ;
     RECT  66.024 21.775 68.058 21.901 ;
     RECT  70.272 21.677 70.83 21.901 ;
     RECT  71.676 21.821 72.954 21.901 ;
     RECT  77.004 15.763 77.022 21.901 ;
     RECT  103.572 21.659 107.766 21.901 ;
     RECT  108.72 21.787 116.154 21.901 ;
     RECT  128.052 17.185 128.07 21.901 ;
     RECT  17.82 21.811 20.862 21.929 ;
     RECT  21.6 21.659 22.194 21.929 ;
     RECT  44.748 18.661 44.766 21.929 ;
     RECT  52.308 21.643 52.578 21.929 ;
     RECT  53.928 21.811 54.054 21.929 ;
     RECT  55.692 21.677 57.942 21.929 ;
     RECT  70.272 21.901 72.954 21.929 ;
     RECT  73.98 21.155 74.934 21.929 ;
     RECT  103.572 21.901 116.154 21.929 ;
     RECT  118.584 21.811 120.258 21.929 ;
     RECT  129.384 13.369 129.51 21.929 ;
     RECT  140.148 21.811 143.73 21.929 ;
     RECT  12.276 21.739 14.526 21.931 ;
     RECT  23.904 21.739 26.766 21.931 ;
     RECT  41.76 21.541 44.01 21.931 ;
     RECT  76.968 21.901 77.022 21.931 ;
     RECT  23.724 21.931 26.766 21.937 ;
     RECT  27.612 21.821 28.206 21.937 ;
     RECT  76.644 21.931 77.022 21.937 ;
     RECT  77.976 21.811 80.37 21.937 ;
     RECT  82.332 21.739 84.15 21.937 ;
     RECT  85.104 21.811 85.122 21.937 ;
     RECT  146.124 21.775 148.59 21.937 ;
     RECT  55.692 21.929 57.186 21.965 ;
     RECT  66.024 21.901 68.094 21.965 ;
     RECT  41.76 21.931 44.586 21.971 ;
     RECT  12.132 21.931 14.526 21.973 ;
     RECT  29.052 21.821 33.75 21.973 ;
     RECT  34.488 21.811 40.806 21.973 ;
     RECT  81.396 21.739 81.486 21.973 ;
     RECT  82.296 21.937 84.15 21.973 ;
     RECT  85.104 21.937 85.266 21.973 ;
     RECT  86.076 21.739 87.606 21.973 ;
     RECT  53.928 21.929 53.946 21.979 ;
     RECT  142.524 21.929 143.73 21.979 ;
     RECT  145.044 18.599 145.062 21.979 ;
     RECT  81.396 21.973 84.15 22.009 ;
     RECT  145.944 21.937 148.59 22.013 ;
     RECT  125.712 13.171 125.73 22.027 ;
     RECT  126.615 17.069 126.897 22.027 ;
     RECT  53.856 21.979 53.946 22.073 ;
     RECT  64.836 21.703 65.286 22.073 ;
     RECT  2.304 21.811 10.458 22.075 ;
     RECT  2.268 22.075 10.458 22.081 ;
     RECT  11.376 21.811 11.394 22.081 ;
     RECT  12.132 21.973 14.634 22.081 ;
     RECT  15.588 21.739 17.01 22.081 ;
     RECT  29.052 21.973 40.806 22.081 ;
     RECT  45.615 21.299 47.466 22.081 ;
     RECT  53.856 22.073 53.874 22.081 ;
     RECT  54.864 21.659 54.882 22.081 ;
     RECT  58.896 21.691 60.678 22.081 ;
     RECT  61.452 21.901 63.522 22.081 ;
     RECT  64.836 22.073 65.214 22.081 ;
     RECT  76.644 21.937 80.37 22.081 ;
     RECT  132.015 21.811 134.01 22.081 ;
     RECT  134.964 21.659 135.018 22.081 ;
     RECT  53.388 22.081 53.874 22.109 ;
     RECT  21.78 21.929 22.194 22.171 ;
     RECT  22.932 21.739 22.95 22.171 ;
     RECT  48.528 21.839 48.69 22.171 ;
     RECT  76.392 22.081 80.37 22.171 ;
     RECT  81.396 22.009 84.222 22.171 ;
     RECT  88.815 21.775 102.654 22.171 ;
     RECT  122.976 17.221 122.994 22.171 ;
     RECT  125.712 22.027 127.134 22.171 ;
     RECT  128.052 21.901 128.61 22.171 ;
     RECT  129.492 21.929 129.51 22.171 ;
     RECT  45.54 22.081 47.61 22.199 ;
     RECT  48.456 22.171 48.69 22.199 ;
     RECT  58.896 22.081 65.214 22.199 ;
     RECT  70.272 21.929 71.694 22.199 ;
     RECT  114.372 21.929 116.154 22.199 ;
     RECT  123.912 21.437 124.002 22.199 ;
     RECT  125.712 22.171 128.61 22.199 ;
     RECT  129.492 22.171 129.654 22.199 ;
     RECT  130.536 21.811 131.058 22.199 ;
     RECT  132.015 22.081 135.018 22.199 ;
     RECT  137.376 21.659 139.086 22.199 ;
     RECT  2.268 22.081 17.01 22.205 ;
     RECT  17.964 21.929 20.862 22.205 ;
     RECT  41.76 21.971 44.01 22.205 ;
     RECT  122.976 22.171 123.066 22.207 ;
     RECT  123.912 22.199 123.93 22.207 ;
     RECT  128.556 22.199 128.61 22.207 ;
     RECT  129.636 22.199 129.654 22.207 ;
     RECT  142.524 21.979 144.126 22.207 ;
     RECT  145.044 21.979 145.206 22.207 ;
     RECT  121.215 21.389 122.13 22.219 ;
     RECT  2.268 22.205 9.054 22.235 ;
     RECT  41.76 22.205 42.102 22.235 ;
     RECT  45.54 22.199 47.574 22.235 ;
     RECT  58.896 22.199 62.37 22.235 ;
     RECT  70.272 22.199 71.55 22.235 ;
     RECT  103.572 21.929 113.598 22.235 ;
     RECT  114.948 22.199 116.154 22.235 ;
     RECT  128.556 22.207 128.718 22.235 ;
     RECT  129.636 22.207 129.798 22.235 ;
     RECT  142.524 22.207 145.35 22.235 ;
     RECT  9.936 22.205 17.01 22.253 ;
     RECT  88.488 22.171 102.654 22.271 ;
     RECT  21.78 22.171 22.95 22.279 ;
     RECT  23.724 21.937 28.206 22.279 ;
     RECT  85.104 21.973 87.606 22.279 ;
     RECT  88.488 22.271 101.898 22.279 ;
     RECT  9.936 22.253 16.938 22.307 ;
     RECT  29.052 22.081 40.878 22.307 ;
     RECT  76.392 22.171 84.222 22.315 ;
     RECT  149.904 22.207 149.922 22.349 ;
     RECT  41.76 22.235 41.958 22.351 ;
     RECT  52.308 21.929 52.47 22.351 ;
     RECT  129.78 22.235 129.798 22.351 ;
     RECT  17.964 22.205 20.826 22.379 ;
     RECT  85.104 22.279 101.898 22.379 ;
     RECT  103.572 22.235 112.482 22.379 ;
     RECT  0.108 21.901 0.558 22.397 ;
     RECT  66.348 21.965 68.094 22.411 ;
     RECT  68.868 21.677 68.886 22.411 ;
     RECT  54.828 22.081 54.882 22.441 ;
     RECT  75.708 22.315 84.222 22.441 ;
     RECT  85.104 22.379 85.554 22.441 ;
     RECT  117.144 21.659 117.162 22.459 ;
     RECT  136.404 21.677 136.458 22.459 ;
     RECT  137.376 22.199 137.754 22.459 ;
     RECT  10.26 22.307 16.902 22.469 ;
     RECT  21.78 22.279 28.206 22.469 ;
     RECT  75.708 22.441 85.554 22.469 ;
     RECT  86.436 22.379 98.01 22.469 ;
     RECT  98.82 22.379 101.898 22.469 ;
     RECT  106.488 22.379 112.482 22.469 ;
     RECT  118.8 21.929 120.258 22.469 ;
     RECT  122.976 22.207 123.93 22.469 ;
     RECT  125.712 22.199 127.458 22.469 ;
     RECT  129.78 22.351 130.158 22.469 ;
     RECT  146.124 22.013 148.59 22.469 ;
     RECT  103.572 22.379 105.714 22.477 ;
     RECT  75.852 22.469 85.554 22.493 ;
     RECT  118.8 22.469 119.142 22.493 ;
     RECT  12.492 22.469 16.902 22.505 ;
     RECT  21.78 22.469 25.362 22.505 ;
     RECT  29.052 22.307 35.694 22.505 ;
     RECT  36.468 22.307 40.878 22.505 ;
     RECT  41.652 22.351 41.958 22.505 ;
     RECT  43.056 22.205 44.01 22.505 ;
     RECT  49.5 21.839 51.498 22.505 ;
     RECT  52.236 22.351 52.47 22.505 ;
     RECT  86.436 22.469 90.306 22.505 ;
     RECT  91.116 22.469 98.01 22.505 ;
     RECT  102.636 22.271 102.654 22.505 ;
     RECT  124.776 22.171 124.794 22.505 ;
     RECT  58.896 22.235 62.298 22.513 ;
     RECT  12.492 22.505 13.497 22.541 ;
     RECT  17.964 22.379 20.79 22.541 ;
     RECT  77.796 22.493 85.554 22.541 ;
     RECT  91.296 22.505 98.01 22.541 ;
     RECT  98.964 22.469 101.898 22.541 ;
     RECT  103.428 22.477 105.714 22.541 ;
     RECT  106.632 22.469 112.482 22.541 ;
     RECT  37.764 22.505 40.878 22.549 ;
     RECT  54.756 22.441 54.882 22.549 ;
     RECT  108.468 22.541 111.69 22.577 ;
     RECT  26.1 22.469 28.206 22.585 ;
     RECT  29.052 22.505 33.102 22.585 ;
     RECT  26.1 22.585 33.102 22.613 ;
     RECT  109.548 22.577 111.69 22.613 ;
     RECT  142.524 22.235 143.694 22.613 ;
     RECT  66.348 22.411 68.886 22.621 ;
     RECT  70.272 22.235 70.83 22.621 ;
     RECT  103.428 22.541 103.842 22.621 ;
     RECT  117.144 22.459 117.45 22.621 ;
     RECT  121.176 22.219 122.13 22.621 ;
     RECT  2.268 22.235 8.73 22.637 ;
     RECT  109.548 22.613 111.51 22.649 ;
     RECT  37.764 22.549 40.986 22.685 ;
     RECT  54.756 22.549 54.954 22.699 ;
     RECT  55.692 21.965 56.754 22.699 ;
     RECT  26.1 22.613 31.698 22.739 ;
     RECT  75.852 22.493 76.986 22.739 ;
     RECT  87.408 22.505 90.306 22.739 ;
     RECT  100.8 22.541 100.926 22.739 ;
     RECT  121.176 22.621 122.31 22.739 ;
     RECT  130.932 22.199 131.058 22.739 ;
     RECT  134.28 22.199 135.018 22.739 ;
     RECT  82.584 22.541 85.554 22.775 ;
     RECT  146.124 22.469 148.497 22.781 ;
     RECT  45.54 22.235 45.897 22.783 ;
     RECT  145.332 22.235 145.35 22.795 ;
     RECT  146.124 22.781 146.502 22.795 ;
     RECT  84.636 22.775 85.554 22.811 ;
     RECT  54.756 22.699 56.754 22.819 ;
     RECT  20.628 22.541 20.79 22.847 ;
     RECT  54.756 22.819 56.79 22.855 ;
     RECT  138.564 22.199 139.086 22.855 ;
     RECT  44.892 22.783 45.897 22.891 ;
     RECT  49.608 22.505 51.498 22.891 ;
     RECT  53.388 22.109 53.442 22.891 ;
     RECT  57.924 21.929 57.942 22.891 ;
     RECT  72.468 21.929 72.897 22.891 ;
     RECT  73.98 21.929 74.034 22.891 ;
     RECT  46.764 22.235 47.574 22.981 ;
     RECT  48.456 22.199 48.546 22.981 ;
     RECT  54.468 22.855 56.79 22.981 ;
     RECT  57.708 22.891 57.942 22.981 ;
     RECT  58.716 22.513 62.298 22.981 ;
     RECT  66.348 22.621 70.83 22.981 ;
     RECT  72.396 22.891 72.897 22.981 ;
     RECT  138.564 22.855 139.23 23.089 ;
     RECT  140.148 21.929 141.498 23.089 ;
     RECT  144.54 22.235 144.558 23.089 ;
     RECT  145.332 22.795 146.502 23.089 ;
     RECT  14.22 22.505 16.902 23.125 ;
     RECT  43.164 22.505 44.01 23.125 ;
     RECT  44.784 22.891 45.897 23.125 ;
     RECT  46.692 22.981 47.574 23.125 ;
     RECT  128.592 22.235 128.718 23.125 ;
     RECT  136.404 22.459 137.754 23.125 ;
     RECT  144.54 23.089 146.502 23.125 ;
     RECT  149.724 22.783 149.742 23.125 ;
     RECT  10.26 22.469 11.646 23.161 ;
     RECT  14.22 23.125 17.01 23.161 ;
     RECT  17.964 22.541 19.818 23.161 ;
     RECT  43.164 23.125 47.574 23.161 ;
     RECT  48.456 22.981 48.69 23.161 ;
     RECT  52.416 22.505 52.47 23.161 ;
     RECT  53.316 22.891 53.442 23.161 ;
     RECT  54.468 22.981 62.298 23.161 ;
     RECT  63.108 22.199 65.214 23.161 ;
     RECT  65.952 22.981 70.83 23.161 ;
     RECT  71.784 22.981 72.897 23.161 ;
     RECT  129.78 22.469 129.978 23.189 ;
     RECT  144.432 23.125 146.502 23.189 ;
     RECT  147.42 22.781 148.497 23.189 ;
     RECT  2.304 22.637 8.73 23.251 ;
     RECT  10.152 23.161 11.646 23.251 ;
     RECT  12.564 22.541 13.497 23.251 ;
     RECT  14.22 23.161 19.818 23.251 ;
     RECT  21.888 22.505 25.362 23.251 ;
     RECT  26.1 22.739 28.458 23.251 ;
     RECT  32.652 22.613 33.102 23.251 ;
     RECT  33.84 22.505 35.694 23.251 ;
     RECT  36.468 22.505 36.594 23.251 ;
     RECT  43.164 23.161 48.69 23.251 ;
     RECT  49.608 22.891 51.642 23.251 ;
     RECT  52.416 23.161 72.897 23.251 ;
     RECT  73.872 22.891 74.034 23.251 ;
     RECT  74.808 21.929 74.934 23.251 ;
     RECT  21.888 23.251 28.458 23.279 ;
     RECT  43.164 23.251 48.87 23.279 ;
     RECT  49.608 23.251 72.897 23.279 ;
     RECT  75.852 22.739 76.77 23.279 ;
     RECT  79.668 22.541 80.802 23.279 ;
     RECT  81.612 22.541 81.702 23.279 ;
     RECT  84.852 22.811 85.554 23.279 ;
     RECT  87.408 22.739 90.27 23.279 ;
     RECT  91.296 22.541 96.174 23.279 ;
     RECT  96.912 22.541 97.146 23.279 ;
     RECT  98.964 22.541 100.062 23.279 ;
     RECT  100.8 22.739 100.818 23.279 ;
     RECT  102.78 22.621 103.842 23.279 ;
     RECT  106.632 22.541 107.622 23.279 ;
     RECT  108.468 22.577 108.486 23.279 ;
     RECT  110.415 22.649 111.51 23.279 ;
     RECT  112.464 22.541 112.482 23.279 ;
     RECT  115.092 22.235 116.154 23.279 ;
     RECT  123.264 22.469 123.93 23.279 ;
     RECT  134.28 22.739 134.334 23.279 ;
     RECT  138.528 23.089 139.23 23.279 ;
     RECT  2.304 23.251 9.198 23.309 ;
     RECT  12.564 23.251 19.818 23.315 ;
     RECT  27.684 23.279 28.458 23.315 ;
     RECT  15.876 23.315 19.818 23.323 ;
     RECT  20.628 22.847 20.754 23.323 ;
     RECT  41.94 22.505 41.958 23.323 ;
     RECT  117.144 22.621 117.594 23.323 ;
     RECT  125.1 22.621 125.118 23.323 ;
     RECT  126.108 22.469 127.458 23.323 ;
     RECT  15.876 23.323 20.754 23.351 ;
     RECT  21.888 23.279 26.91 23.351 ;
     RECT  58.464 23.279 63.09 23.351 ;
     RECT  66.924 23.279 69.93 23.351 ;
     RECT  70.776 23.279 71.01 23.351 ;
     RECT  142.776 22.613 143.694 23.351 ;
     RECT  10.152 23.251 11.718 23.395 ;
     RECT  21.888 23.351 22.734 23.395 ;
     RECT  32.652 23.251 36.594 23.395 ;
     RECT  37.98 22.685 40.986 23.395 ;
     RECT  41.904 23.323 41.958 23.395 ;
     RECT  44.64 23.279 48.87 23.395 ;
     RECT  49.608 23.279 49.626 23.395 ;
     RECT  71.784 23.279 72.897 23.395 ;
     RECT  29.376 22.739 31.698 23.423 ;
     RECT  64.08 23.279 65.25 23.423 ;
     RECT  7.236 23.309 9.198 23.431 ;
     RECT  10.152 23.395 11.826 23.431 ;
     RECT  12.564 23.315 14.958 23.431 ;
     RECT  21.852 23.395 22.734 23.431 ;
     RECT  31.32 23.423 31.698 23.431 ;
     RECT  32.652 23.395 37.17 23.431 ;
     RECT  37.98 23.395 41.958 23.431 ;
     RECT  43.164 23.279 43.902 23.431 ;
     RECT  71.784 23.395 72.954 23.431 ;
     RECT  73.872 23.251 74.934 23.431 ;
     RECT  77.796 22.541 78.786 23.431 ;
     RECT  82.584 22.775 83.754 23.431 ;
     RECT  86.436 22.505 86.634 23.431 ;
     RECT  95.76 23.279 96.174 23.431 ;
     RECT  97.992 22.541 98.01 23.431 ;
     RECT  99.432 23.279 100.062 23.431 ;
     RECT  101.88 22.541 101.898 23.431 ;
     RECT  103.464 23.279 103.842 23.431 ;
     RECT  104.688 22.541 105.714 23.431 ;
     RECT  107.316 23.279 107.622 23.431 ;
     RECT  109.548 22.649 109.566 23.431 ;
     RECT  110.415 23.279 111.222 23.431 ;
     RECT  113.472 22.235 113.598 23.431 ;
     RECT  117.144 23.323 117.738 23.431 ;
     RECT  119.124 22.493 119.142 23.431 ;
     RECT  120.024 22.469 120.258 23.431 ;
     RECT  128.592 23.125 128.862 23.431 ;
     RECT  135.108 22.783 135.126 23.431 ;
     RECT  136.332 23.125 137.754 23.431 ;
     RECT  138.528 23.279 139.086 23.431 ;
     RECT  140.148 23.089 141.75 23.431 ;
     RECT  144.432 23.189 144.702 23.431 ;
     RECT  66.924 23.351 69.858 23.507 ;
     RECT  82.296 23.431 83.754 23.507 ;
     RECT  88.092 23.279 89.097 23.507 ;
     RECT  115.815 23.279 116.097 23.507 ;
     RECT  142.776 23.351 143.097 23.507 ;
     RECT  147.492 23.189 148.497 23.507 ;
     RECT  7.236 23.431 14.958 23.549 ;
     RECT  15.876 23.351 16.902 23.549 ;
     RECT  21.672 23.431 22.734 23.549 ;
     RECT  23.616 23.351 26.91 23.549 ;
     RECT  29.376 23.423 30.546 23.549 ;
     RECT  31.32 23.431 43.902 23.549 ;
     RECT  44.64 23.395 49.626 23.549 ;
     RECT  50.508 23.279 53.694 23.549 ;
     RECT  54.576 23.279 57.69 23.549 ;
     RECT  65.016 23.423 65.25 23.549 ;
     RECT  66.924 23.507 67.374 23.549 ;
     RECT  68.112 23.507 69.858 23.549 ;
     RECT  71.784 23.431 75.582 23.549 ;
     RECT  76.536 23.279 76.77 23.549 ;
     RECT  77.508 23.431 79.398 23.549 ;
     RECT  80.352 23.279 80.406 23.549 ;
     RECT  81.144 23.431 81.342 23.549 ;
     RECT  82.296 23.507 83.505 23.549 ;
     RECT  84.852 23.279 85.194 23.549 ;
     RECT  86.148 23.431 87.138 23.549 ;
     RECT  88.092 23.507 88.974 23.549 ;
     RECT  91.008 23.431 91.026 23.549 ;
     RECT  91.908 23.279 92.898 23.549 ;
     RECT  93.852 23.279 94.842 23.549 ;
     RECT  95.76 23.431 96.75 23.549 ;
     RECT  97.704 23.431 98.694 23.549 ;
     RECT  99.432 23.431 100.566 23.549 ;
     RECT  101.7 23.431 102.51 23.549 ;
     RECT  103.464 23.431 106.362 23.549 ;
     RECT  107.316 23.431 108.306 23.549 ;
     RECT  109.26 23.431 111.222 23.549 ;
     RECT  111.96 23.431 112.194 23.549 ;
     RECT  115.02 23.431 115.074 23.549 ;
     RECT  116.964 23.431 117.738 23.549 ;
     RECT  118.872 23.431 120.258 23.549 ;
     RECT  121.215 22.739 122.31 23.549 ;
     RECT  123.264 23.279 123.678 23.549 ;
     RECT  124.488 23.323 125.118 23.549 ;
     RECT  126.108 23.323 127.566 23.549 ;
     RECT  128.484 23.431 128.862 23.549 ;
     RECT  129.96 23.189 129.978 23.549 ;
     RECT  132.015 22.199 133.11 23.549 ;
     RECT  135.108 23.431 135.234 23.549 ;
     RECT  136.188 23.431 139.086 23.549 ;
     RECT  140.04 23.431 141.75 23.549 ;
     RECT  142.776 23.507 142.974 23.549 ;
     RECT  143.928 23.431 144.702 23.549 ;
     RECT  145.44 23.189 146.502 23.549 ;
     RECT  147.492 23.507 148.305 23.549 ;
     RECT  130.932 22.739 130.95 23.557 ;
     RECT  11.088 23.549 14.958 23.585 ;
     RECT  34.2 23.549 36.126 23.585 ;
     RECT  41.904 23.549 43.83 23.585 ;
     RECT  44.82 23.549 45.774 23.585 ;
     RECT  48.6 23.549 48.654 23.585 ;
     RECT  50.508 23.549 51.534 23.585 ;
     RECT  54.576 23.549 57.618 23.585 ;
     RECT  64.08 23.423 64.206 23.585 ;
     RECT  65.016 23.549 65.106 23.585 ;
     RECT  71.784 23.549 72.705 23.585 ;
     RECT  73.584 23.549 75.366 23.585 ;
     RECT  91.944 23.549 92.718 23.585 ;
     RECT  7.236 23.549 9.198 23.621 ;
     RECT  21.672 23.549 21.978 23.621 ;
     RECT  39.204 23.549 41.022 23.621 ;
     RECT  41.904 23.585 42.21 23.621 ;
     RECT  47.16 23.549 47.682 23.621 ;
     RECT  52.344 23.549 53.478 23.621 ;
     RECT  54.576 23.585 57.33 23.621 ;
     RECT  58.5 23.351 63.09 23.621 ;
     RECT  2.304 23.309 6.498 23.657 ;
     RECT  49.536 23.549 49.626 23.657 ;
     RECT  61.164 23.621 62.154 23.657 ;
     RECT  76.572 23.549 76.77 23.665 ;
     RECT  77.508 23.549 79.218 23.665 ;
     RECT  84.852 23.549 84.978 23.665 ;
     RECT  101.7 23.549 102.33 23.665 ;
     RECT  113.148 23.431 113.598 23.665 ;
     RECT  121.215 23.549 121.554 23.665 ;
     RECT  123.264 23.549 123.498 23.665 ;
     RECT  128.52 23.549 128.862 23.665 ;
     RECT  130.464 23.557 130.95 23.665 ;
     RECT  134.316 23.279 134.334 23.665 ;
     RECT  142.02 23.557 142.038 23.665 ;
     RECT  142.776 23.549 142.905 23.665 ;
     RECT  145.872 23.549 146.502 23.665 ;
     RECT  2.304 23.657 6.318 23.693 ;
     RECT  17.928 23.351 20.754 23.693 ;
     RECT  2.304 23.693 4.518 23.729 ;
     RECT  5.328 23.693 6.318 23.729 ;
     RECT  12.096 23.585 13.95 23.729 ;
     RECT  17.928 23.693 19.818 23.729 ;
     RECT  29.415 23.549 30.366 23.729 ;
     RECT  36 23.585 36.126 23.729 ;
     RECT  37.26 23.549 38.07 23.729 ;
     RECT  54.576 23.621 56.505 23.729 ;
     RECT  68.868 23.549 69.678 23.729 ;
     RECT  73.944 23.585 75.366 23.741 ;
     RECT  84.24 23.665 84.978 23.741 ;
     RECT  86.184 23.549 86.922 23.741 ;
     RECT  90.792 23.665 90.81 23.741 ;
     RECT  95.796 23.549 96.534 23.741 ;
     RECT  105.015 23.549 106.146 23.741 ;
     RECT  109.296 23.549 111.222 23.741 ;
     RECT  111.96 23.549 111.978 23.741 ;
     RECT  130.464 23.665 131.202 23.741 ;
     RECT  133.128 23.665 133.146 23.741 ;
     RECT  7.236 23.621 8.262 23.777 ;
     RECT  12.96 23.729 13.95 23.777 ;
     RECT  17.928 23.729 18.81 23.777 ;
     RECT  23.616 23.549 24.606 23.777 ;
     RECT  29.415 23.729 29.574 23.777 ;
     RECT  34.2 23.585 35.226 23.777 ;
     RECT  39.96 23.621 41.022 23.777 ;
     RECT  45.615 23.585 45.774 23.777 ;
     RECT  51.015 23.585 51.534 23.777 ;
     RECT  56.376 23.729 56.505 23.777 ;
     RECT  61.164 23.657 61.974 23.777 ;
     RECT  66.924 23.549 67.305 23.777 ;
     RECT  72.576 23.585 72.705 23.777 ;
     RECT  76.572 23.665 79.218 23.777 ;
     RECT  82.332 23.549 83.505 23.777 ;
     RECT  88.092 23.549 88.905 23.777 ;
     RECT  93.888 23.549 94.662 23.777 ;
     RECT  105.015 23.741 105.462 23.777 ;
     RECT  110.415 23.741 111.222 23.777 ;
     RECT  115.815 23.507 116.01 23.777 ;
     RECT  126.54 23.549 127.386 23.777 ;
     RECT  132.015 23.549 132.39 23.777 ;
     RECT  136.98 23.549 138.87 23.777 ;
     RECT  142.02 23.665 142.905 23.777 ;
     RECT  147.78 23.549 148.305 23.777 ;
     RECT  0.54 22.397 0.558 23.837 ;
     RECT  142.02 23.777 142.758 23.885 ;
     RECT  99.432 23.549 100.386 23.927 ;
     RECT  126.54 23.777 126.63 23.927 ;
     RECT  8.244 23.777 8.262 23.933 ;
     RECT  10.152 23.549 10.17 23.933 ;
     RECT  19.8 23.729 19.818 23.933 ;
     RECT  31.32 23.549 31.338 23.933 ;
     RECT  33.228 23.549 33.246 23.933 ;
     RECT  35.208 23.777 35.226 23.933 ;
     RECT  41.004 23.777 41.022 23.933 ;
     RECT  43.308 23.585 43.83 23.933 ;
     RECT  56.376 23.777 56.394 23.933 ;
     RECT  66.096 23.279 66.114 23.933 ;
     RECT  71.784 23.585 71.802 23.933 ;
     RECT  73.944 23.741 74.646 23.933 ;
     RECT  81.144 23.549 81.162 23.933 ;
     RECT  94.644 23.777 94.662 23.933 ;
     RECT  99.648 23.927 100.386 23.933 ;
     RECT  101.592 23.665 102.33 23.933 ;
     RECT  115.992 23.777 116.01 23.933 ;
     RECT  117 23.549 117.558 23.933 ;
     RECT  120.816 23.665 121.554 23.933 ;
     RECT  125.424 23.665 125.442 23.933 ;
     RECT  127.368 23.777 127.386 23.933 ;
     RECT  136.98 23.777 136.998 23.933 ;
     RECT  140.976 23.549 140.994 23.933 ;
     RECT  145.872 23.665 146.61 23.933 ;
     RECT  13.932 23.777 13.95 23.981 ;
     RECT  25.488 23.549 25.506 23.981 ;
     RECT  60.156 23.621 60.174 23.981 ;
     RECT  69.66 23.729 69.678 23.981 ;
     RECT  149.724 23.125 150.462 24.413 ;
     RECT  12.096 23.729 12.114 24.509 ;
     RECT  15.876 23.549 15.894 24.509 ;
     RECT  17.928 23.777 17.946 24.509 ;
     RECT  21.96 23.621 21.978 24.509 ;
     RECT  23.616 23.777 23.634 24.509 ;
     RECT  27.684 23.315 28.386 24.509 ;
     RECT  29.556 23.777 29.574 24.509 ;
     RECT  37.26 23.729 37.278 24.509 ;
     RECT  39.204 23.621 39.222 24.509 ;
     RECT  44.82 23.585 44.838 24.509 ;
     RECT  48.636 23.585 48.654 24.509 ;
     RECT  58.5 23.621 59.238 24.509 ;
     RECT  61.956 23.777 61.974 24.509 ;
     RECT  2.304 23.729 3.402 24.557 ;
     RECT  0.108 24.523 0.126 24.653 ;
     RECT  2.808 24.557 3.402 24.653 ;
     RECT  3.024 24.653 3.402 24.797 ;
     RECT  6.3 23.729 6.318 25.085 ;
     RECT  52.344 23.621 52.362 25.085 ;
     RECT  64.188 23.585 64.206 25.085 ;
     RECT  76.572 23.777 77.31 25.133 ;
     RECT  82.332 23.777 83.034 25.133 ;
     RECT  88.092 23.777 88.794 25.133 ;
     RECT  97.74 23.549 98.478 25.133 ;
     RECT  103.5 23.549 104.202 25.133 ;
     RECT  107.352 23.549 108.09 25.133 ;
     RECT  118.908 23.549 119.646 25.133 ;
     RECT  138.168 23.777 138.87 25.133 ;
     RECT  144.684 23.549 144.702 25.133 ;
     RECT  54.576 23.729 55.314 25.805 ;
     RECT  68.112 23.549 68.13 25.805 ;
     RECT  78.48 23.777 79.218 25.805 ;
     RECT  92.7 23.585 92.718 25.805 ;
     RECT  113.148 23.665 113.886 25.805 ;
     RECT  122.76 23.665 123.498 25.805 ;
     RECT  128.52 23.665 129.006 25.805 ;
     RECT  134.316 23.665 135.054 25.805 ;
     RECT  12.96 23.777 12.978 25.861 ;
     RECT  22.716 23.549 22.734 25.861 ;
     RECT  28.368 24.509 28.386 25.861 ;
     RECT  55.296 25.805 55.314 25.861 ;
     RECT  72.576 23.777 72.594 25.861 ;
    LAYER M4 ;
     RECT  0.084 1.104 0.569 1.128 ;
     RECT  0.06 1.128 0.569 1.344 ;
     RECT  0.084 1.344 0.569 1.368 ;
     RECT  0.06 1.368 0.569 1.584 ;
     RECT  0.084 1.584 0.569 1.608 ;
     RECT  0.06 1.608 0.569 1.824 ;
     RECT  0.084 1.824 0.569 1.848 ;
     RECT  0.06 1.848 0.569 2.064 ;
     RECT  0.084 2.064 0.569 2.088 ;
     RECT  0.06 2.088 0.569 2.352 ;
     RECT  0.084 2.352 0.569 2.376 ;
     RECT  0.06 2.376 0.569 2.592 ;
     RECT  0.084 2.592 0.569 2.616 ;
     RECT  0.06 2.616 0.569 2.832 ;
     RECT  0.084 2.832 0.569 2.856 ;
     RECT  0.06 2.856 0.569 3.072 ;
     RECT  0.084 3.072 0.569 3.096 ;
     RECT  0.06 3.096 0.569 3.312 ;
     RECT  0.084 3.312 0.569 3.336 ;
     RECT  0.06 3.336 0.569 3.552 ;
     RECT  0.084 3.552 0.569 3.576 ;
     RECT  0.06 3.576 0.569 3.792 ;
     RECT  0.084 3.792 0.569 3.816 ;
     RECT  0.06 3.816 0.569 4.032 ;
     RECT  0.084 4.032 0.569 4.056 ;
     RECT  0.06 4.056 0.569 4.272 ;
     RECT  0.084 4.272 0.569 4.296 ;
     RECT  0.06 4.296 0.569 4.512 ;
     RECT  0.084 4.512 0.569 4.536 ;
     RECT  0.06 4.536 0.569 4.752 ;
     RECT  0.084 4.752 0.569 4.776 ;
     RECT  0.06 4.776 0.569 4.992 ;
     RECT  0.084 4.992 0.569 5.016 ;
     RECT  0.06 5.016 0.569 5.28 ;
     RECT  0.084 5.28 0.569 5.304 ;
     RECT  0.06 5.304 0.569 5.52 ;
     RECT  0.084 5.52 0.569 5.544 ;
     RECT  0.06 5.544 0.569 5.76 ;
     RECT  0.084 5.76 0.569 5.784 ;
     RECT  0.06 5.784 0.569 6 ;
     RECT  0.084 6 0.569 6.024 ;
     RECT  0.06 6.024 0.569 6.24 ;
     RECT  0.084 6.24 0.569 6.264 ;
     RECT  0.06 6.264 0.569 6.48 ;
     RECT  0.084 6.48 0.569 6.504 ;
     RECT  0.06 6.504 0.569 6.72 ;
     RECT  0.084 6.72 0.569 6.744 ;
     RECT  0.06 6.744 0.569 6.96 ;
     RECT  0.084 6.96 0.569 6.984 ;
     RECT  0.06 6.984 0.569 7.2 ;
     RECT  0.084 7.2 0.569 7.224 ;
     RECT  0.06 7.224 0.569 7.44 ;
     RECT  0.084 7.44 0.569 7.464 ;
     RECT  0.06 7.464 0.569 7.68 ;
     RECT  0.084 7.68 0.569 7.704 ;
     RECT  0.06 7.704 0.569 7.968 ;
     RECT  0.084 7.968 0.569 7.992 ;
     RECT  0.06 7.992 0.569 8.208 ;
     RECT  0.084 8.208 0.569 8.232 ;
     RECT  0.06 8.232 0.569 8.448 ;
     RECT  0.084 8.448 0.569 8.472 ;
     RECT  0.06 8.472 0.569 8.688 ;
     RECT  0.084 8.688 0.569 8.712 ;
     RECT  0.06 8.712 0.569 8.928 ;
     RECT  0.084 8.928 0.569 8.952 ;
     RECT  0.06 8.952 0.569 9.168 ;
     RECT  0.084 9.168 0.569 9.192 ;
     RECT  0.06 9.192 0.569 9.408 ;
     RECT  0.084 9.408 0.569 9.432 ;
     RECT  0.06 9.432 0.569 9.648 ;
     RECT  0.084 9.648 0.569 9.672 ;
     RECT  0.06 9.672 0.569 9.888 ;
     RECT  0.084 9.888 0.569 9.912 ;
     RECT  0.06 9.912 0.569 10.128 ;
     RECT  0.084 10.128 0.569 10.152 ;
     RECT  0.06 10.152 0.569 10.368 ;
     RECT  0.084 10.368 0.569 10.392 ;
     RECT  0.06 10.392 0.569 10.608 ;
     RECT  0.084 10.608 0.569 10.632 ;
     RECT  0.06 10.632 0.569 10.896 ;
     RECT  0.084 10.896 0.569 10.92 ;
     RECT  0.06 10.92 0.569 11.136 ;
     RECT  0.084 11.136 0.569 11.16 ;
     RECT  0.06 11.16 0.569 11.376 ;
     RECT  0.084 11.376 0.569 11.4 ;
     RECT  0.06 11.4 0.569 11.616 ;
     RECT  0.084 11.616 0.569 11.64 ;
     RECT  0.06 11.64 0.569 11.856 ;
     RECT  0.084 11.856 0.569 11.88 ;
     RECT  0.06 11.88 0.569 12.096 ;
     RECT  0.084 12.096 0.569 12.12 ;
     RECT  0.06 12.12 0.569 12.336 ;
     RECT  0.084 12.336 0.569 12.36 ;
     RECT  0.06 12.36 0.569 12.576 ;
     RECT  0.084 12.576 0.569 12.6 ;
     RECT  0.06 12.6 0.569 12.816 ;
     RECT  0.084 12.816 0.569 12.84 ;
     RECT  0.06 12.84 0.569 13.056 ;
     RECT  0.084 13.056 0.569 13.08 ;
     RECT  0.06 13.08 0.569 13.296 ;
     RECT  0.084 13.296 0.569 13.32 ;
     RECT  0.06 13.32 0.569 13.536 ;
     RECT  0.084 13.536 0.569 13.56 ;
     RECT  0.06 13.56 0.569 13.824 ;
     RECT  0.084 13.824 0.569 13.848 ;
     RECT  0.06 13.848 0.569 14.064 ;
     RECT  0.084 14.064 0.569 14.088 ;
     RECT  0.06 14.088 0.569 14.304 ;
     RECT  0.084 14.304 0.569 14.328 ;
     RECT  0.06 14.328 0.569 14.544 ;
     RECT  0.084 14.544 0.569 14.568 ;
     RECT  0.06 14.568 0.569 14.784 ;
     RECT  0.084 14.784 0.569 14.808 ;
     RECT  0.06 14.808 0.569 15.024 ;
     RECT  0.084 15.024 0.569 15.048 ;
     RECT  0.06 15.048 0.569 15.264 ;
     RECT  0.084 15.264 0.569 15.288 ;
     RECT  0.06 15.288 0.569 15.504 ;
     RECT  0.084 15.504 0.569 15.528 ;
     RECT  0.06 15.528 0.569 15.744 ;
     RECT  0.084 15.744 0.569 15.768 ;
     RECT  0.06 15.768 0.569 15.984 ;
     RECT  0.084 15.984 0.569 16.008 ;
     RECT  0.06 16.008 0.569 16.224 ;
     RECT  0.084 16.224 0.569 16.248 ;
     RECT  0.06 16.248 0.569 16.464 ;
     RECT  0.084 16.464 0.569 16.488 ;
     RECT  0.06 16.488 0.569 16.752 ;
     RECT  0.084 16.752 0.569 16.776 ;
     RECT  0.06 16.776 0.569 16.992 ;
     RECT  0.084 16.992 0.569 17.016 ;
     RECT  0.06 17.016 0.569 17.232 ;
     RECT  0.084 17.232 0.569 17.256 ;
     RECT  0.06 17.256 0.569 17.472 ;
     RECT  0.084 17.472 0.569 17.496 ;
     RECT  0.06 17.496 0.569 17.712 ;
     RECT  0.084 17.712 0.569 17.736 ;
     RECT  0.06 17.736 0.569 17.952 ;
     RECT  0.084 17.952 0.569 17.976 ;
     RECT  0.06 17.976 0.569 18.192 ;
     RECT  0.084 18.192 0.569 18.216 ;
     RECT  0.06 18.216 0.569 18.432 ;
     RECT  0.084 18.432 0.569 18.456 ;
     RECT  0.06 18.456 0.569 18.672 ;
     RECT  0.084 18.672 0.569 18.696 ;
     RECT  0.06 18.696 0.569 18.912 ;
     RECT  0.084 18.912 0.569 18.936 ;
     RECT  0.06 18.936 0.569 19.152 ;
     RECT  0.084 19.152 0.569 19.176 ;
     RECT  0.06 19.176 0.569 19.44 ;
     RECT  0.084 19.44 0.569 19.464 ;
     RECT  0.06 19.464 0.569 19.68 ;
     RECT  0.084 19.68 0.569 19.704 ;
     RECT  0.06 19.704 0.569 19.92 ;
     RECT  0.084 19.92 0.569 19.944 ;
     RECT  0.06 19.944 0.569 20.16 ;
     RECT  0.084 20.16 0.569 20.184 ;
     RECT  0.06 20.184 0.569 20.4 ;
     RECT  0.084 20.4 0.569 20.424 ;
     RECT  0.06 20.424 0.569 20.64 ;
     RECT  0.084 20.64 0.569 20.664 ;
     RECT  0.06 20.664 0.569 20.88 ;
     RECT  0.084 20.88 0.569 20.904 ;
     RECT  0.06 20.904 0.569 21.12 ;
     RECT  0.084 21.12 0.569 21.144 ;
     RECT  0.06 21.144 0.569 21.36 ;
     RECT  0.084 21.36 0.569 21.384 ;
     RECT  0.06 21.384 0.569 21.6 ;
     RECT  0.084 21.6 0.569 21.624 ;
     RECT  0.06 21.624 0.569 21.84 ;
     RECT  0.084 21.84 0.569 21.864 ;
     RECT  0.06 21.864 0.569 22.08 ;
     RECT  0.084 22.08 0.569 22.104 ;
     RECT  0.06 22.104 0.569 22.368 ;
     RECT  0.084 22.368 0.569 22.392 ;
     RECT  0.06 22.392 0.569 22.608 ;
     RECT  0.084 22.608 0.569 22.632 ;
     RECT  0.06 22.632 0.569 22.848 ;
     RECT  0.084 22.848 0.569 22.872 ;
     RECT  0.06 22.872 0.569 23.088 ;
     RECT  0.084 23.088 0.569 23.112 ;
     RECT  0.06 23.112 0.569 23.328 ;
     RECT  0.084 23.328 0.569 23.352 ;
     RECT  0.06 23.352 0.569 23.568 ;
     RECT  0.084 23.568 0.569 23.592 ;
     RECT  0.06 23.592 0.569 23.808 ;
     RECT  0.084 23.808 0.569 23.832 ;
     RECT  0.06 23.832 0.569 24.048 ;
     RECT  0.084 24.048 0.569 24.072 ;
     RECT  0.06 24.072 0.569 24.288 ;
     RECT  0.084 24.288 0.569 24.312 ;
     RECT  0.06 24.312 0.569 24.528 ;
     RECT  0.084 24.528 0.569 24.552 ;
     RECT  0.06 24.552 0.569 24.768 ;
     RECT  0.084 24.768 0.569 24.792 ;
     RECT  1.436 25.824 1.523 25.848 ;
     RECT  0.569 1.104 1.757 11.64 ;
     RECT  1.757 1.344 2.333 11.64 ;
     RECT  2.333 1.584 2.408 11.64 ;
     RECT  0.569 12.816 2.408 24.792 ;
     RECT  2.408 1.584 2.585 24.792 ;
     RECT  2.585 1.584 2.704 23.592 ;
     RECT  2.704 7.44 2.765 7.464 ;
     RECT  2.704 13.056 2.765 23.592 ;
     RECT  2.704 10.128 2.837 10.92 ;
     RECT  2.765 13.056 2.837 16.344 ;
     RECT  2.765 17.952 2.837 23.592 ;
     RECT  2.585 24.624 2.837 24.792 ;
     RECT  2.837 18.192 2.873 23.592 ;
     RECT  2.704 1.584 2.981 4.152 ;
     RECT  2.837 10.128 3.017 10.152 ;
     RECT  2.873 22.272 3.017 23.592 ;
     RECT  2.837 24.768 3.053 24.792 ;
     RECT  2.837 13.056 3.305 13.848 ;
     RECT  2.873 18.192 3.305 21.192 ;
     RECT  2.981 1.584 3.449 1.752 ;
     RECT  2.981 2.832 3.733 4.152 ;
     RECT  3.017 22.704 3.773 23.592 ;
     RECT  3.449 1.728 3.881 1.752 ;
     RECT  3.733 2.832 3.949 4.2 ;
     RECT  2.837 15.648 4.133 15.768 ;
     RECT  3.773 22.704 4.201 23.4 ;
     RECT  3.913 16.944 4.205 16.968 ;
     RECT  2.704 5.712 4.313 5.832 ;
     RECT  4.313 5.808 4.385 5.832 ;
     RECT  3.305 13.056 4.556 13.08 ;
     RECT  4.556 12.96 4.597 13.08 ;
     RECT  4.525 14.256 4.597 14.28 ;
     RECT  4.201 22.224 4.673 23.4 ;
     RECT  4.129 11.808 4.705 11.832 ;
     RECT  4.597 12.96 4.705 14.28 ;
     RECT  4.705 11.808 4.777 14.28 ;
     RECT  4.133 15.648 4.777 15.72 ;
     RECT  3.305 18.528 4.849 21.192 ;
     RECT  4.673 22.224 4.853 23.016 ;
     RECT  3.913 9.936 5.101 9.96 ;
     RECT  3.949 2.496 5.453 4.2 ;
     RECT  5.101 9.936 5.497 10.248 ;
     RECT  4.853 22.752 5.501 23.016 ;
     RECT  5.453 1.728 5.537 4.2 ;
     RECT  4.777 11.808 5.557 15.72 ;
     RECT  4.849 18.24 5.569 21.192 ;
     RECT  4.741 6.24 5.645 6.264 ;
     RECT  5.569 18.24 5.677 21.24 ;
     RECT  4.885 8.496 5.825 8.52 ;
     RECT  5.677 18.24 5.825 21.72 ;
     RECT  5.537 2.496 5.989 4.2 ;
     RECT  5.825 19.824 6.001 21.72 ;
     RECT  5.948 6.48 6.035 6.504 ;
     RECT  5.497 9.888 6.113 10.248 ;
     RECT  5.825 18.24 6.185 18.84 ;
     RECT  6.245 25.056 6.329 25.08 ;
     RECT  5.557 11.808 6.433 16.008 ;
     RECT  5.821 17.088 6.433 17.112 ;
     RECT  6.001 19.824 6.545 22.104 ;
     RECT  6.433 11.808 6.908 17.112 ;
     RECT  6.185 18.24 6.908 18.6 ;
     RECT  6.113 10.224 7.052 10.248 ;
     RECT  7.093 0.576 7.409 0.6 ;
     RECT  6.908 11.808 7.669 18.6 ;
     RECT  6.545 20.304 7.669 22.104 ;
     RECT  5.989 2.496 7.808 4.536 ;
     RECT  7.073 9.072 7.808 9.096 ;
     RECT  7.052 10.224 7.808 10.584 ;
     RECT  7.669 11.808 7.808 22.104 ;
     RECT  7.117 23.28 7.808 23.304 ;
     RECT  7.808 2.148 7.912 23.772 ;
     RECT  7.912 2.418 8.104 23.772 ;
     RECT  8.189 23.904 8.273 23.928 ;
     RECT  8.104 19.536 8.381 19.56 ;
     RECT  8.104 20.544 8.417 22.008 ;
     RECT  8.417 20.544 8.461 20.664 ;
     RECT  8.104 2.496 8.597 4.2 ;
     RECT  8.104 10.896 8.633 16.536 ;
     RECT  8.725 0.096 8.921 0.12 ;
     RECT  8.417 21.888 9.241 22.008 ;
     RECT  9.241 21.888 9.281 22.2 ;
     RECT  10.097 23.904 10.181 23.928 ;
     RECT  10.357 0.096 10.505 0.12 ;
     RECT  9.281 22.176 11.18 22.2 ;
     RECT  11.18 22.176 11.221 22.248 ;
     RECT  11.221 21.936 11.267 22.248 ;
     RECT  11.941 0.096 12.035 0.12 ;
     RECT  12.037 24.48 12.125 24.504 ;
     RECT  8.597 2.496 12.445 3.048 ;
     RECT  8.597 4.128 12.445 4.2 ;
     RECT  12.445 2.496 13.208 4.2 ;
     RECT  8.633 11.808 13.208 16.536 ;
     RECT  8.461 20.64 13.208 20.664 ;
     RECT  11.267 21.936 13.208 21.96 ;
     RECT  13.208 2.148 13.312 23.772 ;
     RECT  13.312 2.418 13.504 23.772 ;
     RECT  13.597 0.096 13.681 0.12 ;
     RECT  13.916 23.952 14.003 23.976 ;
     RECT  15.217 0.096 15.301 0.12 ;
     RECT  13.504 2.496 15.549 2.52 ;
     RECT  13.504 3.936 15.549 4.2 ;
     RECT  15.865 24.48 15.949 24.504 ;
     RECT  15.037 22.224 16.013 22.248 ;
     RECT  16.837 0.096 16.931 0.12 ;
     RECT  15.549 2.496 17.453 4.2 ;
     RECT  17.845 24.48 17.957 24.504 ;
     RECT  18.457 0.096 18.563 0.12 ;
     RECT  17.453 2.496 18.608 2.52 ;
     RECT  17.453 3.888 18.608 4.2 ;
     RECT  13.504 11.808 18.608 16.536 ;
     RECT  13.504 20.64 18.608 20.664 ;
     RECT  16.981 22.224 18.608 22.248 ;
     RECT  18.608 2.148 18.712 23.772 ;
     RECT  18.712 2.418 18.904 23.502 ;
     RECT  18.904 21.84 19.433 22.248 ;
     RECT  19.745 23.904 19.829 23.928 ;
     RECT  18.904 2.496 19.916 2.52 ;
     RECT  18.904 3.84 19.916 4.2 ;
     RECT  20.149 0.096 20.233 0.12 ;
     RECT  19.433 21.84 20.833 21.864 ;
     RECT  20.833 21.84 20.873 22.2 ;
     RECT  21.769 0.096 21.853 0.12 ;
     RECT  21.685 24.48 21.989 24.504 ;
     RECT  19.916 2.496 22.889 4.2 ;
     RECT  23.605 24.48 23.689 24.504 ;
     RECT  20.873 22.176 23.713 22.2 ;
     RECT  23.413 0.096 23.717 0.12 ;
     RECT  22.889 2.496 24.008 2.52 ;
     RECT  22.889 3.84 24.008 4.2 ;
     RECT  19.933 5.184 24.008 5.208 ;
     RECT  18.904 11.808 24.008 16.536 ;
     RECT  18.904 20.64 24.008 20.664 ;
     RECT  23.713 21.936 24.008 22.2 ;
     RECT  24.008 2.148 24.112 23.772 ;
     RECT  24.112 2.148 24.304 23.502 ;
     RECT  24.304 2.148 25.045 2.52 ;
     RECT  25.045 1.728 25.129 2.52 ;
     RECT  25.477 23.952 25.571 23.976 ;
     RECT  24.304 21.744 26.057 21.96 ;
     RECT  26.629 0.096 26.723 0.12 ;
     RECT  24.304 20.64 27.601 20.664 ;
     RECT  26.057 21.936 27.601 21.96 ;
     RECT  27.601 20.64 27.641 21.96 ;
     RECT  27.641 20.64 27.685 21.816 ;
     RECT  27.445 24.48 27.713 24.504 ;
     RECT  25.129 2.496 28.277 2.52 ;
     RECT  28.277 1.728 28.361 2.52 ;
     RECT  27.685 21.792 29.041 21.816 ;
     RECT  28.361 2.496 29.408 2.52 ;
     RECT  24.304 3.84 29.408 4.2 ;
     RECT  24.304 5.184 29.408 5.208 ;
     RECT  24.304 11.808 29.408 16.536 ;
     RECT  27.685 20.64 29.408 20.664 ;
     RECT  29.041 21.792 29.408 22.248 ;
     RECT  29.365 24.48 29.408 24.504 ;
     RECT  29.408 2.148 29.512 24.504 ;
     RECT  29.512 24.48 29.585 24.504 ;
     RECT  29.512 2.418 29.704 23.502 ;
     RECT  29.941 0.096 30.089 0.12 ;
     RECT  29.704 3.84 30.557 4.2 ;
     RECT  29.704 20.64 30.668 20.664 ;
     RECT  29.704 22.176 30.668 22.2 ;
     RECT  30.668 20.64 30.755 22.2 ;
     RECT  30.557 4.176 31.309 4.2 ;
     RECT  29.704 5.184 31.309 5.208 ;
     RECT  31.265 23.904 31.349 23.928 ;
     RECT  30.755 22.176 31.457 22.2 ;
     RECT  31.525 0.096 31.619 0.12 ;
     RECT  29.704 2.496 32.713 2.52 ;
     RECT  31.309 4.176 32.713 5.208 ;
     RECT  32.713 2.496 33.041 5.208 ;
     RECT  33.145 0.096 33.251 0.12 ;
     RECT  33.173 23.904 33.257 23.928 ;
     RECT  32.389 22.224 33.865 22.248 ;
     RECT  33.865 22.224 34.309 22.632 ;
     RECT  33.041 2.496 34.789 4.2 ;
     RECT  34.789 1.728 34.808 4.2 ;
     RECT  33.041 5.184 34.808 5.208 ;
     RECT  29.704 11.808 34.808 16.536 ;
     RECT  30.755 20.64 34.808 20.664 ;
     RECT  34.309 21.936 34.808 22.632 ;
     RECT  34.808 1.728 35.057 23.772 ;
     RECT  35.057 2.418 35.104 23.772 ;
     RECT  35.153 23.904 35.237 23.928 ;
     RECT  35.104 21.936 36.205 21.96 ;
     RECT  36.205 21.936 36.245 22.2 ;
     RECT  36.385 0.096 36.469 0.12 ;
     RECT  36.245 22.176 37.217 22.2 ;
     RECT  37.093 24.48 37.289 24.504 ;
     RECT  38.053 0.096 38.189 0.12 ;
     RECT  37.753 22.656 38.513 22.68 ;
     RECT  38.797 22.752 38.981 22.776 ;
     RECT  39.013 24.48 39.233 24.504 ;
     RECT  39.653 0.096 39.737 0.12 ;
     RECT  35.104 2.496 40.208 4.2 ;
     RECT  35.104 5.184 40.208 5.208 ;
     RECT  35.104 11.808 40.208 16.536 ;
     RECT  35.104 20.64 40.208 20.664 ;
     RECT  40.208 2.148 40.312 23.772 ;
     RECT  40.312 2.352 40.504 23.772 ;
     RECT  40.504 22.176 40.817 22.728 ;
     RECT  40.933 23.904 41.033 23.928 ;
     RECT  40.504 2.352 41.317 4.2 ;
     RECT  41.317 2.304 41.401 4.2 ;
     RECT  41.401 2.352 41.429 4.2 ;
     RECT  40.817 22.176 42.577 22.2 ;
     RECT  42.577 21.936 42.617 22.2 ;
     RECT  41.429 2.448 42.721 4.2 ;
     RECT  42.721 2.352 42.793 4.2 ;
     RECT  40.504 5.184 42.793 5.208 ;
     RECT  42.793 2.352 42.937 5.208 ;
     RECT  42.937 2.304 43.021 5.208 ;
     RECT  42.853 23.904 43.337 23.928 ;
     RECT  42.617 21.936 43.729 21.96 ;
     RECT  43.021 2.496 43.877 5.208 ;
     RECT  43.729 21.936 43.877 22.824 ;
     RECT  43.877 21.936 43.9 22.728 ;
     RECT  43.877 2.496 44.549 4.2 ;
     RECT  44.549 2.304 44.633 4.2 ;
     RECT  44.765 24.48 44.849 24.504 ;
     RECT  44.633 2.496 45.421 4.2 ;
     RECT  43.877 5.184 45.421 5.208 ;
     RECT  45.421 2.496 45.608 5.208 ;
     RECT  40.504 11.808 45.608 16.536 ;
     RECT  40.504 20.64 45.608 20.664 ;
     RECT  43.9 21.936 45.608 21.96 ;
     RECT  45.608 2.148 45.712 23.772 ;
     RECT  45.712 2.304 45.904 23.502 ;
     RECT  45.904 2.304 46.261 5.208 ;
     RECT  45.904 21.936 46.325 22.2 ;
     RECT  46.261 2.352 46.433 5.208 ;
     RECT  45.904 23.376 46.739 23.4 ;
     RECT  47.797 0.576 47.891 0.6 ;
     RECT  46.325 22.176 48.557 22.2 ;
     RECT  48.581 24.48 48.665 24.504 ;
     RECT  46.433 5.184 48.985 5.208 ;
     RECT  48.985 5.184 49.021 5.784 ;
     RECT  49.021 5.184 49.057 5.88 ;
     RECT  46.433 2.352 49.273 4.2 ;
     RECT  49.057 5.184 49.273 5.976 ;
     RECT  49.273 2.352 49.445 5.976 ;
     RECT  49.445 1.728 49.453 5.976 ;
     RECT  49.453 1.728 49.529 6.456 ;
     RECT  49.529 2.496 49.669 6.456 ;
     RECT  49.669 2.496 49.777 6.792 ;
     RECT  49.777 2.496 49.961 7.272 ;
     RECT  49.961 2.496 51.008 6.792 ;
     RECT  50.929 7.92 51.008 7.944 ;
     RECT  45.904 11.808 51.008 16.536 ;
     RECT  45.904 20.64 51.008 20.664 ;
     RECT  49.345 21.648 51.008 21.672 ;
     RECT  50.533 23.376 51.008 23.4 ;
     RECT  51.008 2.148 51.112 23.772 ;
     RECT  51.101 0.096 51.185 0.12 ;
     RECT  51.112 2.418 51.304 23.502 ;
     RECT  51.304 7.104 52.297 7.128 ;
     RECT  51.304 22.08 52.297 22.104 ;
     RECT  52.297 6.672 52.369 7.368 ;
     RECT  52.297 21.648 52.381 22.104 ;
     RECT  52.333 25.056 52.499 25.08 ;
     RECT  52.369 6.624 52.621 7.368 ;
     RECT  52.693 0.096 52.787 0.12 ;
     RECT  51.304 2.496 52.873 5.208 ;
     RECT  52.621 6.336 52.873 7.368 ;
     RECT  52.873 2.496 53.021 7.368 ;
     RECT  53.021 2.496 53.093 5.208 ;
     RECT  53.021 6.336 53.093 7.368 ;
     RECT  53.093 6.672 53.129 7.368 ;
     RECT  53.129 7.344 53.309 7.368 ;
     RECT  52.381 22.08 53.845 22.104 ;
     RECT  53.845 21.984 53.885 22.104 ;
     RECT  54.373 0.096 54.569 0.12 ;
     RECT  54.421 25.776 54.605 25.8 ;
     RECT  53.885 21.984 54.789 22.008 ;
     RECT  53.093 2.496 55.213 4.2 ;
     RECT  53.093 5.184 55.213 5.208 ;
     RECT  54.789 21.744 55.525 22.008 ;
     RECT  56.005 0.096 56.089 0.12 ;
     RECT  56.321 23.904 56.405 23.928 ;
     RECT  55.213 2.496 56.408 5.208 ;
     RECT  51.304 11.808 56.408 16.536 ;
     RECT  51.304 20.64 56.408 20.664 ;
     RECT  55.525 21.744 56.408 22.728 ;
     RECT  56.408 2.148 56.512 23.772 ;
     RECT  56.512 2.418 56.704 23.502 ;
     RECT  56.704 21.648 57.197 21.768 ;
     RECT  57.625 0.096 57.709 0.12 ;
     RECT  58.261 24.48 58.529 24.504 ;
     RECT  57.197 21.648 59.033 21.672 ;
     RECT  59.245 0.096 59.329 0.12 ;
     RECT  59.365 22.704 59.452 22.728 ;
     RECT  60.14 23.952 60.227 23.976 ;
     RECT  56.704 2.496 60.865 4.2 ;
     RECT  60.865 1.728 60.949 4.2 ;
     RECT  60.949 2.148 61.237 4.2 ;
     RECT  56.704 5.184 61.237 5.208 ;
     RECT  61.237 2.148 61.808 5.208 ;
     RECT  56.704 11.808 61.808 16.536 ;
     RECT  56.704 20.64 61.808 20.664 ;
     RECT  59.245 21.696 61.808 21.72 ;
     RECT  61.808 2.148 61.912 23.772 ;
     RECT  61.912 2.418 62.104 23.502 ;
     RECT  61.945 24.48 62.147 24.504 ;
     RECT  62.104 21.696 62.453 21.96 ;
     RECT  62.521 0.096 62.605 0.12 ;
     RECT  62.453 21.936 63.097 21.96 ;
     RECT  63.097 21.936 63.137 22.152 ;
     RECT  64.021 25.056 64.217 25.08 ;
     RECT  64.141 0.096 64.225 0.12 ;
     RECT  65.761 0.096 65.845 0.12 ;
     RECT  63.137 22.128 66.013 22.152 ;
     RECT  65.941 23.904 66.125 23.928 ;
     RECT  62.104 2.496 67.208 4.2 ;
     RECT  62.104 5.184 67.208 5.208 ;
     RECT  62.104 11.808 67.208 16.536 ;
     RECT  62.104 20.64 67.208 20.664 ;
     RECT  66.013 21.744 67.208 22.152 ;
     RECT  67.208 2.148 67.312 23.772 ;
     RECT  67.312 2.148 67.409 23.502 ;
     RECT  67.409 1.728 67.493 23.502 ;
     RECT  67.493 2.418 67.504 23.502 ;
     RECT  67.861 25.776 68.141 25.8 ;
     RECT  67.504 21.648 68.285 22.44 ;
     RECT  68.929 0.096 69.107 0.12 ;
     RECT  69.649 23.952 69.827 23.976 ;
     RECT  68.285 21.648 70.261 21.672 ;
     RECT  70.261 21.648 70.301 22.2 ;
     RECT  67.504 2.496 70.693 4.2 ;
     RECT  67.504 5.184 70.693 5.208 ;
     RECT  67.504 11.808 70.693 16.536 ;
     RECT  70.693 1.728 70.913 5.208 ;
     RECT  70.301 22.176 71.561 22.2 ;
     RECT  71.729 23.904 71.813 23.928 ;
     RECT  70.913 2.496 72.305 5.208 ;
     RECT  72.305 1.728 72.389 5.208 ;
     RECT  72.389 2.148 72.608 5.208 ;
     RECT  72.469 8.496 72.608 8.52 ;
     RECT  70.693 11.712 72.608 16.536 ;
     RECT  67.504 20.64 72.608 20.664 ;
     RECT  71.917 21.792 72.608 21.816 ;
     RECT  72.608 2.148 72.712 23.772 ;
     RECT  72.712 2.418 72.904 23.772 ;
     RECT  72.904 2.496 73.289 5.208 ;
     RECT  72.904 6.864 73.715 8.28 ;
     RECT  73.669 23.904 73.973 23.928 ;
     RECT  73.933 0.096 74.017 0.12 ;
     RECT  72.904 20.64 74.081 21.96 ;
     RECT  73.289 2.496 74.293 4.2 ;
     RECT  73.289 5.184 74.293 5.208 ;
     RECT  73.715 8.16 74.297 8.28 ;
     RECT  74.297 8.16 74.333 8.184 ;
     RECT  73.715 6.864 75.049 6.888 ;
     RECT  74.293 2.496 75.125 5.208 ;
     RECT  75.337 23.712 75.635 23.736 ;
     RECT  75.589 0.096 75.673 0.12 ;
     RECT  75.049 6.864 75.697 6.936 ;
     RECT  74.081 21.936 75.697 21.96 ;
     RECT  75.697 6.24 75.875 6.936 ;
     RECT  75.875 6.912 76.205 6.936 ;
     RECT  75.841 8.208 76.489 8.232 ;
     RECT  75.125 3.936 76.633 5.208 ;
     RECT  76.489 7.344 77.137 8.232 ;
     RECT  75.125 2.496 77.201 2.808 ;
     RECT  77.201 1.728 77.285 2.808 ;
     RECT  77.281 25.104 77.555 25.128 ;
     RECT  75.697 21.936 77.605 22.344 ;
     RECT  77.285 2.148 77.785 2.808 ;
     RECT  76.633 3.888 77.785 5.208 ;
     RECT  77.785 2.148 78.008 5.208 ;
     RECT  77.137 7.344 78.008 8.568 ;
     RECT  72.904 11.808 78.008 16.536 ;
     RECT  74.081 20.64 78.008 20.664 ;
     RECT  77.605 21.936 78.008 22.488 ;
     RECT  78.008 2.148 78.112 23.772 ;
     RECT  78.112 2.418 78.304 23.502 ;
     RECT  78.304 7.392 78.437 8.664 ;
     RECT  78.437 8.208 78.733 8.664 ;
     RECT  78.829 0.096 78.913 0.12 ;
     RECT  79.189 25.776 79.475 25.8 ;
     RECT  78.304 21.744 79.513 22.488 ;
     RECT  78.304 2.496 79.553 5.64 ;
     RECT  79.477 7.2 80.005 7.224 ;
     RECT  78.733 8.208 80.005 8.232 ;
     RECT  80.005 7.2 80.051 8.232 ;
     RECT  80.485 0.096 80.597 0.12 ;
     RECT  79.553 2.496 81.395 5.208 ;
     RECT  81.133 23.904 81.395 23.928 ;
     RECT  80.051 8.016 81.692 8.04 ;
     RECT  81.692 7.92 81.733 8.04 ;
     RECT  81.733 7.92 81.779 8.472 ;
     RECT  78.304 20.64 81.973 20.664 ;
     RECT  81.973 20.592 81.997 20.664 ;
     RECT  82.033 0.096 82.163 0.12 ;
     RECT  79.513 21.744 82.321 22.536 ;
     RECT  78.304 11.808 82.645 16.536 ;
     RECT  83.005 25.104 83.315 25.128 ;
     RECT  81.395 2.496 83.408 2.808 ;
     RECT  81.395 3.84 83.408 5.208 ;
     RECT  81.779 8.448 83.408 8.472 ;
     RECT  82.645 11.712 83.408 16.536 ;
     RECT  81.997 20.304 83.408 20.664 ;
     RECT  82.321 21.696 83.408 22.536 ;
     RECT  83.408 2.148 83.512 23.772 ;
     RECT  83.512 2.148 83.704 23.502 ;
     RECT  83.704 2.148 83.717 2.808 ;
     RECT  83.717 1.728 83.801 2.808 ;
     RECT  83.704 3.84 83.801 5.208 ;
     RECT  83.801 2.496 85.165 2.808 ;
     RECT  84.949 23.712 85.235 23.736 ;
     RECT  85.165 1.728 85.427 2.808 ;
     RECT  85.427 2.496 85.484 2.808 ;
     RECT  83.801 3.984 85.484 5.208 ;
     RECT  85.484 2.496 85.571 5.208 ;
     RECT  83.704 20.304 85.597 20.664 ;
     RECT  85.597 20.304 86.245 20.856 ;
     RECT  83.704 21.984 86.245 22.488 ;
     RECT  85.571 2.496 86.785 2.808 ;
     RECT  86.785 1.728 87.059 2.808 ;
     RECT  86.893 23.712 87.155 23.736 ;
     RECT  83.704 11.664 87.257 16.536 ;
     RECT  86.245 20.304 87.257 22.488 ;
     RECT  87.257 20.304 88.225 21.768 ;
     RECT  87.059 2.496 88.405 2.808 ;
     RECT  88.405 1.728 88.691 2.808 ;
     RECT  88.691 2.148 88.765 2.808 ;
     RECT  85.571 3.936 88.765 5.208 ;
     RECT  88.765 2.148 88.808 5.208 ;
     RECT  83.704 8.448 88.808 8.472 ;
     RECT  87.257 11.664 88.808 16.296 ;
     RECT  88.225 20.304 88.808 22.488 ;
     RECT  88.808 2.148 88.912 23.772 ;
     RECT  88.912 2.418 89.104 23.502 ;
     RECT  88.765 25.104 89.123 25.128 ;
     RECT  90.205 0.576 90.289 0.6 ;
     RECT  90.781 23.712 91.043 23.736 ;
     RECT  89.104 2.496 91.793 5.208 ;
     RECT  89.104 20.304 91.825 22.488 ;
     RECT  91.789 0.576 91.907 0.6 ;
     RECT  91.825 20.304 92.041 22.776 ;
     RECT  92.041 20.304 92.125 22.824 ;
     RECT  92.125 20.304 92.153 22.776 ;
     RECT  91.793 4.176 92.797 5.208 ;
     RECT  92.689 25.776 92.963 25.8 ;
     RECT  93.481 0.576 93.565 0.6 ;
     RECT  91.793 2.496 93.625 2.808 ;
     RECT  92.797 3.984 93.625 5.208 ;
     RECT  93.625 2.496 94.208 5.208 ;
     RECT  89.104 8.448 94.208 8.472 ;
     RECT  89.104 11.664 94.208 16.296 ;
     RECT  92.153 20.304 94.208 22.056 ;
     RECT  94.208 2.148 94.504 23.772 ;
     RECT  94.633 23.904 94.883 23.928 ;
     RECT  94.504 2.148 94.885 5.208 ;
     RECT  94.885 1.728 95.171 5.208 ;
     RECT  94.504 11.664 95.605 16.296 ;
     RECT  95.564 17.568 95.605 17.592 ;
     RECT  95.605 11.664 95.651 17.592 ;
     RECT  94.504 20.304 96.365 22.248 ;
     RECT  95.171 2.496 96.749 5.208 ;
     RECT  96.505 23.712 96.803 23.736 ;
     RECT  96.749 1.728 96.833 5.208 ;
     RECT  95.651 11.664 96.905 17.208 ;
     RECT  96.905 11.664 96.949 17.112 ;
     RECT  96.365 20.304 97.837 21.912 ;
     RECT  96.833 2.496 98.125 5.208 ;
     RECT  98.125 1.728 98.435 5.208 ;
     RECT  96.949 11.664 98.449 17.016 ;
     RECT  98.449 11.664 98.489 17.4 ;
     RECT  98.489 12.576 98.492 17.4 ;
     RECT  98.435 2.496 98.561 5.208 ;
     RECT  98.485 18.816 98.569 18.84 ;
     RECT  98.492 12.576 98.594 17.448 ;
     RECT  98.594 12.576 98.633 17.4 ;
     RECT  98.449 25.104 98.723 25.128 ;
     RECT  98.561 2.496 99.608 2.52 ;
     RECT  98.561 3.696 99.608 5.208 ;
     RECT  94.504 8.448 99.608 8.472 ;
     RECT  98.633 12.576 99.608 16.824 ;
     RECT  97.837 20.304 99.608 22.248 ;
     RECT  99.608 2.148 99.817 23.772 ;
     RECT  99.817 1.728 99.904 23.772 ;
     RECT  99.904 1.728 100.067 2.52 ;
     RECT  100.357 23.904 100.643 23.928 ;
     RECT  99.904 12.576 100.865 16.824 ;
     RECT  100.865 12.864 100.973 16.824 ;
     RECT  100.067 2.496 101.077 2.52 ;
     RECT  99.904 3.84 101.077 5.208 ;
     RECT  101.077 2.496 101.473 5.208 ;
     RECT  100.933 18.24 101.693 18.264 ;
     RECT  101.473 1.728 101.699 5.208 ;
     RECT  100.973 12.864 102.053 16.296 ;
     RECT  102.301 23.904 102.563 23.928 ;
     RECT  102.053 13.056 102.625 16.296 ;
     RECT  102.589 17.472 102.625 17.496 ;
     RECT  101.699 2.496 102.629 5.208 ;
     RECT  99.904 21.744 102.665 22.248 ;
     RECT  102.625 13.056 102.989 17.496 ;
     RECT  102.841 10.848 103.141 10.872 ;
     RECT  102.989 13.056 103.235 16.584 ;
     RECT  103.165 0.576 103.331 0.6 ;
     RECT  103.235 13.056 103.34 16.488 ;
     RECT  103.34 12.528 103.427 16.488 ;
     RECT  103.141 10.176 103.525 10.872 ;
     RECT  99.904 20.304 103.571 20.328 ;
     RECT  103.525 10.176 103.597 11.4 ;
     RECT  99.904 8.448 103.621 8.472 ;
     RECT  103.597 10.176 103.681 11.496 ;
     RECT  103.681 10.176 103.715 11.4 ;
     RECT  104.173 25.104 104.483 25.128 ;
     RECT  102.629 2.496 104.893 2.52 ;
     RECT  102.629 3.984 104.893 5.208 ;
     RECT  104.893 0.576 104.977 0.6 ;
     RECT  104.893 2.496 105.008 5.208 ;
     RECT  103.621 8.16 105.008 8.472 ;
     RECT  103.715 10.176 105.008 11.16 ;
     RECT  103.427 13.056 105.008 16.488 ;
     RECT  104.749 20.4 105.008 20.424 ;
     RECT  102.665 21.744 105.008 21.768 ;
     RECT  105.008 2.148 105.112 23.772 ;
     RECT  105.112 2.418 105.304 23.502 ;
     RECT  105.304 20.4 105.617 20.424 ;
     RECT  105.304 2.496 105.905 5.208 ;
     RECT  105.304 9.408 106.067 11.16 ;
     RECT  106.067 9.408 106.108 9.816 ;
     RECT  105.905 2.496 106.333 2.52 ;
     RECT  106.117 23.712 106.403 23.736 ;
     RECT  105.304 21.744 106.477 21.768 ;
     RECT  105.304 6.816 106.585 6.84 ;
     RECT  106.333 1.728 106.595 2.52 ;
     RECT  106.508 20.544 106.595 20.568 ;
     RECT  106.477 21.744 106.595 22.296 ;
     RECT  105.905 3.936 106.597 5.208 ;
     RECT  106.585 6.816 106.643 6.936 ;
     RECT  106.643 6.912 106.669 6.936 ;
     RECT  106.597 3.936 106.697 5.832 ;
     RECT  106.549 19.344 106.985 19.368 ;
     RECT  105.304 13.056 107.273 17.112 ;
     RECT  107.273 13.056 107.377 16.68 ;
     RECT  107.377 12.24 107.813 16.68 ;
     RECT  106.108 9.792 107.881 9.816 ;
     RECT  106.067 10.992 107.881 11.16 ;
     RECT  106.697 4.08 107.885 5.832 ;
     RECT  106.595 2.496 107.953 2.52 ;
     RECT  105.304 8.16 107.989 8.184 ;
     RECT  107.813 13.056 108.029 16.68 ;
     RECT  107.881 9.792 108.035 11.16 ;
     RECT  107.989 8.16 108.076 8.52 ;
     RECT  107.953 1.728 108.227 2.52 ;
     RECT  108.227 2.496 108.277 2.52 ;
     RECT  107.885 4.08 108.277 5.208 ;
     RECT  108.061 25.104 108.371 25.128 ;
     RECT  108.668 19.92 108.755 19.944 ;
     RECT  108.277 2.496 108.889 5.208 ;
     RECT  108.709 21.12 108.893 21.144 ;
     RECT  108.035 10.608 108.997 11.16 ;
     RECT  108.029 13.056 109.145 16.584 ;
     RECT  108.997 10.608 109.321 11.256 ;
     RECT  109.321 10.608 109.361 11.544 ;
     RECT  108.889 2.496 109.427 5.736 ;
     RECT  109.145 13.056 109.427 16.008 ;
     RECT  109.427 2.496 109.573 5.208 ;
     RECT  109.573 1.728 109.859 5.208 ;
     RECT  109.859 2.148 110.408 5.208 ;
     RECT  108.076 8.16 110.408 8.184 ;
     RECT  109.361 10.848 110.408 11.544 ;
     RECT  109.427 13.056 110.408 15.624 ;
     RECT  106.595 22.272 110.408 22.296 ;
     RECT  110.005 23.712 110.408 23.736 ;
     RECT  110.408 2.148 110.512 23.772 ;
     RECT  110.512 2.148 110.704 23.502 ;
     RECT  110.704 12.432 111.017 15.72 ;
     RECT  110.704 2.148 111.193 2.856 ;
     RECT  110.704 11.232 111.203 11.448 ;
     RECT  110.704 22.272 111.341 22.296 ;
     RECT  111.193 1.728 111.491 2.856 ;
     RECT  110.704 21.12 111.601 21.144 ;
     RECT  111.491 2.496 111.683 2.856 ;
     RECT  110.704 3.84 111.737 5.208 ;
     RECT  111.203 11.424 111.845 11.448 ;
     RECT  111.017 12.432 111.98 15.192 ;
     RECT  111.98 12.432 111.989 15.48 ;
     RECT  111.989 12.528 112.021 15.48 ;
     RECT  111.949 23.712 112.211 23.736 ;
     RECT  112.021 12.528 112.601 16.008 ;
     RECT  113.065 0.576 113.149 0.6 ;
     RECT  111.737 4.128 113.353 5.208 ;
     RECT  113.077 10.464 113.393 10.488 ;
     RECT  111.683 2.496 113.605 2.52 ;
     RECT  113.353 3.792 113.605 5.208 ;
     RECT  112.601 12.528 113.645 15.768 ;
     RECT  113.645 12.528 113.789 15.528 ;
     RECT  110.704 8.16 113.893 9 ;
     RECT  113.789 13.008 113.897 15.528 ;
     RECT  113.893 7.968 113.977 9 ;
     RECT  113.977 8.16 114.077 9 ;
     RECT  113.857 25.776 114.131 25.8 ;
     RECT  114.613 0.576 114.755 0.6 ;
     RECT  113.425 22.176 114.937 22.2 ;
     RECT  113.605 2.496 115.808 5.208 ;
     RECT  114.077 8.976 115.808 9 ;
     RECT  113.897 13.008 115.808 15.192 ;
     RECT  114.937 21.792 115.808 22.2 ;
     RECT  115.808 2.148 115.912 23.772 ;
     RECT  115.912 2.418 115.981 23.772 ;
     RECT  115.981 2.418 116.065 23.928 ;
     RECT  116.065 2.418 116.104 23.502 ;
     RECT  116.341 0.576 116.425 0.6 ;
     RECT  116.104 21.408 117.059 22.488 ;
     RECT  117.529 23.904 117.971 23.928 ;
     RECT  117.953 0.576 118.037 0.6 ;
     RECT  116.104 8.976 118.429 9 ;
     RECT  118.429 8.544 118.513 9 ;
     RECT  118.513 8.976 118.613 9 ;
     RECT  117.059 22.464 118.789 22.488 ;
     RECT  118.789 22.224 118.829 22.488 ;
     RECT  116.104 2.496 119.365 5.208 ;
     RECT  119.365 1.728 119.651 5.208 ;
     RECT  119.617 25.104 119.891 25.128 ;
     RECT  119.651 2.496 121.021 5.208 ;
     RECT  118.829 22.224 121.165 22.248 ;
     RECT  121.021 1.728 121.208 5.208 ;
     RECT  116.104 13.008 121.208 15.192 ;
     RECT  121.165 22.224 121.208 22.584 ;
     RECT  121.208 1.728 121.283 23.772 ;
     RECT  121.283 2.148 121.312 23.772 ;
     RECT  121.312 2.418 121.504 23.772 ;
     RECT  121.525 23.904 121.811 23.928 ;
     RECT  121.504 22.416 122.069 22.584 ;
     RECT  122.069 22.416 122.099 22.44 ;
     RECT  121.504 2.496 122.531 5.208 ;
     RECT  122.531 2.496 122.641 4.2 ;
     RECT  122.641 1.728 122.915 4.2 ;
     RECT  121.504 21.408 123.037 21.432 ;
     RECT  123.469 25.776 123.731 25.8 ;
     RECT  123.037 21.408 123.761 22.2 ;
     RECT  122.915 2.496 124.261 4.2 ;
     RECT  124.261 1.728 124.547 4.2 ;
     RECT  122.531 5.184 125.413 5.208 ;
     RECT  125.413 23.904 125.699 23.928 ;
     RECT  123.761 22.176 125.881 22.2 ;
     RECT  126.025 0.576 126.179 0.6 ;
     RECT  124.547 2.496 126.608 4.2 ;
     RECT  125.413 5.184 126.608 5.496 ;
     RECT  121.504 13.008 126.608 15.192 ;
     RECT  125.653 16.896 126.608 16.92 ;
     RECT  125.881 22.032 126.608 22.2 ;
     RECT  126.608 2.148 126.712 23.772 ;
     RECT  126.712 2.418 126.904 23.772 ;
     RECT  126.904 16.896 127.001 17.064 ;
     RECT  126.904 22.032 127.145 22.2 ;
     RECT  127.357 23.904 127.619 23.928 ;
     RECT  127.753 0.576 127.837 0.6 ;
     RECT  129.373 0.576 129.457 0.6 ;
     RECT  128.977 25.776 129.539 25.8 ;
     RECT  126.904 13.344 130.525 15.192 ;
     RECT  127.145 22.176 130.645 22.2 ;
     RECT  130.645 21.648 130.691 22.2 ;
     RECT  126.904 2.496 130.813 4.2 ;
     RECT  130.813 1.728 131.075 4.2 ;
     RECT  131.075 2.148 132.008 4.2 ;
     RECT  126.904 5.184 132.008 5.496 ;
     RECT  130.525 13.344 132.008 15.288 ;
     RECT  127.001 17.04 132.008 17.064 ;
     RECT  130.691 21.648 132.008 21.672 ;
     RECT  131.173 23.712 132.008 23.736 ;
     RECT  132.008 2.148 132.112 23.772 ;
     RECT  132.112 2.148 132.304 23.502 ;
     RECT  132.304 2.148 132.433 4.2 ;
     RECT  132.433 1.728 132.707 4.2 ;
     RECT  132.304 13.344 133.091 15.288 ;
     RECT  133.091 14.448 133.193 15.288 ;
     RECT  132.304 22.08 133.285 22.488 ;
     RECT  132.304 17.088 133.309 17.304 ;
     RECT  133.309 17.28 133.365 17.304 ;
     RECT  133.117 23.712 133.379 23.736 ;
     RECT  132.707 2.496 134.053 4.2 ;
     RECT  134.053 1.728 134.339 4.2 ;
     RECT  135.025 25.776 135.299 25.8 ;
     RECT  134.339 2.496 135.677 4.2 ;
     RECT  135.677 2.496 135.709 2.52 ;
     RECT  135.709 1.728 135.971 2.52 ;
     RECT  133.285 21.696 136.021 22.488 ;
     RECT  136.021 21.648 136.109 22.488 ;
     RECT  135.971 2.496 136.837 2.52 ;
     RECT  135.677 3.84 136.837 4.2 ;
     RECT  136.969 23.904 137.219 23.928 ;
     RECT  136.837 2.496 137.408 4.2 ;
     RECT  132.304 5.184 137.408 5.496 ;
     RECT  133.091 13.344 137.408 13.368 ;
     RECT  133.193 14.448 137.408 14.472 ;
     RECT  136.109 21.696 137.408 22.488 ;
     RECT  137.408 2.148 137.512 23.772 ;
     RECT  137.365 0.576 137.603 0.6 ;
     RECT  137.512 2.418 137.704 23.502 ;
     RECT  137.704 21.696 138.913 22.2 ;
     RECT  138.841 25.104 139.139 25.128 ;
     RECT  139.093 0.576 139.235 0.6 ;
     RECT  137.704 2.496 140.101 2.52 ;
     RECT  137.704 3.84 140.101 4.2 ;
     RECT  138.913 21.648 140.573 22.2 ;
     RECT  140.821 0.576 140.905 0.6 ;
     RECT  140.965 23.904 141.059 23.928 ;
     RECT  140.101 2.496 142.189 4.2 ;
     RECT  142.189 1.728 142.499 4.2 ;
     RECT  140.573 21.648 142.693 22.104 ;
     RECT  142.499 2.148 142.808 4.2 ;
     RECT  137.704 5.184 142.808 5.496 ;
     RECT  137.704 13.344 142.808 13.368 ;
     RECT  137.704 14.448 142.808 14.472 ;
     RECT  142.693 21.12 142.808 22.104 ;
     RECT  142.729 23.856 142.808 23.88 ;
     RECT  142.808 2.148 142.912 23.88 ;
     RECT  142.912 2.418 143.027 23.88 ;
     RECT  143.027 2.418 143.104 23.502 ;
     RECT  143.104 2.496 144.085 2.52 ;
     RECT  144.085 1.728 144.173 2.52 ;
     RECT  143.104 5.184 144.853 5.496 ;
     RECT  144.673 25.104 144.947 25.128 ;
     RECT  143.104 3.84 144.997 4.2 ;
     RECT  144.173 2.496 145.501 2.52 ;
     RECT  145.501 1.728 145.763 2.52 ;
     RECT  145.763 2.496 145.825 2.52 ;
     RECT  144.997 3.552 145.825 4.2 ;
     RECT  143.104 21.12 145.825 22.008 ;
     RECT  145.825 21.12 146.261 22.824 ;
     RECT  146.252 16.944 146.293 16.968 ;
     RECT  145.825 2.496 146.297 4.2 ;
     RECT  146.261 21.12 146.297 22.776 ;
     RECT  146.293 16.944 146.339 17.64 ;
     RECT  144.853 5.184 146.396 5.736 ;
     RECT  146.401 19.392 146.437 19.416 ;
     RECT  146.293 15.84 146.441 15.864 ;
     RECT  146.297 21.12 146.441 21.144 ;
     RECT  146.396 5.184 146.483 6.264 ;
     RECT  146.396 7.296 146.483 7.32 ;
     RECT  146.396 8.4 146.483 8.424 ;
     RECT  146.437 18.768 146.485 19.416 ;
     RECT  146.297 3.408 146.617 4.2 ;
     RECT  146.483 5.184 146.617 5.304 ;
     RECT  146.617 3.408 146.657 5.304 ;
     RECT  146.257 9.504 146.677 9.528 ;
     RECT  146.645 11.424 146.677 11.448 ;
     RECT  146.677 9.504 146.723 11.448 ;
     RECT  146.723 10.464 146.729 11.448 ;
     RECT  146.339 17.616 146.729 17.64 ;
     RECT  146.485 18.768 146.729 18.792 ;
     RECT  146.729 10.464 146.764 10.824 ;
     RECT  146.657 3.408 146.837 5.208 ;
     RECT  146.581 23.904 146.867 23.928 ;
     RECT  146.837 3.408 147.197 4.248 ;
     RECT  147.049 1.728 147.347 1.752 ;
     RECT  147.197 3.552 148.208 4.248 ;
     RECT  146.764 10.8 148.208 10.824 ;
     RECT  143.104 13.344 148.208 13.368 ;
     RECT  143.104 14.448 148.208 14.472 ;
     RECT  146.297 22.752 148.208 22.776 ;
     RECT  148.208 2.148 148.312 23.772 ;
     RECT  148.312 2.304 148.504 23.502 ;
     RECT  148.504 23.376 148.787 23.4 ;
     RECT  148.504 2.304 148.979 2.568 ;
    LAYER M5 ;
     RECT  2.4 2.137 2.52 2.151 ;
     RECT  7.8 2.137 7.92 2.151 ;
     RECT  13.2 2.137 13.32 2.151 ;
     RECT  18.6 2.137 18.72 2.151 ;
     RECT  29.4 2.137 29.52 2.151 ;
     RECT  34.8 2.137 34.92 2.151 ;
     RECT  40.2 2.137 40.32 2.151 ;
     RECT  51 2.137 51.12 2.151 ;
     RECT  56.4 2.137 56.52 2.151 ;
     RECT  61.8 2.137 61.92 2.151 ;
     RECT  67.2 2.137 67.464 2.151 ;
     RECT  72.6 2.137 72.72 2.151 ;
     RECT  78 2.137 78.12 2.151 ;
     RECT  88.8 2.137 88.92 2.151 ;
     RECT  105 2.137 105.12 2.151 ;
     RECT  115.8 2.137 115.92 2.151 ;
     RECT  121.2 2.137 121.32 2.151 ;
     RECT  126.6 2.137 126.72 2.151 ;
     RECT  137.4 2.137 137.52 2.151 ;
     RECT  142.8 2.137 142.92 2.151 ;
     RECT  40.2 2.151 41.352 2.339 ;
     RECT  45.6 2.137 46.248 2.339 ;
     RECT  148.2 2.137 148.968 2.339 ;
     RECT  110.4 2.137 110.712 2.821 ;
     RECT  61.8 2.151 62.112 3.397 ;
     RECT  121.2 2.151 121.512 3.397 ;
     RECT  137.4 2.151 137.712 3.397 ;
     RECT  4.464 2.821 4.488 3.443 ;
     RECT  59.568 2.821 59.592 3.635 ;
     RECT  56.4 2.151 56.712 3.829 ;
     RECT  124.224 3.397 124.248 3.923 ;
     RECT  45.6 2.339 45.912 3.925 ;
     RECT  15.6 3.397 15.624 3.971 ;
     RECT  85.536 3.205 85.56 4.019 ;
     RECT  146.448 3.397 146.472 4.067 ;
     RECT  81.36 3.397 81.384 4.115 ;
     RECT  97.728 3.685 97.752 4.115 ;
     RECT  120.528 3.397 121.512 4.115 ;
     RECT  136.848 3.397 137.712 4.115 ;
     RECT  140.112 3.397 140.136 4.115 ;
     RECT  108.288 2.725 108.312 4.259 ;
     RECT  101.088 3.397 101.112 4.355 ;
     RECT  78 2.151 78.312 4.453 ;
     RECT  61.248 3.397 62.112 4.499 ;
     RECT  74.64 3.397 74.664 4.595 ;
     RECT  122.496 3.301 122.52 4.595 ;
     RECT  76.176 3.925 76.2 4.691 ;
     RECT  77.184 4.453 78.312 4.789 ;
     RECT  126.6 2.151 126.912 5.461 ;
     RECT  77.184 4.789 79.272 5.651 ;
     RECT  109.392 4.645 109.416 5.747 ;
     RECT  72.6 2.151 72.912 6.853 ;
     RECT  75.84 6.229 75.864 6.947 ;
     RECT  106.608 3.925 106.632 6.947 ;
     RECT  72.6 6.853 73.704 7.475 ;
     RECT  113.904 3.829 113.928 8.003 ;
     RECT  103.68 4.357 103.704 8.149 ;
     RECT  77.184 5.651 78.312 8.197 ;
     RECT  80.016 7.189 80.04 8.243 ;
     RECT  81.744 7.909 81.768 8.483 ;
     RECT  72.6 7.475 72.912 8.485 ;
     RECT  77.184 8.197 78.696 8.579 ;
     RECT  118.464 3.157 118.488 8.579 ;
     RECT  78 8.579 78.696 8.675 ;
     RECT  7.8 2.151 8.112 9.061 ;
     RECT  105 2.151 105.312 9.397 ;
     RECT  146.448 6.229 146.472 9.493 ;
     RECT  146.448 9.493 146.712 9.539 ;
     RECT  108 8.485 108.024 9.827 ;
     RECT  103.632 8.149 103.704 10.165 ;
     RECT  105 9.397 106.056 10.211 ;
     RECT  7.104 9.061 8.112 10.595 ;
     RECT  103.152 10.165 103.704 10.883 ;
     RECT  103.536 10.883 103.704 11.411 ;
     RECT  146.688 9.539 146.712 11.459 ;
     RECT  103.536 11.411 103.656 11.507 ;
     RECT  6 4.501 6.024 11.845 ;
     RECT  7.8 10.595 8.112 11.989 ;
     RECT  5.904 11.845 6.264 12.037 ;
     RECT  40.2 2.339 40.512 12.037 ;
     RECT  72.48 8.485 72.912 12.037 ;
     RECT  40.2 12.037 41.256 12.275 ;
     RECT  5.088 12.037 6.264 12.515 ;
     RECT  103.536 11.507 103.56 12.517 ;
     RECT  5.088 12.515 5.928 12.563 ;
     RECT  72.48 12.037 73.032 12.563 ;
     RECT  113.088 10.453 113.112 12.563 ;
     RECT  51 2.151 51.312 12.565 ;
     RECT  44.688 3.925 45.912 12.611 ;
     RECT  72.6 12.563 73.032 12.659 ;
     RECT  51 12.565 51.912 12.709 ;
     RECT  51 12.709 52.344 12.755 ;
     RECT  55.584 3.829 56.712 12.755 ;
     RECT  32.688 12.325 32.712 12.803 ;
     RECT  40.2 12.275 40.824 12.851 ;
     RECT  58.992 12.517 59.016 12.995 ;
     RECT  2.4 2.151 2.712 13.045 ;
     RECT  36.096 13.141 36.12 13.331 ;
     RECT  18.6 2.151 18.912 13.333 ;
     RECT  115.8 2.151 116.112 13.573 ;
     RECT  72.6 12.659 72.912 13.621 ;
     RECT  4.608 12.949 4.632 13.667 ;
     RECT  27.888 12.277 27.912 13.669 ;
     RECT  27.648 13.669 27.912 13.715 ;
     RECT  5.904 12.563 5.928 13.813 ;
     RECT  132 2.137 132.312 13.813 ;
     RECT  95.664 12.949 95.688 13.955 ;
     RECT  110.4 2.821 111.672 14.101 ;
     RECT  19.968 3.397 19.992 14.147 ;
     RECT  115.152 13.573 116.112 14.147 ;
     RECT  5.04 13.813 5.928 14.197 ;
     RECT  18.48 13.333 18.912 14.291 ;
     RECT  103.392 12.517 103.56 14.627 ;
     RECT  97.296 13.621 97.32 14.963 ;
     RECT  103.488 14.627 103.56 15.685 ;
     RECT  109.392 14.389 109.416 16.019 ;
     RECT  110.4 14.101 112.056 16.019 ;
     RECT  7.8 11.989 8.424 16.405 ;
     RECT  103.2 15.685 103.56 16.595 ;
     RECT  125.664 5.461 126.912 16.931 ;
     RECT  132 13.813 133.08 17.077 ;
     RECT  96.912 16.981 96.936 17.123 ;
     RECT  132 17.077 133.272 17.269 ;
     RECT  98.496 16.501 98.52 17.413 ;
     RECT  146.304 15.829 146.328 17.651 ;
     RECT  5.04 14.197 6.072 17.989 ;
     RECT  7.152 16.405 8.424 17.989 ;
     RECT  5.04 17.989 8.424 18.611 ;
     RECT  98.496 17.413 98.568 18.851 ;
     RECT  146.448 18.757 146.472 19.427 ;
     RECT  7.68 18.611 8.424 19.571 ;
     RECT  5.04 18.611 6.072 20.003 ;
     RECT  103.536 16.595 103.56 20.339 ;
     RECT  5.04 20.003 5.928 20.579 ;
     RECT  7.8 19.571 8.424 20.579 ;
     RECT  106.56 19.333 106.584 20.579 ;
     RECT  98.544 18.851 98.568 20.867 ;
     RECT  99.6 2.137 99.912 20.965 ;
     RECT  3.936 20.533 3.96 21.107 ;
     RECT  5.904 20.579 5.928 21.155 ;
     RECT  27.648 13.715 27.672 21.155 ;
     RECT  108.72 19.909 108.744 21.155 ;
     RECT  110.4 16.019 111.576 21.155 ;
     RECT  115.8 14.147 116.112 21.397 ;
     RECT  121.2 4.115 121.512 21.397 ;
     RECT  67.2 2.151 67.512 21.637 ;
     RECT  52.32 12.755 52.344 21.683 ;
     RECT  132 17.269 133.32 21.731 ;
     RECT  56.4 12.755 56.712 21.733 ;
     RECT  81.984 20.581 82.008 21.779 ;
     RECT  95.616 17.029 95.64 21.779 ;
     RECT  98.976 20.965 99.912 21.779 ;
     RECT  34.8 2.151 35.112 21.925 ;
     RECT  72.6 13.621 73.752 21.971 ;
     RECT  54.816 21.733 56.712 22.019 ;
     RECT  30.72 21.397 30.744 22.211 ;
     RECT  130.656 21.637 130.68 22.211 ;
     RECT  136.032 21.637 136.056 22.211 ;
     RECT  11.232 21.925 11.256 22.259 ;
     RECT  34.32 21.925 35.112 22.259 ;
     RECT  80.448 21.733 80.472 22.307 ;
     RECT  106.56 21.733 106.584 22.307 ;
     RECT  67.2 21.637 68.232 22.451 ;
     RECT  121.2 21.397 122.088 22.451 ;
     RECT  90.096 21.397 90.12 22.499 ;
     RECT  115.8 21.397 117.048 22.499 ;
     RECT  132 21.731 133.272 22.499 ;
     RECT  43.824 21.925 43.848 22.739 ;
     RECT  55.536 22.019 56.712 22.739 ;
     RECT  59.376 21.685 59.4 22.739 ;
     RECT  92.064 20.293 92.088 22.835 ;
     RECT  45.6 12.611 45.912 23.365 ;
     RECT  51 12.755 51.312 23.365 ;
     RECT  148.2 2.339 148.512 23.365 ;
     RECT  110.4 21.155 110.712 23.701 ;
     RECT  132 22.499 132.312 23.701 ;
     RECT  1.488 13.045 2.712 23.769 ;
     RECT  18.6 14.291 18.912 23.769 ;
     RECT  24 2.137 24.312 23.769 ;
     RECT  29.4 2.151 29.712 23.769 ;
     RECT  45.6 23.365 46.728 23.769 ;
     RECT  50.544 23.365 51.312 23.769 ;
     RECT  56.4 22.739 56.712 23.769 ;
     RECT  67.2 22.451 67.512 23.769 ;
     RECT  78 8.675 78.312 23.769 ;
     RECT  83.4 2.137 83.712 23.769 ;
     RECT  88.8 2.151 89.112 23.769 ;
     RECT  105 10.211 105.312 23.769 ;
     RECT  110.256 23.701 110.712 23.769 ;
     RECT  115.8 22.499 116.112 23.769 ;
     RECT  131.424 23.701 132.312 23.769 ;
     RECT  137.4 4.115 137.712 23.769 ;
     RECT  142.8 2.151 143.112 23.769 ;
     RECT  1.488 23.769 2.52 23.783 ;
     RECT  7.8 20.579 8.112 23.783 ;
     RECT  13.2 2.151 13.512 23.783 ;
     RECT  18.6 23.769 18.72 23.783 ;
     RECT  24 23.769 24.12 23.783 ;
     RECT  29.4 23.769 29.52 23.783 ;
     RECT  34.8 22.259 35.112 23.783 ;
     RECT  40.2 12.851 40.512 23.783 ;
     RECT  45.6 23.769 45.72 23.783 ;
     RECT  50.544 23.769 51.12 23.783 ;
     RECT  56.4 23.769 56.52 23.783 ;
     RECT  61.8 4.499 62.112 23.783 ;
     RECT  67.2 23.769 67.32 23.783 ;
     RECT  72.6 21.971 72.912 23.783 ;
     RECT  78 23.769 78.12 23.783 ;
     RECT  83.4 23.769 83.52 23.783 ;
     RECT  88.8 23.769 88.92 23.783 ;
     RECT  94.2 2.137 94.512 23.783 ;
     RECT  99.6 21.779 99.912 23.783 ;
     RECT  105 23.769 105.12 23.783 ;
     RECT  110.256 23.769 110.52 23.783 ;
     RECT  115.8 23.769 116.04 23.783 ;
     RECT  121.2 22.451 121.512 23.783 ;
     RECT  126.6 16.931 126.912 23.783 ;
     RECT  131.424 23.769 132.12 23.783 ;
     RECT  137.4 23.769 137.52 23.783 ;
     RECT  142.8 23.769 143.016 23.783 ;
     RECT  148.2 23.365 148.776 23.783 ;
     RECT  121.512 3.301 122.496 4.595 ;
     RECT  18.912 3.397 19.968 14.147 ;
     RECT  99.912 3.397 101.088 4.355 ;
     RECT  74.664 3.925 76.176 4.595 ;
     RECT  105.312 3.925 106.608 6.947 ;
     RECT  103.704 4.357 105 11.411 ;
     RECT  76.2 4.453 77.184 4.691 ;
     RECT  109.416 4.645 110.4 5.747 ;
     RECT  75.864 6.229 77.184 6.947 ;
     RECT  78.696 8.197 80.016 8.243 ;
     RECT  6.024 9.061 7.104 10.595 ;
     RECT  146.712 9.493 148.2 11.459 ;
     RECT  111.672 10.453 113.088 12.563 ;
     RECT  6.024 10.595 6.264 11.845 ;
     RECT  103.656 11.411 105 11.507 ;
     RECT  103.56 11.507 105 20.339 ;
     RECT  27.912 12.277 29.4 13.715 ;
     RECT  5.088 12.563 5.904 12.949 ;
     RECT  72.912 12.659 73.032 13.621 ;
     RECT  51.312 12.755 52.32 21.683 ;
     RECT  4.632 12.949 5.904 13.667 ;
     RECT  94.512 12.949 95.664 13.955 ;
     RECT  35.112 13.141 36.096 13.331 ;
     RECT  5.04 13.667 5.904 13.813 ;
     RECT  109.416 14.389 110.4 16.019 ;
     RECT  103.392 14.627 103.488 15.685 ;
     RECT  6.072 16.405 7.152 17.989 ;
     RECT  98.52 16.501 99.6 17.413 ;
     RECT  94.512 17.029 95.616 21.779 ;
     RECT  95.64 17.029 96.912 17.123 ;
     RECT  98.568 17.413 99.6 20.867 ;
     RECT  105.312 19.333 106.56 20.579 ;
     RECT  2.712 20.533 3.936 21.107 ;
     RECT  3.96 20.533 5.04 20.579 ;
     RECT  105.312 20.579 106.584 21.733 ;
     RECT  82.008 20.581 83.4 21.779 ;
     RECT  98.976 20.867 99.6 20.965 ;
     RECT  29.712 21.397 30.72 22.211 ;
     RECT  89.112 21.397 90.096 22.499 ;
     RECT  130.68 21.637 132 22.211 ;
     RECT  136.056 21.637 137.4 22.211 ;
     RECT  80.472 21.733 81.984 21.779 ;
     RECT  105.312 21.733 106.56 22.307 ;
     RECT  131.424 22.211 132 23.701 ;
  END
END qkd_static_kv_landing_row
END LIBRARY
